VERSION 5.7 ;
  NOWIREEXTENSIONATPIN ON ;
  DIVIDERCHAR "/" ;
  BUSBITCHARS "[]" ;
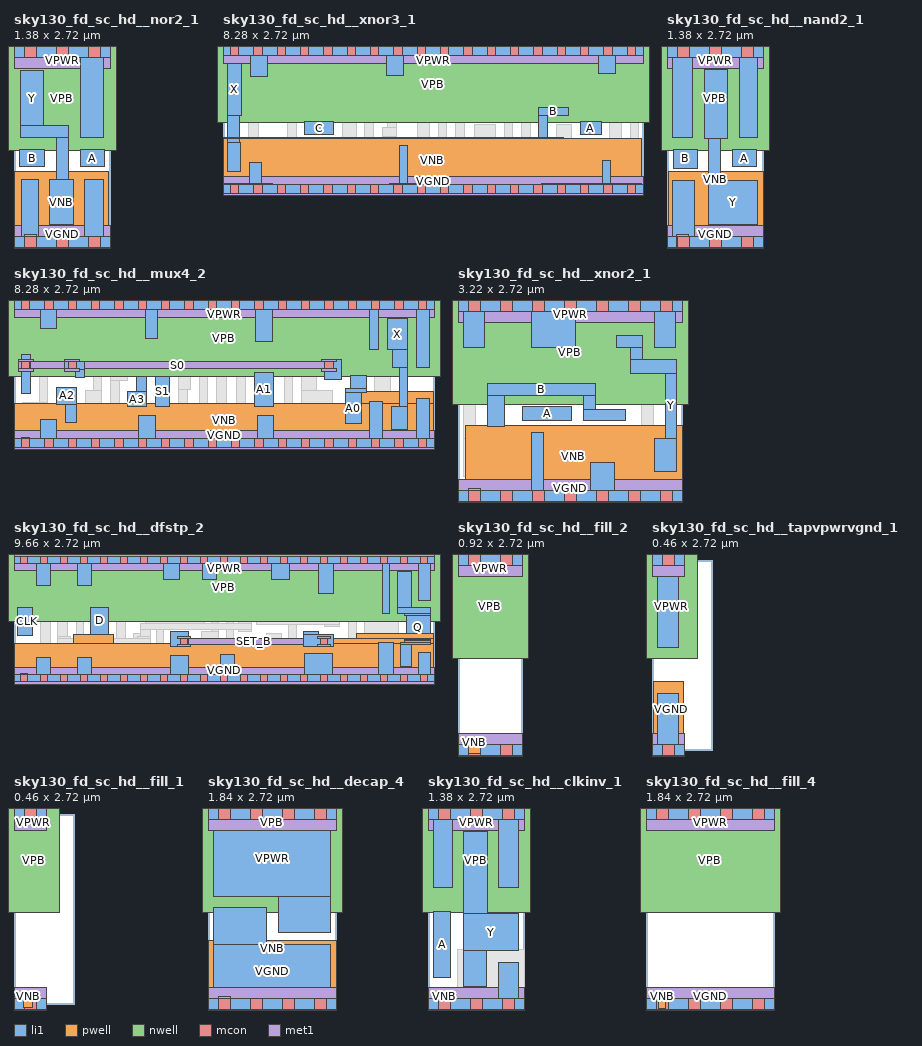
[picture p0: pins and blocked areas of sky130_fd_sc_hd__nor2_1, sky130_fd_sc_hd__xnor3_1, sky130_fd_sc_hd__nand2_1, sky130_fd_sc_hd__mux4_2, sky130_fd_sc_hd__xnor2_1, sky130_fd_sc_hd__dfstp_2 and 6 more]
MACRO sky130_fd_sc_hd__nor2_1
  CLASS BLOCK ;
  FOREIGN sky130_fd_sc_hd__nor2_1 ;
  ORIGIN 0.000 0.000 ;
  SIZE 1.380 BY 2.720 ;
  PIN B
    ANTENNAGATEAREA 0.247500 ;
    PORT
      LAYER li1 ;
        RECT 0.085 1.075 0.435 1.325 ;
    END
  END B
  PIN Y
    ANTENNADIFFAREA 0.435500 ;
    PORT
      LAYER li1 ;
        RECT 0.095 1.665 0.425 2.450 ;
        RECT 0.095 1.495 0.775 1.665 ;
        RECT 0.605 0.895 0.775 1.495 ;
        RECT 0.515 0.255 0.845 0.895 ;
    END
  END Y
  PIN A
    ANTENNAGATEAREA 0.247500 ;
    PORT
      LAYER li1 ;
        RECT 0.945 1.075 1.295 1.325 ;
    END
  END A
  PIN VNB
    PORT
      LAYER pwell ;
        RECT 0.005 0.105 1.355 1.015 ;
        RECT 0.150 -0.085 0.320 0.105 ;
    END
  END VNB
  PIN VPB
    PORT
      LAYER nwell ;
        RECT -0.190 1.305 1.570 2.910 ;
    END
  END VPB
  PIN VGND
    USE GROUND ;
    PORT
      LAYER li1 ;
        RECT 0.105 0.085 0.345 0.895 ;
        RECT 1.015 0.085 1.285 0.895 ;
        RECT 0.000 -0.085 1.380 0.085 ;
      LAYER mcon ;
        RECT 0.145 -0.085 0.315 0.085 ;
        RECT 0.605 -0.085 0.775 0.085 ;
        RECT 1.065 -0.085 1.235 0.085 ;
      LAYER met1 ;
        RECT 0.000 -0.240 1.380 0.240 ;
    END
  END VGND
  PIN VPWR
    USE POWER ;
    PORT
      LAYER li1 ;
        RECT 0.000 2.635 1.380 2.805 ;
        RECT 0.955 1.495 1.285 2.635 ;
      LAYER mcon ;
        RECT 0.145 2.635 0.315 2.805 ;
        RECT 0.605 2.635 0.775 2.805 ;
        RECT 1.065 2.635 1.235 2.805 ;
      LAYER met1 ;
        RECT 0.000 2.480 1.380 2.960 ;
    END
  END VPWR
END sky130_fd_sc_hd__nor2_1
MACRO VIA_M2M3_PR
  CLASS BLOCK ;
  FOREIGN VIA_M2M3_PR ;
  ORIGIN 0.165 0.185 ;
  SIZE 0.330 BY 0.370 ;
  OBS
      LAYER met2 ;
        RECT -0.140 -0.185 0.140 0.185 ;
      LAYER via2 ;
        RECT -0.140 -0.140 0.140 0.140 ;
      LAYER met3 ;
        RECT -0.165 -0.165 0.165 0.165 ;
  END
END VIA_M2M3_PR
MACRO sky130_fd_sc_hd__xnor3_1
  CLASS BLOCK ;
  FOREIGN sky130_fd_sc_hd__xnor3_1 ;
  ORIGIN 0.000 0.000 ;
  SIZE 8.280 BY 2.720 ;
  PIN X
    ANTENNADIFFAREA 0.449000 ;
    PORT
      LAYER li1 ;
        RECT 0.085 1.440 0.365 2.465 ;
        RECT 0.085 0.925 0.330 1.440 ;
        RECT 0.085 0.350 0.345 0.925 ;
    END
  END X
  PIN B
    ANTENNAGATEAREA 0.661500 ;
    PORT
      LAYER li1 ;
        RECT 6.225 1.445 6.805 1.615 ;
        RECT 6.225 0.995 6.395 1.445 ;
    END
  END B
  PIN C
    ANTENNAGATEAREA 0.381000 ;
    PORT
      LAYER li1 ;
        RECT 1.615 1.075 2.180 1.325 ;
    END
  END C
  PIN A
    ANTENNAGATEAREA 0.246000 ;
    PORT
      LAYER li1 ;
        RECT 7.045 1.075 7.455 1.325 ;
    END
  END A
  PIN VNB
    PORT
      LAYER pwell ;
        RECT 0.005 1.005 6.705 1.015 ;
        RECT 0.005 0.115 8.260 1.005 ;
        RECT 0.005 0.105 0.985 0.115 ;
        RECT 3.275 0.105 4.225 0.115 ;
        RECT 6.280 0.105 8.260 0.115 ;
        RECT 0.145 -0.085 0.315 0.105 ;
    END
  END VNB
  PIN VPB
    PORT
      LAYER nwell ;
        RECT -0.190 1.305 8.470 2.910 ;
    END
  END VPB
  PIN VGND
    USE GROUND ;
    PORT
      LAYER li1 ;
        RECT 0.515 0.085 0.765 0.525 ;
        RECT 3.475 0.085 3.645 0.865 ;
        RECT 7.475 0.085 7.645 0.565 ;
        RECT 0.000 -0.085 8.280 0.085 ;
      LAYER mcon ;
        RECT 0.145 -0.085 0.315 0.085 ;
        RECT 0.605 -0.085 0.775 0.085 ;
        RECT 1.065 -0.085 1.235 0.085 ;
        RECT 1.525 -0.085 1.695 0.085 ;
        RECT 1.985 -0.085 2.155 0.085 ;
        RECT 2.445 -0.085 2.615 0.085 ;
        RECT 2.905 -0.085 3.075 0.085 ;
        RECT 3.365 -0.085 3.535 0.085 ;
        RECT 3.825 -0.085 3.995 0.085 ;
        RECT 4.285 -0.085 4.455 0.085 ;
        RECT 4.745 -0.085 4.915 0.085 ;
        RECT 5.205 -0.085 5.375 0.085 ;
        RECT 5.665 -0.085 5.835 0.085 ;
        RECT 6.125 -0.085 6.295 0.085 ;
        RECT 6.585 -0.085 6.755 0.085 ;
        RECT 7.045 -0.085 7.215 0.085 ;
        RECT 7.505 -0.085 7.675 0.085 ;
        RECT 7.965 -0.085 8.135 0.085 ;
      LAYER met1 ;
        RECT 0.000 -0.240 8.280 0.240 ;
    END
  END VGND
  PIN VPWR
    USE POWER ;
    PORT
      LAYER li1 ;
        RECT 0.000 2.635 8.280 2.805 ;
        RECT 0.535 2.215 0.870 2.635 ;
        RECT 3.225 2.235 3.555 2.635 ;
        RECT 7.395 2.275 7.730 2.635 ;
      LAYER mcon ;
        RECT 0.145 2.635 0.315 2.805 ;
        RECT 0.605 2.635 0.775 2.805 ;
        RECT 1.065 2.635 1.235 2.805 ;
        RECT 1.525 2.635 1.695 2.805 ;
        RECT 1.985 2.635 2.155 2.805 ;
        RECT 2.445 2.635 2.615 2.805 ;
        RECT 2.905 2.635 3.075 2.805 ;
        RECT 3.365 2.635 3.535 2.805 ;
        RECT 3.825 2.635 3.995 2.805 ;
        RECT 4.285 2.635 4.455 2.805 ;
        RECT 4.745 2.635 4.915 2.805 ;
        RECT 5.205 2.635 5.375 2.805 ;
        RECT 5.665 2.635 5.835 2.805 ;
        RECT 6.125 2.635 6.295 2.805 ;
        RECT 6.585 2.635 6.755 2.805 ;
        RECT 7.045 2.635 7.215 2.805 ;
        RECT 7.505 2.635 7.675 2.805 ;
        RECT 7.965 2.635 8.135 2.805 ;
      LAYER met1 ;
        RECT 0.000 2.480 8.280 2.960 ;
    END
  END VPWR
  OBS
      LAYER li1 ;
        RECT 1.050 2.235 2.520 2.405 ;
        RECT 3.890 2.275 6.985 2.445 ;
        RECT 1.050 2.045 1.220 2.235 ;
        RECT 3.890 2.065 4.060 2.275 ;
        RECT 0.535 1.875 1.220 2.045 ;
        RECT 1.560 1.895 4.060 2.065 ;
        RECT 0.535 1.325 0.705 1.875 ;
        RECT 0.935 1.535 2.520 1.705 ;
        RECT 0.500 0.995 0.705 1.325 ;
        RECT 0.530 0.865 0.705 0.995 ;
        RECT 0.530 0.695 1.105 0.865 ;
        RECT 0.935 0.425 1.105 0.695 ;
        RECT 1.275 0.595 1.445 1.535 ;
        RECT 2.350 1.325 2.520 1.535 ;
        RECT 2.690 1.525 3.075 1.695 ;
        RECT 2.795 1.375 3.075 1.525 ;
        RECT 2.350 0.995 2.625 1.325 ;
        RECT 1.745 0.795 2.125 0.905 ;
        RECT 2.795 0.795 2.965 1.375 ;
        RECT 3.245 1.205 3.415 1.895 ;
        RECT 3.645 1.445 4.065 1.715 ;
        RECT 1.745 0.625 2.965 0.795 ;
        RECT 3.135 1.035 3.415 1.205 ;
        RECT 3.135 0.455 3.305 1.035 ;
        RECT 2.070 0.425 2.505 0.455 ;
        RECT 0.935 0.255 2.505 0.425 ;
        RECT 2.675 0.285 3.305 0.455 ;
        RECT 3.825 0.415 4.065 1.445 ;
        RECT 4.245 0.595 4.415 2.105 ;
        RECT 4.585 0.890 4.755 2.275 ;
        RECT 7.900 2.105 8.195 2.465 ;
        RECT 4.935 1.615 5.350 2.045 ;
        RECT 5.885 1.935 8.195 2.105 ;
        RECT 4.935 1.445 5.715 1.615 ;
        RECT 4.950 0.995 5.375 1.270 ;
        RECT 4.585 0.825 4.795 0.890 ;
        RECT 4.585 0.720 4.995 0.825 ;
        RECT 4.625 0.655 4.995 0.720 ;
        RECT 4.245 0.485 4.455 0.595 ;
        RECT 4.245 0.265 4.655 0.485 ;
        RECT 4.825 0.320 4.995 0.655 ;
        RECT 5.165 0.630 5.375 0.995 ;
        RECT 5.545 0.425 5.715 1.445 ;
        RECT 5.885 0.595 6.055 1.935 ;
        RECT 7.710 1.875 8.195 1.935 ;
        RECT 6.975 1.495 7.795 1.705 ;
        RECT 7.625 1.325 7.795 1.495 ;
        RECT 6.565 0.945 6.875 1.275 ;
        RECT 7.625 0.995 7.855 1.325 ;
        RECT 6.565 0.730 6.770 0.945 ;
        RECT 7.625 0.905 7.795 0.995 ;
        RECT 7.055 0.750 7.795 0.905 ;
        RECT 7.015 0.735 7.795 0.750 ;
        RECT 6.225 0.425 6.690 0.465 ;
        RECT 5.545 0.255 6.690 0.425 ;
        RECT 7.015 0.295 7.305 0.735 ;
        RECT 8.025 0.585 8.195 1.875 ;
        RECT 7.895 0.255 8.195 0.585 ;
      LAYER mcon ;
        RECT 2.905 1.445 3.075 1.615 ;
        RECT 3.825 0.765 3.995 0.935 ;
        RECT 5.205 1.445 5.375 1.615 ;
        RECT 4.285 0.425 4.455 0.595 ;
        RECT 5.205 0.765 5.375 0.935 ;
        RECT 6.585 0.765 6.755 0.935 ;
        RECT 7.045 0.425 7.215 0.595 ;
      LAYER met1 ;
        RECT 2.845 1.600 3.135 1.645 ;
        RECT 5.145 1.600 5.435 1.645 ;
        RECT 2.845 1.460 5.435 1.600 ;
        RECT 2.845 1.415 3.135 1.460 ;
        RECT 5.145 1.415 5.435 1.460 ;
        RECT 3.765 0.920 4.055 0.965 ;
        RECT 5.145 0.920 5.435 0.965 ;
        RECT 6.525 0.920 6.815 0.965 ;
        RECT 3.765 0.780 6.815 0.920 ;
        RECT 3.765 0.735 4.055 0.780 ;
        RECT 5.145 0.735 5.435 0.780 ;
        RECT 6.525 0.735 6.815 0.780 ;
        RECT 4.225 0.580 4.515 0.625 ;
        RECT 6.985 0.580 7.275 0.625 ;
        RECT 4.225 0.440 7.275 0.580 ;
        RECT 4.225 0.395 4.515 0.440 ;
        RECT 6.985 0.395 7.275 0.440 ;
  END
END sky130_fd_sc_hd__xnor3_1
MACRO sky130_fd_sc_hd__nand2_1
  CLASS BLOCK ;
  FOREIGN sky130_fd_sc_hd__nand2_1 ;
  ORIGIN 0.000 0.000 ;
  SIZE 1.380 BY 2.720 ;
  PIN Y
    ANTENNADIFFAREA 0.439000 ;
    PORT
      LAYER li1 ;
        RECT 0.535 1.485 0.865 2.465 ;
        RECT 0.600 0.885 0.770 1.485 ;
        RECT 0.600 0.255 1.295 0.885 ;
    END
  END Y
  PIN B
    ANTENNAGATEAREA 0.247500 ;
    PORT
      LAYER li1 ;
        RECT 0.095 1.055 0.430 1.325 ;
    END
  END B
  PIN A
    ANTENNAGATEAREA 0.247500 ;
    PORT
      LAYER li1 ;
        RECT 0.940 1.075 1.275 1.325 ;
    END
  END A
  PIN VNB
    PORT
      LAYER pwell ;
        RECT 0.025 0.105 1.375 1.015 ;
        RECT 0.140 -0.085 0.310 0.105 ;
    END
  END VNB
  PIN VPB
    PORT
      LAYER nwell ;
        RECT -0.190 1.305 1.570 2.910 ;
    END
  END VPB
  PIN VGND
    USE GROUND ;
    PORT
      LAYER li1 ;
        RECT 0.085 0.085 0.395 0.885 ;
        RECT 0.000 -0.085 1.380 0.085 ;
      LAYER mcon ;
        RECT 0.145 -0.085 0.315 0.085 ;
        RECT 0.605 -0.085 0.775 0.085 ;
        RECT 1.065 -0.085 1.235 0.085 ;
      LAYER met1 ;
        RECT 0.000 -0.240 1.380 0.240 ;
    END
  END VGND
  PIN VPWR
    USE POWER ;
    PORT
      LAYER li1 ;
        RECT 0.000 2.635 1.380 2.805 ;
        RECT 0.085 1.495 0.365 2.635 ;
        RECT 1.035 1.495 1.295 2.635 ;
      LAYER mcon ;
        RECT 0.145 2.635 0.315 2.805 ;
        RECT 0.605 2.635 0.775 2.805 ;
        RECT 1.065 2.635 1.235 2.805 ;
      LAYER met1 ;
        RECT 0.000 2.480 1.380 2.960 ;
    END
  END VPWR
END sky130_fd_sc_hd__nand2_1
MACRO sky130_fd_sc_hd__mux4_2
  CLASS BLOCK ;
  FOREIGN sky130_fd_sc_hd__mux4_2 ;
  ORIGIN 0.000 0.000 ;
  SIZE 8.280 BY 2.720 ;
  PIN X
    ANTENNADIFFAREA 0.445500 ;
    PORT
      LAYER li1 ;
        RECT 7.355 1.835 7.765 2.455 ;
        RECT 7.455 1.495 7.765 1.835 ;
        RECT 7.595 0.725 7.765 1.495 ;
        RECT 7.435 0.265 7.765 0.725 ;
    END
  END X
  PIN S0
    ANTENNAGATEAREA 0.393000 ;
    PORT
      LAYER li1 ;
        RECT 0.145 0.975 0.325 1.745 ;
        RECT 1.005 1.445 1.390 1.615 ;
        RECT 1.220 1.285 1.390 1.445 ;
        RECT 6.125 1.245 6.465 1.645 ;
      LAYER mcon ;
        RECT 0.145 1.445 0.315 1.615 ;
        RECT 1.065 1.445 1.235 1.615 ;
        RECT 6.125 1.445 6.295 1.615 ;
      LAYER met1 ;
        RECT 0.085 1.600 0.375 1.645 ;
        RECT 1.005 1.600 1.295 1.645 ;
        RECT 6.065 1.600 6.355 1.645 ;
        RECT 0.085 1.460 6.355 1.600 ;
        RECT 0.085 1.415 0.375 1.460 ;
        RECT 1.005 1.415 1.295 1.460 ;
        RECT 6.065 1.415 6.355 1.460 ;
    END
  END S0
  PIN A2
    ANTENNAGATEAREA 0.159000 ;
    PORT
      LAYER li1 ;
        RECT 0.835 0.765 1.235 1.095 ;
        RECT 1.020 0.395 1.235 0.765 ;
    END
  END A2
  PIN A3
    ANTENNAGATEAREA 0.159000 ;
    PORT
      LAYER li1 ;
        RECT 2.410 1.015 2.615 1.320 ;
        RECT 2.240 0.715 2.615 1.015 ;
    END
  END A3
  PIN S1
    ANTENNAGATEAREA 0.303000 ;
    PORT
      LAYER li1 ;
        RECT 2.785 0.715 3.075 1.320 ;
    END
  END S1
  PIN A1
    ANTENNAGATEAREA 0.159000 ;
    PORT
      LAYER li1 ;
        RECT 4.745 0.715 5.115 1.395 ;
    END
  END A1
  PIN A0
    ANTENNAGATEAREA 0.159000 ;
    PORT
      LAYER li1 ;
        RECT 6.635 1.075 6.945 1.325 ;
        RECT 6.535 0.995 6.945 1.075 ;
        RECT 6.535 0.375 6.845 0.995 ;
    END
  END A0
  PIN VNB
    PORT
      LAYER pwell ;
        RECT 6.825 0.785 8.275 1.015 ;
        RECT 0.005 0.105 8.275 0.785 ;
        RECT 0.145 -0.085 0.315 0.105 ;
    END
  END VNB
  PIN VPB
    PORT
      LAYER nwell ;
        RECT -0.190 1.305 8.470 2.910 ;
    END
  END VPB
  PIN VGND
    USE GROUND ;
    PORT
      LAYER li1 ;
        RECT 0.515 0.085 0.845 0.465 ;
        RECT 2.450 0.085 2.780 0.545 ;
        RECT 4.795 0.085 5.125 0.545 ;
        RECT 7.015 0.085 7.265 0.815 ;
        RECT 7.935 0.085 8.190 0.885 ;
        RECT 0.000 -0.085 8.280 0.085 ;
      LAYER mcon ;
        RECT 0.145 -0.085 0.315 0.085 ;
        RECT 0.605 -0.085 0.775 0.085 ;
        RECT 1.065 -0.085 1.235 0.085 ;
        RECT 1.525 -0.085 1.695 0.085 ;
        RECT 1.985 -0.085 2.155 0.085 ;
        RECT 2.445 -0.085 2.615 0.085 ;
        RECT 2.905 -0.085 3.075 0.085 ;
        RECT 3.365 -0.085 3.535 0.085 ;
        RECT 3.825 -0.085 3.995 0.085 ;
        RECT 4.285 -0.085 4.455 0.085 ;
        RECT 4.745 -0.085 4.915 0.085 ;
        RECT 5.205 -0.085 5.375 0.085 ;
        RECT 5.665 -0.085 5.835 0.085 ;
        RECT 6.125 -0.085 6.295 0.085 ;
        RECT 6.585 -0.085 6.755 0.085 ;
        RECT 7.045 -0.085 7.215 0.085 ;
        RECT 7.505 -0.085 7.675 0.085 ;
        RECT 7.965 -0.085 8.135 0.085 ;
      LAYER met1 ;
        RECT 0.000 -0.240 8.280 0.240 ;
    END
  END VGND
  PIN VPWR
    USE POWER ;
    PORT
      LAYER li1 ;
        RECT 0.000 2.635 8.280 2.805 ;
        RECT 0.515 2.255 0.845 2.635 ;
        RECT 2.595 2.055 2.825 2.635 ;
        RECT 4.755 2.005 5.100 2.635 ;
        RECT 7.015 1.835 7.185 2.635 ;
        RECT 7.935 1.495 8.185 2.635 ;
      LAYER mcon ;
        RECT 0.145 2.635 0.315 2.805 ;
        RECT 0.605 2.635 0.775 2.805 ;
        RECT 1.065 2.635 1.235 2.805 ;
        RECT 1.525 2.635 1.695 2.805 ;
        RECT 1.985 2.635 2.155 2.805 ;
        RECT 2.445 2.635 2.615 2.805 ;
        RECT 2.905 2.635 3.075 2.805 ;
        RECT 3.365 2.635 3.535 2.805 ;
        RECT 3.825 2.635 3.995 2.805 ;
        RECT 4.285 2.635 4.455 2.805 ;
        RECT 4.745 2.635 4.915 2.805 ;
        RECT 5.205 2.635 5.375 2.805 ;
        RECT 5.665 2.635 5.835 2.805 ;
        RECT 6.125 2.635 6.295 2.805 ;
        RECT 6.585 2.635 6.755 2.805 ;
        RECT 7.045 2.635 7.215 2.805 ;
        RECT 7.505 2.635 7.675 2.805 ;
        RECT 7.965 2.635 8.135 2.805 ;
      LAYER met1 ;
        RECT 0.000 2.480 8.280 2.960 ;
    END
  END VPWR
  OBS
      LAYER li1 ;
        RECT 0.175 2.085 0.345 2.375 ;
        RECT 1.410 2.125 2.240 2.295 ;
        RECT 3.305 2.125 3.820 2.295 ;
        RECT 0.175 1.955 0.665 2.085 ;
        RECT 0.175 1.915 1.900 1.955 ;
        RECT 0.495 1.785 1.900 1.915 ;
        RECT 0.495 0.805 0.665 1.785 ;
        RECT 1.560 1.575 1.900 1.785 ;
        RECT 1.560 1.035 1.730 1.575 ;
        RECT 2.070 1.405 2.240 2.125 ;
        RECT 2.970 1.785 3.315 1.955 ;
        RECT 3.565 1.810 3.820 2.125 ;
        RECT 3.145 1.660 3.315 1.785 ;
        RECT 3.145 1.490 3.415 1.660 ;
        RECT 0.170 0.635 0.665 0.805 ;
        RECT 1.405 0.705 1.730 1.035 ;
        RECT 1.900 1.235 2.240 1.405 ;
        RECT 3.245 1.390 3.415 1.490 ;
        RECT 0.170 0.345 0.345 0.635 ;
        RECT 1.900 0.535 2.070 1.235 ;
        RECT 1.470 0.365 2.070 0.535 ;
        RECT 3.245 1.060 3.480 1.390 ;
        RECT 3.245 0.465 3.415 1.060 ;
        RECT 3.650 0.675 3.820 1.810 ;
        RECT 2.985 0.295 3.415 0.465 ;
        RECT 3.585 0.345 3.820 0.675 ;
        RECT 3.990 2.125 4.515 2.295 ;
        RECT 5.325 2.155 6.275 2.325 ;
        RECT 3.990 0.345 4.180 2.125 ;
        RECT 4.395 1.735 4.585 1.895 ;
        RECT 5.325 1.735 5.495 2.155 ;
        RECT 6.525 2.125 6.845 2.295 ;
        RECT 4.395 1.565 5.495 1.735 ;
        RECT 4.395 0.585 4.565 1.565 ;
        RECT 4.395 0.255 4.600 0.585 ;
        RECT 5.325 0.465 5.495 1.565 ;
        RECT 5.665 1.035 5.955 1.985 ;
        RECT 6.675 1.665 6.845 2.125 ;
        RECT 6.675 1.495 7.285 1.665 ;
        RECT 7.115 1.325 7.285 1.495 ;
        RECT 5.665 0.705 6.285 1.035 ;
        RECT 7.115 0.995 7.425 1.325 ;
        RECT 5.325 0.295 6.220 0.465 ;
      LAYER mcon ;
        RECT 1.985 2.125 2.155 2.295 ;
        RECT 3.365 2.125 3.535 2.295 ;
        RECT 1.525 1.785 1.695 1.955 ;
        RECT 4.285 2.125 4.455 2.295 ;
        RECT 6.585 2.125 6.755 2.295 ;
        RECT 5.665 1.785 5.835 1.955 ;
      LAYER met1 ;
        RECT 1.925 2.280 2.215 2.325 ;
        RECT 3.305 2.280 3.595 2.325 ;
        RECT 1.925 2.140 3.595 2.280 ;
        RECT 1.925 2.095 2.215 2.140 ;
        RECT 3.305 2.095 3.595 2.140 ;
        RECT 4.225 2.280 4.515 2.325 ;
        RECT 6.525 2.280 6.815 2.325 ;
        RECT 4.225 2.140 6.815 2.280 ;
        RECT 4.225 2.095 4.515 2.140 ;
        RECT 6.525 2.095 6.815 2.140 ;
        RECT 1.465 1.940 1.755 1.985 ;
        RECT 5.605 1.940 5.895 1.985 ;
        RECT 1.465 1.800 5.895 1.940 ;
        RECT 1.465 1.755 1.755 1.800 ;
        RECT 5.605 1.755 5.895 1.800 ;
  END
END sky130_fd_sc_hd__mux4_2
MACRO sky130_fd_sc_hd__xnor2_1
  CLASS BLOCK ;
  FOREIGN sky130_fd_sc_hd__xnor2_1 ;
  ORIGIN 0.000 0.000 ;
  SIZE 3.220 BY 2.720 ;
  PIN B
    ANTENNAGATEAREA 0.495000 ;
    PORT
      LAYER li1 ;
        RECT 0.425 1.445 1.965 1.615 ;
        RECT 0.425 0.995 0.670 1.445 ;
        RECT 1.795 1.245 1.965 1.445 ;
        RECT 1.795 1.075 2.395 1.245 ;
    END
  END B
  PIN Y
    ANTENNADIFFAREA 0.525000 ;
    PORT
      LAYER li1 ;
        RECT 2.265 2.125 2.645 2.295 ;
        RECT 2.475 1.955 2.645 2.125 ;
        RECT 2.475 1.755 3.135 1.955 ;
        RECT 2.965 0.825 3.135 1.755 ;
        RECT 2.815 0.345 3.135 0.825 ;
    END
  END Y
  PIN A
    ANTENNAGATEAREA 0.495000 ;
    PORT
      LAYER li1 ;
        RECT 0.930 1.075 1.625 1.275 ;
    END
  END A
  PIN VNB
    PORT
      LAYER pwell ;
        RECT 0.105 0.105 3.215 1.015 ;
        RECT 0.145 -0.085 0.315 0.105 ;
    END
  END VNB
  PIN VPB
    PORT
      LAYER nwell ;
        RECT -0.190 1.305 3.410 2.910 ;
    END
  END VPB
  PIN VGND
    USE GROUND ;
    PORT
      LAYER li1 ;
        RECT 1.055 0.085 1.225 0.905 ;
        RECT 1.895 0.085 2.245 0.475 ;
        RECT 0.000 -0.085 3.220 0.085 ;
      LAYER mcon ;
        RECT 0.145 -0.085 0.315 0.085 ;
        RECT 0.605 -0.085 0.775 0.085 ;
        RECT 1.065 -0.085 1.235 0.085 ;
        RECT 1.525 -0.085 1.695 0.085 ;
        RECT 1.985 -0.085 2.155 0.085 ;
        RECT 2.445 -0.085 2.615 0.085 ;
        RECT 2.905 -0.085 3.075 0.085 ;
      LAYER met1 ;
        RECT 0.000 -0.240 3.220 0.240 ;
    END
  END VGND
  PIN VPWR
    USE POWER ;
    PORT
      LAYER li1 ;
        RECT 0.000 2.635 3.220 2.805 ;
        RECT 0.085 2.125 0.385 2.635 ;
        RECT 1.055 2.125 1.685 2.635 ;
        RECT 2.815 2.125 3.115 2.635 ;
      LAYER mcon ;
        RECT 0.145 2.635 0.315 2.805 ;
        RECT 0.605 2.635 0.775 2.805 ;
        RECT 1.065 2.635 1.235 2.805 ;
        RECT 1.525 2.635 1.695 2.805 ;
        RECT 1.985 2.635 2.155 2.805 ;
        RECT 2.445 2.635 2.615 2.805 ;
        RECT 2.905 2.635 3.075 2.805 ;
      LAYER met1 ;
        RECT 0.000 2.480 3.220 2.960 ;
    END
  END VPWR
  OBS
      LAYER li1 ;
        RECT 0.555 1.955 0.885 2.465 ;
        RECT 0.085 1.785 2.305 1.955 ;
        RECT 0.085 0.825 0.255 1.785 ;
        RECT 2.135 1.585 2.305 1.785 ;
        RECT 2.135 1.415 2.795 1.585 ;
        RECT 2.625 0.995 2.795 1.415 ;
        RECT 1.395 0.825 2.305 0.905 ;
        RECT 0.085 0.280 0.550 0.825 ;
        RECT 1.395 0.735 2.645 0.825 ;
        RECT 1.395 0.255 1.725 0.735 ;
        RECT 2.135 0.655 2.645 0.735 ;
        RECT 2.415 0.255 2.645 0.655 ;
  END
END sky130_fd_sc_hd__xnor2_1
MACRO sky130_fd_sc_hd__dfstp_2
  CLASS BLOCK ;
  FOREIGN sky130_fd_sc_hd__dfstp_2 ;
  ORIGIN 0.000 0.000 ;
  SIZE 9.660 BY 2.720 ;
  PIN Q
    ANTENNADIFFAREA 0.445500 ;
    PORT
      LAYER li1 ;
        RECT 8.810 1.615 9.140 2.460 ;
        RECT 8.810 1.495 9.575 1.615 ;
        RECT 8.975 1.445 9.575 1.495 ;
        RECT 9.020 0.895 9.575 1.445 ;
        RECT 8.990 0.855 9.575 0.895 ;
        RECT 8.975 0.825 9.575 0.855 ;
        RECT 8.890 0.765 9.575 0.825 ;
        RECT 8.890 0.265 9.135 0.765 ;
    END
  END Q
  PIN D
    ANTENNAGATEAREA 0.222000 ;
    PORT
      LAYER li1 ;
        RECT 1.770 1.005 2.180 1.625 ;
    END
  END D
  PIN VPWR
    USE POWER ;
    PORT
      LAYER li1 ;
        RECT 0.000 2.635 9.660 2.805 ;
        RECT 0.515 2.135 0.845 2.635 ;
        RECT 1.455 2.135 1.785 2.635 ;
        RECT 3.430 2.255 3.810 2.635 ;
        RECT 4.330 2.255 4.660 2.635 ;
        RECT 5.920 2.255 6.340 2.635 ;
        RECT 7.010 1.945 7.340 2.635 ;
        RECT 8.470 1.495 8.640 2.635 ;
        RECT 9.310 1.785 9.575 2.635 ;
      LAYER mcon ;
        RECT 0.145 2.635 0.315 2.805 ;
        RECT 0.605 2.635 0.775 2.805 ;
        RECT 1.065 2.635 1.235 2.805 ;
        RECT 1.525 2.635 1.695 2.805 ;
        RECT 1.985 2.635 2.155 2.805 ;
        RECT 2.445 2.635 2.615 2.805 ;
        RECT 2.905 2.635 3.075 2.805 ;
        RECT 3.365 2.635 3.535 2.805 ;
        RECT 3.825 2.635 3.995 2.805 ;
        RECT 4.285 2.635 4.455 2.805 ;
        RECT 4.745 2.635 4.915 2.805 ;
        RECT 5.205 2.635 5.375 2.805 ;
        RECT 5.665 2.635 5.835 2.805 ;
        RECT 6.125 2.635 6.295 2.805 ;
        RECT 6.585 2.635 6.755 2.805 ;
        RECT 7.045 2.635 7.215 2.805 ;
        RECT 7.505 2.635 7.675 2.805 ;
        RECT 7.965 2.635 8.135 2.805 ;
        RECT 8.425 2.635 8.595 2.805 ;
        RECT 8.885 2.635 9.055 2.805 ;
        RECT 9.345 2.635 9.515 2.805 ;
      LAYER met1 ;
        RECT 0.000 2.480 9.660 2.960 ;
    END
  END VPWR
  PIN SET_B
    ANTENNAGATEAREA 0.252000 ;
    PORT
      LAYER li1 ;
        RECT 3.610 0.735 4.020 1.065 ;
        RECT 6.660 1.005 7.010 1.065 ;
        RECT 6.660 0.735 7.340 1.005 ;
      LAYER mcon ;
        RECT 3.825 0.765 3.995 0.935 ;
        RECT 7.045 0.765 7.215 0.935 ;
      LAYER met1 ;
        RECT 3.765 0.920 4.055 0.965 ;
        RECT 6.985 0.920 7.275 0.965 ;
        RECT 3.765 0.780 7.275 0.920 ;
        RECT 3.765 0.735 4.055 0.780 ;
        RECT 6.985 0.735 7.275 0.780 ;
    END
  END SET_B
  PIN CLK
    ANTENNAGATEAREA 0.159000 ;
    PORT
      LAYER li1 ;
        RECT 0.085 0.975 0.435 1.625 ;
    END
  END CLK
  PIN VGND
    USE GROUND ;
    PORT
      LAYER li1 ;
        RECT 0.515 0.085 0.845 0.465 ;
        RECT 1.455 0.085 1.785 0.465 ;
        RECT 3.610 0.085 4.020 0.525 ;
        RECT 4.760 0.085 5.080 0.545 ;
        RECT 6.690 0.085 7.330 0.565 ;
        RECT 8.390 0.085 8.720 0.825 ;
        RECT 9.305 0.085 9.575 0.595 ;
        RECT 0.000 -0.085 9.660 0.085 ;
      LAYER mcon ;
        RECT 0.145 -0.085 0.315 0.085 ;
        RECT 0.605 -0.085 0.775 0.085 ;
        RECT 1.065 -0.085 1.235 0.085 ;
        RECT 1.525 -0.085 1.695 0.085 ;
        RECT 1.985 -0.085 2.155 0.085 ;
        RECT 2.445 -0.085 2.615 0.085 ;
        RECT 2.905 -0.085 3.075 0.085 ;
        RECT 3.365 -0.085 3.535 0.085 ;
        RECT 3.825 -0.085 3.995 0.085 ;
        RECT 4.285 -0.085 4.455 0.085 ;
        RECT 4.745 -0.085 4.915 0.085 ;
        RECT 5.205 -0.085 5.375 0.085 ;
        RECT 5.665 -0.085 5.835 0.085 ;
        RECT 6.125 -0.085 6.295 0.085 ;
        RECT 6.585 -0.085 6.755 0.085 ;
        RECT 7.045 -0.085 7.215 0.085 ;
        RECT 7.505 -0.085 7.675 0.085 ;
        RECT 7.965 -0.085 8.135 0.085 ;
        RECT 8.425 -0.085 8.595 0.085 ;
        RECT 8.885 -0.085 9.055 0.085 ;
        RECT 9.345 -0.085 9.515 0.085 ;
      LAYER met1 ;
        RECT 0.000 -0.240 9.660 0.240 ;
    END
  END VGND
  PIN VNB
    PORT
      LAYER pwell ;
        RECT 1.365 0.785 2.285 1.005 ;
        RECT 7.880 0.905 9.650 1.015 ;
        RECT 6.950 0.785 9.650 0.905 ;
        RECT 0.005 0.105 9.650 0.785 ;
        RECT 0.145 -0.085 0.315 0.105 ;
    END
  END VNB
  PIN VPB
    PORT
      LAYER nwell ;
        RECT -0.190 1.305 9.850 2.910 ;
    END
  END VPB
  OBS
      LAYER li1 ;
        RECT 0.085 1.965 0.345 2.465 ;
        RECT 1.015 2.045 1.235 2.465 ;
        RECT 0.085 1.795 0.835 1.965 ;
        RECT 0.605 0.805 0.835 1.795 ;
        RECT 0.085 0.635 0.835 0.805 ;
        RECT 0.085 0.345 0.345 0.635 ;
        RECT 1.005 0.565 1.235 2.045 ;
        RECT 1.955 1.965 2.125 2.465 ;
        RECT 2.360 2.250 3.190 2.420 ;
        RECT 1.430 1.795 2.125 1.965 ;
        RECT 1.430 0.825 1.600 1.795 ;
        RECT 2.350 1.575 2.850 1.955 ;
        RECT 1.430 0.635 2.125 0.825 ;
        RECT 2.350 0.705 2.570 1.575 ;
        RECT 3.020 1.405 3.190 2.250 ;
        RECT 3.990 2.085 4.160 2.375 ;
        RECT 5.110 2.165 5.740 2.415 ;
        RECT 5.570 2.085 5.740 2.165 ;
        RECT 6.540 2.085 6.780 2.375 ;
        RECT 3.360 1.835 4.710 2.085 ;
        RECT 3.360 1.575 3.610 1.835 ;
        RECT 4.120 1.405 4.370 1.565 ;
        RECT 3.020 1.235 4.370 1.405 ;
        RECT 3.020 1.195 3.440 1.235 ;
        RECT 2.750 0.645 3.100 1.015 ;
        RECT 1.015 0.345 1.235 0.565 ;
        RECT 1.955 0.305 2.125 0.635 ;
        RECT 3.270 0.465 3.440 1.195 ;
        RECT 4.540 1.065 4.710 1.835 ;
        RECT 2.425 0.265 3.440 0.465 ;
        RECT 4.310 0.725 4.710 1.065 ;
        RECT 4.880 1.655 5.400 1.965 ;
        RECT 5.570 1.915 6.780 2.085 ;
        RECT 4.880 0.895 5.050 1.655 ;
        RECT 5.220 1.065 5.400 1.475 ;
        RECT 5.570 1.405 5.740 1.915 ;
        RECT 7.510 1.765 7.680 2.375 ;
        RECT 7.970 1.915 8.300 2.425 ;
        RECT 7.510 1.745 7.880 1.765 ;
        RECT 5.910 1.575 7.880 1.745 ;
        RECT 5.570 1.235 7.490 1.405 ;
        RECT 5.800 0.895 6.150 1.015 ;
        RECT 4.880 0.725 6.150 0.895 ;
        RECT 4.310 0.295 4.560 0.725 ;
        RECT 6.320 0.475 6.490 1.235 ;
        RECT 7.140 1.175 7.490 1.235 ;
        RECT 7.690 0.680 7.880 1.575 ;
        RECT 5.640 0.305 6.490 0.475 ;
        RECT 7.530 0.350 7.880 0.680 ;
        RECT 8.050 1.325 8.300 1.915 ;
        RECT 8.050 0.995 8.850 1.325 ;
        RECT 8.050 0.345 8.220 0.995 ;
      LAYER mcon ;
        RECT 0.605 1.785 0.775 1.955 ;
        RECT 1.065 0.765 1.235 0.935 ;
        RECT 2.445 1.785 2.615 1.955 ;
        RECT 2.905 0.765 3.075 0.935 ;
        RECT 5.205 1.785 5.375 1.955 ;
        RECT 5.225 1.105 5.395 1.275 ;
      LAYER met1 ;
        RECT 0.545 1.940 0.835 1.985 ;
        RECT 2.385 1.940 2.675 1.985 ;
        RECT 5.145 1.940 5.435 1.985 ;
        RECT 0.545 1.800 5.435 1.940 ;
        RECT 0.545 1.755 0.835 1.800 ;
        RECT 2.385 1.755 2.675 1.800 ;
        RECT 5.145 1.755 5.435 1.800 ;
        RECT 5.165 1.260 5.455 1.305 ;
        RECT 2.920 1.120 5.455 1.260 ;
        RECT 2.920 0.965 3.135 1.120 ;
        RECT 5.165 1.075 5.455 1.120 ;
        RECT 1.005 0.920 1.295 0.965 ;
        RECT 2.845 0.920 3.135 0.965 ;
        RECT 1.005 0.780 3.135 0.920 ;
        RECT 1.005 0.735 1.295 0.780 ;
        RECT 2.845 0.735 3.135 0.780 ;
  END
END sky130_fd_sc_hd__dfstp_2
MACRO VIA_via4_1600x1600
  CLASS BLOCK ;
  FOREIGN VIA_via4_1600x1600 ;
  ORIGIN 0.800 0.800 ;
  SIZE 1.600 BY 1.600 ;
  OBS
      LAYER met4 ;
        RECT -0.800 -0.800 0.800 0.800 ;
      LAYER via4 ;
        RECT -0.590 -0.590 0.590 0.590 ;
      LAYER met5 ;
        RECT -0.800 -0.800 0.800 0.800 ;
  END
END VIA_via4_1600x1600
MACRO VIA_via4_4200x1600
  CLASS BLOCK ;
  FOREIGN VIA_via4_4200x1600 ;
  ORIGIN 2.100 0.800 ;
  SIZE 4.200 BY 1.600 ;
  OBS
      LAYER met4 ;
        RECT -2.100 -0.800 2.100 0.800 ;
      LAYER via4 ;
        RECT -1.390 -0.590 -0.210 0.590 ;
        RECT 0.210 -0.590 1.390 0.590 ;
      LAYER met5 ;
        RECT -2.100 -0.800 2.100 0.800 ;
  END
END VIA_via4_4200x1600
MACRO sky130_fd_sc_hd__fill_2
  CLASS BLOCK ;
  FOREIGN sky130_fd_sc_hd__fill_2 ;
  ORIGIN 0.000 0.000 ;
  SIZE 0.920 BY 2.720 ;
  PIN VNB
    PORT
      LAYER pwell ;
        RECT 0.155 -0.050 0.315 0.060 ;
    END
  END VNB
  PIN VPB
    PORT
      LAYER nwell ;
        RECT -0.190 1.305 1.110 2.910 ;
    END
  END VPB
  PIN VGND
    USE GROUND ;
    PORT
      LAYER li1 ;
        RECT 0.000 -0.085 0.920 0.085 ;
      LAYER mcon ;
        RECT 0.145 -0.085 0.315 0.085 ;
        RECT 0.605 -0.085 0.775 0.085 ;
      LAYER met1 ;
        RECT 0.000 -0.240 0.920 0.240 ;
    END
  END VGND
  PIN VPWR
    USE POWER ;
    PORT
      LAYER li1 ;
        RECT 0.000 2.635 0.920 2.805 ;
      LAYER mcon ;
        RECT 0.145 2.635 0.315 2.805 ;
        RECT 0.605 2.635 0.775 2.805 ;
      LAYER met1 ;
        RECT 0.000 2.480 0.920 2.960 ;
    END
  END VPWR
END sky130_fd_sc_hd__fill_2
MACRO VIA_via3_1600x480
  CLASS BLOCK ;
  FOREIGN VIA_via3_1600x480 ;
  ORIGIN 0.800 0.240 ;
  SIZE 1.600 BY 0.480 ;
  OBS
      LAYER met3 ;
        RECT -0.800 -0.160 0.800 0.160 ;
      LAYER via3 ;
        RECT -0.760 -0.160 -0.440 0.160 ;
        RECT -0.360 -0.160 -0.040 0.160 ;
        RECT 0.040 -0.160 0.360 0.160 ;
        RECT 0.440 -0.160 0.760 0.160 ;
      LAYER met4 ;
        RECT -0.800 -0.240 0.800 0.240 ;
  END
END VIA_via3_1600x480
MACRO VIA_via_1600x480
  CLASS BLOCK ;
  FOREIGN VIA_via_1600x480 ;
  ORIGIN 0.800 0.240 ;
  SIZE 1.600 BY 0.480 ;
  OBS
      LAYER met1 ;
        RECT -0.800 -0.240 0.800 0.240 ;
      LAYER via ;
        RECT -0.770 -0.130 -0.510 0.130 ;
        RECT -0.450 -0.130 -0.190 0.130 ;
        RECT -0.130 -0.130 0.130 0.130 ;
        RECT 0.190 -0.130 0.450 0.130 ;
        RECT 0.510 -0.130 0.770 0.130 ;
      LAYER met2 ;
        RECT -0.770 -0.240 0.770 0.240 ;
  END
END VIA_via_1600x480
MACRO VIA_via2_1600x480
  CLASS BLOCK ;
  FOREIGN VIA_via2_1600x480 ;
  ORIGIN 0.800 0.240 ;
  SIZE 1.600 BY 0.480 ;
  OBS
      LAYER met2 ;
        RECT -0.740 -0.240 0.740 0.240 ;
      LAYER via2 ;
        RECT -0.740 -0.140 -0.460 0.140 ;
        RECT -0.340 -0.140 -0.060 0.140 ;
        RECT 0.060 -0.140 0.340 0.140 ;
        RECT 0.460 -0.140 0.740 0.140 ;
      LAYER met3 ;
        RECT -0.800 -0.165 0.800 0.165 ;
  END
END VIA_via2_1600x480
MACRO sky130_fd_sc_hd__tapvpwrvgnd_1
  CLASS BLOCK ;
  FOREIGN sky130_fd_sc_hd__tapvpwrvgnd_1 ;
  ORIGIN 0.000 0.000 ;
  SIZE 0.460 BY 2.720 ;
  PIN VPWR
    USE POWER ;
    PORT
      LAYER nwell ;
        RECT -0.190 1.305 0.650 2.910 ;
      LAYER li1 ;
        RECT 0.000 2.635 0.460 2.805 ;
        RECT 0.085 1.470 0.375 2.635 ;
      LAYER mcon ;
        RECT 0.145 2.635 0.315 2.805 ;
      LAYER met1 ;
        RECT 0.000 2.480 0.460 2.960 ;
    END
  END VPWR
  PIN VGND
    USE GROUND ;
    PORT
      LAYER pwell ;
        RECT 0.015 0.190 0.445 0.975 ;
      LAYER li1 ;
        RECT 0.085 0.085 0.375 0.810 ;
        RECT 0.000 -0.085 0.460 0.085 ;
      LAYER mcon ;
        RECT 0.145 -0.085 0.315 0.085 ;
      LAYER met1 ;
        RECT 0.000 -0.240 0.460 0.240 ;
    END
  END VGND
END sky130_fd_sc_hd__tapvpwrvgnd_1
MACRO sky130_fd_sc_hd__fill_1
  CLASS BLOCK ;
  FOREIGN sky130_fd_sc_hd__fill_1 ;
  ORIGIN 0.000 0.000 ;
  SIZE 0.460 BY 2.720 ;
  PIN VNB
    PORT
      LAYER pwell ;
        RECT 0.140 -0.055 0.260 0.055 ;
    END
  END VNB
  PIN VPB
    PORT
      LAYER nwell ;
        RECT -0.190 1.305 0.650 2.910 ;
    END
  END VPB
  PIN VPWR
    USE POWER ;
    PORT
      LAYER li1 ;
        RECT 0.000 2.635 0.460 2.805 ;
      LAYER mcon ;
        RECT 0.145 2.635 0.315 2.805 ;
      LAYER met1 ;
        RECT 0.000 2.480 0.460 2.960 ;
    END
  END VPWR
  PIN VGND
    USE GROUND ;
    PORT
      LAYER li1 ;
        RECT 0.000 -0.085 0.460 0.085 ;
      LAYER mcon ;
        RECT 0.145 -0.085 0.315 0.085 ;
      LAYER met1 ;
        RECT 0.000 -0.240 0.460 0.240 ;
    END
  END VGND
END sky130_fd_sc_hd__fill_1
MACRO sky130_fd_sc_hd__decap_4
  CLASS BLOCK ;
  FOREIGN sky130_fd_sc_hd__decap_4 ;
  ORIGIN 0.000 0.000 ;
  SIZE 1.840 BY 2.720 ;
  PIN VNB
    PORT
      LAYER pwell ;
        RECT 0.005 0.105 1.835 0.915 ;
        RECT 0.145 -0.085 0.315 0.105 ;
    END
  END VNB
  PIN VPB
    PORT
      LAYER nwell ;
        RECT -0.190 1.305 2.030 2.910 ;
    END
  END VPB
  PIN VGND
    USE GROUND ;
    PORT
      LAYER li1 ;
        RECT 0.085 0.855 0.835 1.375 ;
        RECT 0.085 0.085 1.755 0.855 ;
        RECT 0.000 -0.085 1.840 0.085 ;
      LAYER mcon ;
        RECT 0.145 -0.085 0.315 0.085 ;
        RECT 0.605 -0.085 0.775 0.085 ;
        RECT 1.065 -0.085 1.235 0.085 ;
        RECT 1.525 -0.085 1.695 0.085 ;
      LAYER met1 ;
        RECT 0.000 -0.240 1.840 0.240 ;
    END
  END VGND
  PIN VPWR
    USE POWER ;
    PORT
      LAYER li1 ;
        RECT 0.000 2.635 1.840 2.805 ;
        RECT 0.085 1.545 1.755 2.635 ;
        RECT 1.005 1.025 1.755 1.545 ;
      LAYER mcon ;
        RECT 0.145 2.635 0.315 2.805 ;
        RECT 0.605 2.635 0.775 2.805 ;
        RECT 1.065 2.635 1.235 2.805 ;
        RECT 1.525 2.635 1.695 2.805 ;
      LAYER met1 ;
        RECT 0.000 2.480 1.840 2.960 ;
    END
  END VPWR
END sky130_fd_sc_hd__decap_4
MACRO sky130_fd_sc_hd__clkinv_1
  CLASS BLOCK ;
  FOREIGN sky130_fd_sc_hd__clkinv_1 ;
  ORIGIN 0.000 0.000 ;
  SIZE 1.380 BY 2.720 ;
  PIN Y
    ANTENNADIFFAREA 0.336000 ;
    PORT
      LAYER li1 ;
        RECT 0.515 1.290 0.845 2.465 ;
        RECT 0.515 0.760 1.295 1.290 ;
        RECT 0.515 0.255 0.840 0.760 ;
    END
  END Y
  PIN A
    ANTENNAGATEAREA 0.315000 ;
    PORT
      LAYER li1 ;
        RECT 0.085 0.375 0.325 1.325 ;
    END
  END A
  PIN VNB
    PORT
      LAYER pwell ;
        RECT 0.145 -0.085 0.315 0.085 ;
    END
  END VNB
  PIN VPB
    PORT
      LAYER nwell ;
        RECT -0.190 1.305 1.570 2.910 ;
    END
  END VPB
  PIN VGND
    USE GROUND ;
    PORT
      LAYER li1 ;
        RECT 1.010 0.085 1.295 0.590 ;
        RECT 0.000 -0.085 1.380 0.085 ;
      LAYER mcon ;
        RECT 0.145 -0.085 0.315 0.085 ;
        RECT 0.605 -0.085 0.775 0.085 ;
        RECT 1.065 -0.085 1.235 0.085 ;
      LAYER met1 ;
        RECT 0.000 -0.240 1.380 0.240 ;
    END
  END VGND
  PIN VPWR
    USE POWER ;
    PORT
      LAYER li1 ;
        RECT 0.000 2.635 1.380 2.805 ;
        RECT 0.085 1.665 0.345 2.635 ;
        RECT 1.015 1.665 1.295 2.635 ;
      LAYER mcon ;
        RECT 0.145 2.635 0.315 2.805 ;
        RECT 0.605 2.635 0.775 2.805 ;
        RECT 1.065 2.635 1.235 2.805 ;
      LAYER met1 ;
        RECT 0.000 2.480 1.380 2.960 ;
    END
  END VPWR
  OBS
      LAYER pwell ;
        RECT 0.420 0.105 1.375 0.785 ;
  END
END sky130_fd_sc_hd__clkinv_1
MACRO sky130_fd_sc_hd__fill_4
  CLASS BLOCK ;
  FOREIGN sky130_fd_sc_hd__fill_4 ;
  ORIGIN 0.000 0.000 ;
  SIZE 1.840 BY 2.720 ;
  PIN VNB
    PORT
      LAYER pwell ;
        RECT 0.175 -0.060 0.285 0.060 ;
    END
  END VNB
  PIN VPB
    PORT
      LAYER nwell ;
        RECT -0.190 1.305 2.030 2.910 ;
    END
  END VPB
  PIN VGND
    USE GROUND ;
    PORT
      LAYER li1 ;
        RECT 0.000 -0.085 1.840 0.085 ;
      LAYER mcon ;
        RECT 0.145 -0.085 0.315 0.085 ;
        RECT 0.605 -0.085 0.775 0.085 ;
        RECT 1.065 -0.085 1.235 0.085 ;
        RECT 1.525 -0.085 1.695 0.085 ;
      LAYER met1 ;
        RECT 0.000 -0.240 1.840 0.240 ;
    END
  END VGND
  PIN VPWR
    USE POWER ;
    PORT
      LAYER li1 ;
        RECT 0.000 2.635 1.840 2.805 ;
      LAYER mcon ;
        RECT 0.145 2.635 0.315 2.805 ;
        RECT 0.605 2.635 0.775 2.805 ;
        RECT 1.065 2.635 1.235 2.805 ;
        RECT 1.525 2.635 1.695 2.805 ;
      LAYER met1 ;
        RECT 0.000 2.480 1.840 2.960 ;
    END
  END VPWR
END sky130_fd_sc_hd__fill_4
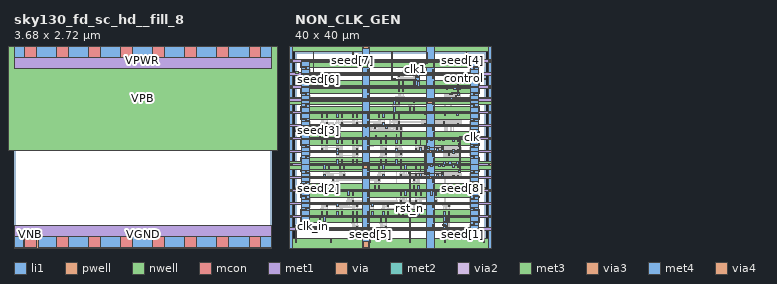
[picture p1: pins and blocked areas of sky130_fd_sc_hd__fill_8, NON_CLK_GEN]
MACRO sky130_fd_sc_hd__fill_8
  CLASS BLOCK ;
  FOREIGN sky130_fd_sc_hd__fill_8 ;
  ORIGIN 0.000 0.000 ;
  SIZE 3.680 BY 2.720 ;
  PIN VNB
    PORT
      LAYER pwell ;
        RECT 0.130 -0.120 0.350 0.050 ;
    END
  END VNB
  PIN VPB
    PORT
      LAYER nwell ;
        RECT -0.190 1.305 3.870 2.910 ;
    END
  END VPB
  PIN VGND
    USE GROUND ;
    PORT
      LAYER li1 ;
        RECT 0.000 -0.085 3.680 0.085 ;
      LAYER mcon ;
        RECT 0.145 -0.085 0.315 0.085 ;
        RECT 0.605 -0.085 0.775 0.085 ;
        RECT 1.065 -0.085 1.235 0.085 ;
        RECT 1.525 -0.085 1.695 0.085 ;
        RECT 1.985 -0.085 2.155 0.085 ;
        RECT 2.445 -0.085 2.615 0.085 ;
        RECT 2.905 -0.085 3.075 0.085 ;
        RECT 3.365 -0.085 3.535 0.085 ;
      LAYER met1 ;
        RECT 0.000 -0.240 3.680 0.240 ;
    END
  END VGND
  PIN VPWR
    USE POWER ;
    PORT
      LAYER li1 ;
        RECT 0.000 2.635 3.680 2.805 ;
      LAYER mcon ;
        RECT 0.145 2.635 0.315 2.805 ;
        RECT 0.605 2.635 0.775 2.805 ;
        RECT 1.065 2.635 1.235 2.805 ;
        RECT 1.525 2.635 1.695 2.805 ;
        RECT 1.985 2.635 2.155 2.805 ;
        RECT 2.445 2.635 2.615 2.805 ;
        RECT 2.905 2.635 3.075 2.805 ;
        RECT 3.365 2.635 3.535 2.805 ;
      LAYER met1 ;
        RECT 0.000 2.480 3.680 2.960 ;
    END
  END VPWR
END sky130_fd_sc_hd__fill_8
MACRO VIA_L1M1_PR
  CLASS BLOCK ;
  FOREIGN VIA_L1M1_PR ;
  ORIGIN 0.145 0.115 ;
  SIZE 0.290 BY 0.230 ;
  OBS
      LAYER li1 ;
        RECT -0.085 -0.085 0.085 0.085 ;
      LAYER met1 ;
        RECT -0.145 -0.115 0.145 0.115 ;
  END
END VIA_L1M1_PR
MACRO VIA_M1M2_PR
  CLASS BLOCK ;
  FOREIGN VIA_M1M2_PR ;
  ORIGIN 0.160 0.160 ;
  SIZE 0.320 BY 0.320 ;
  OBS
      LAYER met1 ;
        RECT -0.160 -0.130 0.160 0.130 ;
      LAYER via ;
        RECT -0.130 -0.130 0.130 0.130 ;
      LAYER met2 ;
        RECT -0.130 -0.160 0.130 0.160 ;
  END
END VIA_M1M2_PR
MACRO VIA_via3_4200x480
  CLASS BLOCK ;
  FOREIGN VIA_via3_4200x480 ;
  ORIGIN 2.100 0.240 ;
  SIZE 4.200 BY 0.480 ;
  OBS
      LAYER met3 ;
        RECT -2.100 -0.160 2.100 0.160 ;
      LAYER via3 ;
        RECT -1.960 -0.160 -1.640 0.160 ;
        RECT -1.560 -0.160 -1.240 0.160 ;
        RECT -1.160 -0.160 -0.840 0.160 ;
        RECT -0.760 -0.160 -0.440 0.160 ;
        RECT -0.360 -0.160 -0.040 0.160 ;
        RECT 0.040 -0.160 0.360 0.160 ;
        RECT 0.440 -0.160 0.760 0.160 ;
        RECT 0.840 -0.160 1.160 0.160 ;
        RECT 1.240 -0.160 1.560 0.160 ;
        RECT 1.640 -0.160 1.960 0.160 ;
      LAYER met4 ;
        RECT -2.100 -0.240 2.100 0.240 ;
  END
END VIA_via3_4200x480
MACRO VIA_via2_4200x480
  CLASS BLOCK ;
  FOREIGN VIA_via2_4200x480 ;
  ORIGIN 2.100 0.240 ;
  SIZE 4.200 BY 0.480 ;
  OBS
      LAYER met2 ;
        RECT -1.940 -0.240 1.940 0.240 ;
      LAYER via2 ;
        RECT -1.940 -0.140 -1.660 0.140 ;
        RECT -1.540 -0.140 -1.260 0.140 ;
        RECT -1.140 -0.140 -0.860 0.140 ;
        RECT -0.740 -0.140 -0.460 0.140 ;
        RECT -0.340 -0.140 -0.060 0.140 ;
        RECT 0.060 -0.140 0.340 0.140 ;
        RECT 0.460 -0.140 0.740 0.140 ;
        RECT 0.860 -0.140 1.140 0.140 ;
        RECT 1.260 -0.140 1.540 0.140 ;
        RECT 1.660 -0.140 1.940 0.140 ;
      LAYER met3 ;
        RECT -2.100 -0.165 2.100 0.165 ;
  END
END VIA_via2_4200x480
MACRO VIA_via_4200x480
  CLASS BLOCK ;
  FOREIGN VIA_via_4200x480 ;
  ORIGIN 2.100 0.240 ;
  SIZE 4.200 BY 0.480 ;
  OBS
      LAYER met1 ;
        RECT -2.100 -0.240 2.100 0.240 ;
      LAYER via ;
        RECT -2.050 -0.130 -1.790 0.130 ;
        RECT -1.730 -0.130 -1.470 0.130 ;
        RECT -1.410 -0.130 -1.150 0.130 ;
        RECT -1.090 -0.130 -0.830 0.130 ;
        RECT -0.770 -0.130 -0.510 0.130 ;
        RECT -0.450 -0.130 -0.190 0.130 ;
        RECT -0.130 -0.130 0.130 0.130 ;
        RECT 0.190 -0.130 0.450 0.130 ;
        RECT 0.510 -0.130 0.770 0.130 ;
        RECT 0.830 -0.130 1.090 0.130 ;
        RECT 1.150 -0.130 1.410 0.130 ;
        RECT 1.470 -0.130 1.730 0.130 ;
        RECT 1.790 -0.130 2.050 0.130 ;
      LAYER met2 ;
        RECT -2.050 -0.240 2.050 0.240 ;
  END
END VIA_via_4200x480
MACRO VIA_via4_1600x4200
  CLASS BLOCK ;
  FOREIGN VIA_via4_1600x4200 ;
  ORIGIN 0.800 2.100 ;
  SIZE 1.600 BY 4.200 ;
  OBS
      LAYER met4 ;
        RECT -0.800 -2.100 0.800 2.100 ;
      LAYER via4 ;
        RECT -0.590 0.210 0.590 1.390 ;
        RECT -0.590 -1.390 0.590 -0.210 ;
      LAYER met5 ;
        RECT -0.800 -2.100 0.800 2.100 ;
  END
END VIA_via4_1600x4200
MACRO VIA_via4_4200x4200
  CLASS BLOCK ;
  FOREIGN VIA_via4_4200x4200 ;
  ORIGIN 2.100 2.100 ;
  SIZE 4.200 BY 4.200 ;
  OBS
      LAYER met4 ;
        RECT -2.100 -2.100 2.100 2.100 ;
      LAYER via4 ;
        RECT -1.390 -1.390 1.390 1.390 ;
      LAYER met5 ;
        RECT -2.100 -2.100 2.100 2.100 ;
  END
END VIA_via4_4200x4200
MACRO NON_CLK_GEN
  CLASS BLOCK ;
  FOREIGN NON_CLK_GEN ;
  ORIGIN 0.000 0.000 ;
  SIZE 40.000 BY 40.000 ;
  PIN VPWR
    ANTENNAGATEAREA 15.014999 ;
    ANTENNADIFFAREA 42.626400 ;
    PORT
      LAYER nwell ;
        RECT 1.190 36.665 38.830 38.270 ;
        RECT 1.190 31.225 38.830 34.055 ;
        RECT 1.190 25.785 38.830 28.615 ;
        RECT 1.190 20.345 38.830 23.175 ;
        RECT 1.190 14.905 38.830 17.735 ;
        RECT 1.190 9.465 38.830 12.295 ;
        RECT 1.190 4.025 38.830 6.855 ;
      LAYER li1 ;
        RECT 1.380 37.995 38.640 38.165 ;
        RECT 1.465 36.905 3.135 37.995 ;
        RECT 2.385 36.385 3.135 36.905 ;
        RECT 15.265 36.830 15.555 37.995 ;
        RECT 24.465 37.025 24.725 37.995 ;
        RECT 25.395 37.025 25.675 37.995 ;
        RECT 29.065 36.830 29.355 37.995 ;
        RECT 36.885 36.905 38.555 37.995 ;
        RECT 36.885 36.385 37.635 36.905 ;
        RECT 2.385 33.815 3.135 34.335 ;
        RECT 1.465 32.725 3.135 33.815 ;
        RECT 5.605 32.725 5.885 33.695 ;
        RECT 6.555 32.725 6.815 33.695 ;
        RECT 21.705 32.725 21.985 33.695 ;
        RECT 22.655 32.725 22.915 33.695 ;
        RECT 24.925 32.725 25.185 33.695 ;
        RECT 25.855 32.725 26.135 33.695 ;
        RECT 29.065 32.725 29.355 33.890 ;
        RECT 36.885 33.815 37.635 34.335 ;
        RECT 36.885 32.725 38.555 33.815 ;
        RECT 1.380 32.555 38.640 32.725 ;
        RECT 1.465 31.465 3.135 32.555 ;
        RECT 2.385 30.945 3.135 31.465 ;
        RECT 15.265 31.390 15.555 32.555 ;
        RECT 21.705 31.585 21.965 32.555 ;
        RECT 22.635 31.585 22.915 32.555 ;
        RECT 31.845 32.045 32.145 32.555 ;
        RECT 33.275 32.045 33.905 32.555 ;
        RECT 34.575 32.045 34.875 32.555 ;
        RECT 36.885 31.465 38.555 32.555 ;
        RECT 36.885 30.945 37.635 31.465 ;
        RECT 2.385 28.375 3.135 28.895 ;
        RECT 1.465 27.285 3.135 28.375 ;
        RECT 20.795 27.285 21.125 28.425 ;
        RECT 24.005 27.285 24.265 28.255 ;
        RECT 24.935 27.285 25.215 28.255 ;
        RECT 29.065 27.285 29.355 28.450 ;
        RECT 36.885 28.375 37.635 28.895 ;
        RECT 36.885 27.285 38.555 28.375 ;
        RECT 1.380 27.115 38.640 27.285 ;
        RECT 1.465 26.025 3.135 27.115 ;
        RECT 5.605 26.145 5.865 27.115 ;
        RECT 6.535 26.145 6.815 27.115 ;
        RECT 8.825 26.145 9.085 27.115 ;
        RECT 9.755 26.145 10.035 27.115 ;
        RECT 12.045 26.145 12.305 27.115 ;
        RECT 12.975 26.145 13.255 27.115 ;
        RECT 2.385 25.505 3.135 26.025 ;
        RECT 15.265 25.950 15.555 27.115 ;
        RECT 17.565 26.145 17.825 27.115 ;
        RECT 18.495 26.145 18.775 27.115 ;
        RECT 20.785 25.975 21.045 27.115 ;
        RECT 21.715 25.975 21.995 27.115 ;
        RECT 27.230 26.755 27.565 27.115 ;
        RECT 31.405 26.715 31.735 27.115 ;
        RECT 34.090 26.695 34.425 27.115 ;
        RECT 36.885 26.025 38.555 27.115 ;
        RECT 36.885 25.505 37.635 26.025 ;
        RECT 2.385 22.935 3.135 23.455 ;
        RECT 1.465 21.845 3.135 22.935 ;
        RECT 5.145 21.845 5.425 22.815 ;
        RECT 6.095 21.845 6.355 22.815 ;
        RECT 8.365 21.845 8.625 22.815 ;
        RECT 9.295 21.845 9.575 22.815 ;
        RECT 14.775 21.845 15.105 22.225 ;
        RECT 16.855 21.845 17.085 22.425 ;
        RECT 19.015 21.845 19.360 22.475 ;
        RECT 21.275 21.845 21.445 22.645 ;
        RECT 22.195 21.845 22.445 22.985 ;
        RECT 29.065 21.845 29.355 23.010 ;
        RECT 36.885 22.935 37.635 23.455 ;
        RECT 36.885 21.845 38.555 22.935 ;
        RECT 1.380 21.675 38.640 21.845 ;
        RECT 1.465 20.585 3.135 21.675 ;
        RECT 5.605 20.705 5.885 21.675 ;
        RECT 6.555 20.705 6.815 21.675 ;
        RECT 8.825 20.705 9.105 21.675 ;
        RECT 9.775 20.705 10.035 21.675 ;
        RECT 12.045 20.705 12.305 21.675 ;
        RECT 12.975 20.705 13.255 21.675 ;
        RECT 2.385 20.065 3.135 20.585 ;
        RECT 15.265 20.510 15.555 21.675 ;
        RECT 18.025 20.705 18.285 21.675 ;
        RECT 18.955 20.705 19.235 21.675 ;
        RECT 21.245 20.705 21.525 21.675 ;
        RECT 22.195 20.705 22.455 21.675 ;
        RECT 25.385 20.825 25.650 21.675 ;
        RECT 26.320 20.535 26.490 21.675 ;
        RECT 27.620 20.985 27.950 21.675 ;
        RECT 28.620 21.295 29.040 21.675 ;
        RECT 30.300 21.295 30.630 21.675 ;
        RECT 31.150 21.295 31.530 21.675 ;
        RECT 33.175 21.175 33.505 21.675 ;
        RECT 34.115 21.175 34.445 21.675 ;
        RECT 36.885 20.585 38.555 21.675 ;
        RECT 36.885 20.065 37.635 20.585 ;
        RECT 2.385 17.495 3.135 18.015 ;
        RECT 1.465 16.405 3.135 17.495 ;
        RECT 8.825 16.405 9.105 17.375 ;
        RECT 9.775 16.405 10.035 17.375 ;
        RECT 12.045 16.405 12.305 17.375 ;
        RECT 12.975 16.405 13.255 17.375 ;
        RECT 18.025 16.405 18.285 17.375 ;
        RECT 18.955 16.405 19.235 17.375 ;
        RECT 21.245 16.405 21.505 17.375 ;
        RECT 22.175 16.405 22.455 17.375 ;
        RECT 29.065 16.405 29.355 17.570 ;
        RECT 36.885 17.495 37.635 18.015 ;
        RECT 31.365 16.405 31.665 16.915 ;
        RECT 32.335 16.405 32.965 16.915 ;
        RECT 34.095 16.405 34.395 16.915 ;
        RECT 36.885 16.405 38.555 17.495 ;
        RECT 1.380 16.235 38.640 16.405 ;
        RECT 1.465 15.145 3.135 16.235 ;
        RECT 6.065 15.265 6.345 16.235 ;
        RECT 7.015 15.265 7.275 16.235 ;
        RECT 9.285 15.265 9.545 16.235 ;
        RECT 10.215 15.265 10.495 16.235 ;
        RECT 2.385 14.625 3.135 15.145 ;
        RECT 15.265 15.070 15.555 16.235 ;
        RECT 17.565 15.265 17.825 16.235 ;
        RECT 18.495 15.265 18.775 16.235 ;
        RECT 22.165 15.265 22.445 16.235 ;
        RECT 23.115 15.265 23.375 16.235 ;
        RECT 25.385 15.385 25.650 16.235 ;
        RECT 26.320 15.095 26.490 16.235 ;
        RECT 27.620 15.545 27.950 16.235 ;
        RECT 28.620 15.855 29.040 16.235 ;
        RECT 30.300 15.855 30.630 16.235 ;
        RECT 31.150 15.855 31.530 16.235 ;
        RECT 33.175 15.735 33.505 16.235 ;
        RECT 34.115 15.735 34.445 16.235 ;
        RECT 36.885 15.145 38.555 16.235 ;
        RECT 36.885 14.625 37.635 15.145 ;
        RECT 2.385 12.055 3.135 12.575 ;
        RECT 1.465 10.965 3.135 12.055 ;
        RECT 7.905 10.965 8.185 11.935 ;
        RECT 8.855 10.965 9.115 11.935 ;
        RECT 16.645 10.965 16.905 11.935 ;
        RECT 17.575 10.965 17.855 11.935 ;
        RECT 24.925 10.965 25.205 11.935 ;
        RECT 25.875 10.965 26.135 11.935 ;
        RECT 29.065 10.965 29.355 12.130 ;
        RECT 36.885 12.055 37.635 12.575 ;
        RECT 36.885 10.965 38.555 12.055 ;
        RECT 1.380 10.795 38.640 10.965 ;
        RECT 1.465 9.705 3.135 10.795 ;
        RECT 11.125 9.825 11.385 10.795 ;
        RECT 12.055 9.825 12.335 10.795 ;
        RECT 2.385 9.185 3.135 9.705 ;
        RECT 15.265 9.630 15.555 10.795 ;
        RECT 22.165 9.825 22.445 10.795 ;
        RECT 23.115 9.825 23.375 10.795 ;
        RECT 25.385 9.825 25.665 10.795 ;
        RECT 26.335 9.825 26.595 10.795 ;
        RECT 28.605 9.825 28.865 10.795 ;
        RECT 29.535 9.825 29.815 10.795 ;
        RECT 36.885 9.705 38.555 10.795 ;
        RECT 36.885 9.185 37.635 9.705 ;
        RECT 2.385 6.615 3.135 7.135 ;
        RECT 1.465 5.525 3.135 6.615 ;
        RECT 5.605 5.525 5.865 6.495 ;
        RECT 6.535 5.525 6.815 6.495 ;
        RECT 8.825 5.525 9.105 6.495 ;
        RECT 9.775 5.525 10.035 6.495 ;
        RECT 12.045 5.525 12.305 6.495 ;
        RECT 12.975 5.525 13.255 6.495 ;
        RECT 15.265 5.525 15.525 6.495 ;
        RECT 16.195 5.525 16.475 6.495 ;
        RECT 18.485 5.525 18.745 6.495 ;
        RECT 19.415 5.525 19.695 6.495 ;
        RECT 21.705 5.525 21.965 6.495 ;
        RECT 22.635 5.525 22.915 6.495 ;
        RECT 24.925 5.525 25.185 6.495 ;
        RECT 25.855 5.525 26.135 6.495 ;
        RECT 29.065 5.525 29.355 6.690 ;
        RECT 36.885 6.615 37.635 7.135 ;
        RECT 31.365 5.525 31.625 6.495 ;
        RECT 32.295 5.525 32.575 6.495 ;
        RECT 36.885 5.525 38.555 6.615 ;
        RECT 1.380 5.355 38.640 5.525 ;
        RECT 1.465 4.265 3.135 5.355 ;
        RECT 5.145 4.385 5.405 5.355 ;
        RECT 6.075 4.385 6.355 5.355 ;
        RECT 12.045 4.385 12.305 5.355 ;
        RECT 12.975 4.385 13.255 5.355 ;
        RECT 2.385 3.745 3.135 4.265 ;
        RECT 15.265 4.190 15.555 5.355 ;
        RECT 18.025 4.385 18.285 5.355 ;
        RECT 18.955 4.385 19.235 5.355 ;
        RECT 29.065 4.190 29.355 5.355 ;
        RECT 31.365 4.385 31.645 5.355 ;
        RECT 32.315 4.385 32.575 5.355 ;
        RECT 36.885 4.265 38.555 5.355 ;
        RECT 36.885 3.745 37.635 4.265 ;
      LAYER mcon ;
        RECT 1.525 37.995 1.695 38.165 ;
        RECT 1.985 37.995 2.155 38.165 ;
        RECT 2.445 37.995 2.615 38.165 ;
        RECT 2.905 37.995 3.075 38.165 ;
        RECT 3.365 37.995 3.535 38.165 ;
        RECT 3.825 37.995 3.995 38.165 ;
        RECT 4.285 37.995 4.455 38.165 ;
        RECT 4.745 37.995 4.915 38.165 ;
        RECT 5.205 37.995 5.375 38.165 ;
        RECT 5.665 37.995 5.835 38.165 ;
        RECT 6.125 37.995 6.295 38.165 ;
        RECT 6.585 37.995 6.755 38.165 ;
        RECT 7.045 37.995 7.215 38.165 ;
        RECT 7.505 37.995 7.675 38.165 ;
        RECT 7.965 37.995 8.135 38.165 ;
        RECT 8.425 37.995 8.595 38.165 ;
        RECT 8.885 37.995 9.055 38.165 ;
        RECT 9.345 37.995 9.515 38.165 ;
        RECT 9.805 37.995 9.975 38.165 ;
        RECT 10.265 37.995 10.435 38.165 ;
        RECT 10.725 37.995 10.895 38.165 ;
        RECT 11.185 37.995 11.355 38.165 ;
        RECT 11.645 37.995 11.815 38.165 ;
        RECT 12.105 37.995 12.275 38.165 ;
        RECT 12.565 37.995 12.735 38.165 ;
        RECT 13.025 37.995 13.195 38.165 ;
        RECT 13.485 37.995 13.655 38.165 ;
        RECT 13.945 37.995 14.115 38.165 ;
        RECT 14.405 37.995 14.575 38.165 ;
        RECT 14.865 37.995 15.035 38.165 ;
        RECT 15.325 37.995 15.495 38.165 ;
        RECT 15.785 37.995 15.955 38.165 ;
        RECT 16.245 37.995 16.415 38.165 ;
        RECT 16.705 37.995 16.875 38.165 ;
        RECT 17.165 37.995 17.335 38.165 ;
        RECT 17.625 37.995 17.795 38.165 ;
        RECT 18.085 37.995 18.255 38.165 ;
        RECT 18.545 37.995 18.715 38.165 ;
        RECT 19.005 37.995 19.175 38.165 ;
        RECT 19.465 37.995 19.635 38.165 ;
        RECT 19.925 37.995 20.095 38.165 ;
        RECT 20.385 37.995 20.555 38.165 ;
        RECT 20.845 37.995 21.015 38.165 ;
        RECT 21.305 37.995 21.475 38.165 ;
        RECT 21.765 37.995 21.935 38.165 ;
        RECT 22.225 37.995 22.395 38.165 ;
        RECT 22.685 37.995 22.855 38.165 ;
        RECT 23.145 37.995 23.315 38.165 ;
        RECT 23.605 37.995 23.775 38.165 ;
        RECT 24.065 37.995 24.235 38.165 ;
        RECT 24.525 37.995 24.695 38.165 ;
        RECT 24.985 37.995 25.155 38.165 ;
        RECT 25.445 37.995 25.615 38.165 ;
        RECT 25.905 37.995 26.075 38.165 ;
        RECT 26.365 37.995 26.535 38.165 ;
        RECT 26.825 37.995 26.995 38.165 ;
        RECT 27.285 37.995 27.455 38.165 ;
        RECT 27.745 37.995 27.915 38.165 ;
        RECT 28.205 37.995 28.375 38.165 ;
        RECT 28.665 37.995 28.835 38.165 ;
        RECT 29.125 37.995 29.295 38.165 ;
        RECT 29.585 37.995 29.755 38.165 ;
        RECT 30.045 37.995 30.215 38.165 ;
        RECT 30.505 37.995 30.675 38.165 ;
        RECT 30.965 37.995 31.135 38.165 ;
        RECT 31.425 37.995 31.595 38.165 ;
        RECT 31.885 37.995 32.055 38.165 ;
        RECT 32.345 37.995 32.515 38.165 ;
        RECT 32.805 37.995 32.975 38.165 ;
        RECT 33.265 37.995 33.435 38.165 ;
        RECT 33.725 37.995 33.895 38.165 ;
        RECT 34.185 37.995 34.355 38.165 ;
        RECT 34.645 37.995 34.815 38.165 ;
        RECT 35.105 37.995 35.275 38.165 ;
        RECT 35.565 37.995 35.735 38.165 ;
        RECT 36.025 37.995 36.195 38.165 ;
        RECT 36.485 37.995 36.655 38.165 ;
        RECT 36.945 37.995 37.115 38.165 ;
        RECT 37.405 37.995 37.575 38.165 ;
        RECT 37.865 37.995 38.035 38.165 ;
        RECT 38.325 37.995 38.495 38.165 ;
        RECT 1.525 32.555 1.695 32.725 ;
        RECT 1.985 32.555 2.155 32.725 ;
        RECT 2.445 32.555 2.615 32.725 ;
        RECT 2.905 32.555 3.075 32.725 ;
        RECT 3.365 32.555 3.535 32.725 ;
        RECT 3.825 32.555 3.995 32.725 ;
        RECT 4.285 32.555 4.455 32.725 ;
        RECT 4.745 32.555 4.915 32.725 ;
        RECT 5.205 32.555 5.375 32.725 ;
        RECT 5.665 32.555 5.835 32.725 ;
        RECT 6.125 32.555 6.295 32.725 ;
        RECT 6.585 32.555 6.755 32.725 ;
        RECT 7.045 32.555 7.215 32.725 ;
        RECT 7.505 32.555 7.675 32.725 ;
        RECT 7.965 32.555 8.135 32.725 ;
        RECT 8.425 32.555 8.595 32.725 ;
        RECT 8.885 32.555 9.055 32.725 ;
        RECT 9.345 32.555 9.515 32.725 ;
        RECT 9.805 32.555 9.975 32.725 ;
        RECT 10.265 32.555 10.435 32.725 ;
        RECT 10.725 32.555 10.895 32.725 ;
        RECT 11.185 32.555 11.355 32.725 ;
        RECT 11.645 32.555 11.815 32.725 ;
        RECT 12.105 32.555 12.275 32.725 ;
        RECT 12.565 32.555 12.735 32.725 ;
        RECT 13.025 32.555 13.195 32.725 ;
        RECT 13.485 32.555 13.655 32.725 ;
        RECT 13.945 32.555 14.115 32.725 ;
        RECT 14.405 32.555 14.575 32.725 ;
        RECT 14.865 32.555 15.035 32.725 ;
        RECT 15.325 32.555 15.495 32.725 ;
        RECT 15.785 32.555 15.955 32.725 ;
        RECT 16.245 32.555 16.415 32.725 ;
        RECT 16.705 32.555 16.875 32.725 ;
        RECT 17.165 32.555 17.335 32.725 ;
        RECT 17.625 32.555 17.795 32.725 ;
        RECT 18.085 32.555 18.255 32.725 ;
        RECT 18.545 32.555 18.715 32.725 ;
        RECT 19.005 32.555 19.175 32.725 ;
        RECT 19.465 32.555 19.635 32.725 ;
        RECT 19.925 32.555 20.095 32.725 ;
        RECT 20.385 32.555 20.555 32.725 ;
        RECT 20.845 32.555 21.015 32.725 ;
        RECT 21.305 32.555 21.475 32.725 ;
        RECT 21.765 32.555 21.935 32.725 ;
        RECT 22.225 32.555 22.395 32.725 ;
        RECT 22.685 32.555 22.855 32.725 ;
        RECT 23.145 32.555 23.315 32.725 ;
        RECT 23.605 32.555 23.775 32.725 ;
        RECT 24.065 32.555 24.235 32.725 ;
        RECT 24.525 32.555 24.695 32.725 ;
        RECT 24.985 32.555 25.155 32.725 ;
        RECT 25.445 32.555 25.615 32.725 ;
        RECT 25.905 32.555 26.075 32.725 ;
        RECT 26.365 32.555 26.535 32.725 ;
        RECT 26.825 32.555 26.995 32.725 ;
        RECT 27.285 32.555 27.455 32.725 ;
        RECT 27.745 32.555 27.915 32.725 ;
        RECT 28.205 32.555 28.375 32.725 ;
        RECT 28.665 32.555 28.835 32.725 ;
        RECT 29.125 32.555 29.295 32.725 ;
        RECT 29.585 32.555 29.755 32.725 ;
        RECT 30.045 32.555 30.215 32.725 ;
        RECT 30.505 32.555 30.675 32.725 ;
        RECT 30.965 32.555 31.135 32.725 ;
        RECT 31.425 32.555 31.595 32.725 ;
        RECT 31.885 32.555 32.055 32.725 ;
        RECT 32.345 32.555 32.515 32.725 ;
        RECT 32.805 32.555 32.975 32.725 ;
        RECT 33.265 32.555 33.435 32.725 ;
        RECT 33.725 32.555 33.895 32.725 ;
        RECT 34.185 32.555 34.355 32.725 ;
        RECT 34.645 32.555 34.815 32.725 ;
        RECT 35.105 32.555 35.275 32.725 ;
        RECT 35.565 32.555 35.735 32.725 ;
        RECT 36.025 32.555 36.195 32.725 ;
        RECT 36.485 32.555 36.655 32.725 ;
        RECT 36.945 32.555 37.115 32.725 ;
        RECT 37.405 32.555 37.575 32.725 ;
        RECT 37.865 32.555 38.035 32.725 ;
        RECT 38.325 32.555 38.495 32.725 ;
        RECT 1.525 27.115 1.695 27.285 ;
        RECT 1.985 27.115 2.155 27.285 ;
        RECT 2.445 27.115 2.615 27.285 ;
        RECT 2.905 27.115 3.075 27.285 ;
        RECT 3.365 27.115 3.535 27.285 ;
        RECT 3.825 27.115 3.995 27.285 ;
        RECT 4.285 27.115 4.455 27.285 ;
        RECT 4.745 27.115 4.915 27.285 ;
        RECT 5.205 27.115 5.375 27.285 ;
        RECT 5.665 27.115 5.835 27.285 ;
        RECT 6.125 27.115 6.295 27.285 ;
        RECT 6.585 27.115 6.755 27.285 ;
        RECT 7.045 27.115 7.215 27.285 ;
        RECT 7.505 27.115 7.675 27.285 ;
        RECT 7.965 27.115 8.135 27.285 ;
        RECT 8.425 27.115 8.595 27.285 ;
        RECT 8.885 27.115 9.055 27.285 ;
        RECT 9.345 27.115 9.515 27.285 ;
        RECT 9.805 27.115 9.975 27.285 ;
        RECT 10.265 27.115 10.435 27.285 ;
        RECT 10.725 27.115 10.895 27.285 ;
        RECT 11.185 27.115 11.355 27.285 ;
        RECT 11.645 27.115 11.815 27.285 ;
        RECT 12.105 27.115 12.275 27.285 ;
        RECT 12.565 27.115 12.735 27.285 ;
        RECT 13.025 27.115 13.195 27.285 ;
        RECT 13.485 27.115 13.655 27.285 ;
        RECT 13.945 27.115 14.115 27.285 ;
        RECT 14.405 27.115 14.575 27.285 ;
        RECT 14.865 27.115 15.035 27.285 ;
        RECT 15.325 27.115 15.495 27.285 ;
        RECT 15.785 27.115 15.955 27.285 ;
        RECT 16.245 27.115 16.415 27.285 ;
        RECT 16.705 27.115 16.875 27.285 ;
        RECT 17.165 27.115 17.335 27.285 ;
        RECT 17.625 27.115 17.795 27.285 ;
        RECT 18.085 27.115 18.255 27.285 ;
        RECT 18.545 27.115 18.715 27.285 ;
        RECT 19.005 27.115 19.175 27.285 ;
        RECT 19.465 27.115 19.635 27.285 ;
        RECT 19.925 27.115 20.095 27.285 ;
        RECT 20.385 27.115 20.555 27.285 ;
        RECT 20.845 27.115 21.015 27.285 ;
        RECT 21.305 27.115 21.475 27.285 ;
        RECT 21.765 27.115 21.935 27.285 ;
        RECT 22.225 27.115 22.395 27.285 ;
        RECT 22.685 27.115 22.855 27.285 ;
        RECT 23.145 27.115 23.315 27.285 ;
        RECT 23.605 27.115 23.775 27.285 ;
        RECT 24.065 27.115 24.235 27.285 ;
        RECT 24.525 27.115 24.695 27.285 ;
        RECT 24.985 27.115 25.155 27.285 ;
        RECT 25.445 27.115 25.615 27.285 ;
        RECT 25.905 27.115 26.075 27.285 ;
        RECT 26.365 27.115 26.535 27.285 ;
        RECT 26.825 27.115 26.995 27.285 ;
        RECT 27.285 27.115 27.455 27.285 ;
        RECT 27.745 27.115 27.915 27.285 ;
        RECT 28.205 27.115 28.375 27.285 ;
        RECT 28.665 27.115 28.835 27.285 ;
        RECT 29.125 27.115 29.295 27.285 ;
        RECT 29.585 27.115 29.755 27.285 ;
        RECT 30.045 27.115 30.215 27.285 ;
        RECT 30.505 27.115 30.675 27.285 ;
        RECT 30.965 27.115 31.135 27.285 ;
        RECT 31.425 27.115 31.595 27.285 ;
        RECT 31.885 27.115 32.055 27.285 ;
        RECT 32.345 27.115 32.515 27.285 ;
        RECT 32.805 27.115 32.975 27.285 ;
        RECT 33.265 27.115 33.435 27.285 ;
        RECT 33.725 27.115 33.895 27.285 ;
        RECT 34.185 27.115 34.355 27.285 ;
        RECT 34.645 27.115 34.815 27.285 ;
        RECT 35.105 27.115 35.275 27.285 ;
        RECT 35.565 27.115 35.735 27.285 ;
        RECT 36.025 27.115 36.195 27.285 ;
        RECT 36.485 27.115 36.655 27.285 ;
        RECT 36.945 27.115 37.115 27.285 ;
        RECT 37.405 27.115 37.575 27.285 ;
        RECT 37.865 27.115 38.035 27.285 ;
        RECT 38.325 27.115 38.495 27.285 ;
        RECT 1.525 21.675 1.695 21.845 ;
        RECT 1.985 21.675 2.155 21.845 ;
        RECT 2.445 21.675 2.615 21.845 ;
        RECT 2.905 21.675 3.075 21.845 ;
        RECT 3.365 21.675 3.535 21.845 ;
        RECT 3.825 21.675 3.995 21.845 ;
        RECT 4.285 21.675 4.455 21.845 ;
        RECT 4.745 21.675 4.915 21.845 ;
        RECT 5.205 21.675 5.375 21.845 ;
        RECT 5.665 21.675 5.835 21.845 ;
        RECT 6.125 21.675 6.295 21.845 ;
        RECT 6.585 21.675 6.755 21.845 ;
        RECT 7.045 21.675 7.215 21.845 ;
        RECT 7.505 21.675 7.675 21.845 ;
        RECT 7.965 21.675 8.135 21.845 ;
        RECT 8.425 21.675 8.595 21.845 ;
        RECT 8.885 21.675 9.055 21.845 ;
        RECT 9.345 21.675 9.515 21.845 ;
        RECT 9.805 21.675 9.975 21.845 ;
        RECT 10.265 21.675 10.435 21.845 ;
        RECT 10.725 21.675 10.895 21.845 ;
        RECT 11.185 21.675 11.355 21.845 ;
        RECT 11.645 21.675 11.815 21.845 ;
        RECT 12.105 21.675 12.275 21.845 ;
        RECT 12.565 21.675 12.735 21.845 ;
        RECT 13.025 21.675 13.195 21.845 ;
        RECT 13.485 21.675 13.655 21.845 ;
        RECT 13.945 21.675 14.115 21.845 ;
        RECT 14.405 21.675 14.575 21.845 ;
        RECT 14.865 21.675 15.035 21.845 ;
        RECT 15.325 21.675 15.495 21.845 ;
        RECT 15.785 21.675 15.955 21.845 ;
        RECT 16.245 21.675 16.415 21.845 ;
        RECT 16.705 21.675 16.875 21.845 ;
        RECT 17.165 21.675 17.335 21.845 ;
        RECT 17.625 21.675 17.795 21.845 ;
        RECT 18.085 21.675 18.255 21.845 ;
        RECT 18.545 21.675 18.715 21.845 ;
        RECT 19.005 21.675 19.175 21.845 ;
        RECT 19.465 21.675 19.635 21.845 ;
        RECT 19.925 21.675 20.095 21.845 ;
        RECT 20.385 21.675 20.555 21.845 ;
        RECT 20.845 21.675 21.015 21.845 ;
        RECT 21.305 21.675 21.475 21.845 ;
        RECT 21.765 21.675 21.935 21.845 ;
        RECT 22.225 21.675 22.395 21.845 ;
        RECT 22.685 21.675 22.855 21.845 ;
        RECT 23.145 21.675 23.315 21.845 ;
        RECT 23.605 21.675 23.775 21.845 ;
        RECT 24.065 21.675 24.235 21.845 ;
        RECT 24.525 21.675 24.695 21.845 ;
        RECT 24.985 21.675 25.155 21.845 ;
        RECT 25.445 21.675 25.615 21.845 ;
        RECT 25.905 21.675 26.075 21.845 ;
        RECT 26.365 21.675 26.535 21.845 ;
        RECT 26.825 21.675 26.995 21.845 ;
        RECT 27.285 21.675 27.455 21.845 ;
        RECT 27.745 21.675 27.915 21.845 ;
        RECT 28.205 21.675 28.375 21.845 ;
        RECT 28.665 21.675 28.835 21.845 ;
        RECT 29.125 21.675 29.295 21.845 ;
        RECT 29.585 21.675 29.755 21.845 ;
        RECT 30.045 21.675 30.215 21.845 ;
        RECT 30.505 21.675 30.675 21.845 ;
        RECT 30.965 21.675 31.135 21.845 ;
        RECT 31.425 21.675 31.595 21.845 ;
        RECT 31.885 21.675 32.055 21.845 ;
        RECT 32.345 21.675 32.515 21.845 ;
        RECT 32.805 21.675 32.975 21.845 ;
        RECT 33.265 21.675 33.435 21.845 ;
        RECT 33.725 21.675 33.895 21.845 ;
        RECT 34.185 21.675 34.355 21.845 ;
        RECT 34.645 21.675 34.815 21.845 ;
        RECT 35.105 21.675 35.275 21.845 ;
        RECT 35.565 21.675 35.735 21.845 ;
        RECT 36.025 21.675 36.195 21.845 ;
        RECT 36.485 21.675 36.655 21.845 ;
        RECT 36.945 21.675 37.115 21.845 ;
        RECT 37.405 21.675 37.575 21.845 ;
        RECT 37.865 21.675 38.035 21.845 ;
        RECT 38.325 21.675 38.495 21.845 ;
        RECT 1.525 16.235 1.695 16.405 ;
        RECT 1.985 16.235 2.155 16.405 ;
        RECT 2.445 16.235 2.615 16.405 ;
        RECT 2.905 16.235 3.075 16.405 ;
        RECT 3.365 16.235 3.535 16.405 ;
        RECT 3.825 16.235 3.995 16.405 ;
        RECT 4.285 16.235 4.455 16.405 ;
        RECT 4.745 16.235 4.915 16.405 ;
        RECT 5.205 16.235 5.375 16.405 ;
        RECT 5.665 16.235 5.835 16.405 ;
        RECT 6.125 16.235 6.295 16.405 ;
        RECT 6.585 16.235 6.755 16.405 ;
        RECT 7.045 16.235 7.215 16.405 ;
        RECT 7.505 16.235 7.675 16.405 ;
        RECT 7.965 16.235 8.135 16.405 ;
        RECT 8.425 16.235 8.595 16.405 ;
        RECT 8.885 16.235 9.055 16.405 ;
        RECT 9.345 16.235 9.515 16.405 ;
        RECT 9.805 16.235 9.975 16.405 ;
        RECT 10.265 16.235 10.435 16.405 ;
        RECT 10.725 16.235 10.895 16.405 ;
        RECT 11.185 16.235 11.355 16.405 ;
        RECT 11.645 16.235 11.815 16.405 ;
        RECT 12.105 16.235 12.275 16.405 ;
        RECT 12.565 16.235 12.735 16.405 ;
        RECT 13.025 16.235 13.195 16.405 ;
        RECT 13.485 16.235 13.655 16.405 ;
        RECT 13.945 16.235 14.115 16.405 ;
        RECT 14.405 16.235 14.575 16.405 ;
        RECT 14.865 16.235 15.035 16.405 ;
        RECT 15.325 16.235 15.495 16.405 ;
        RECT 15.785 16.235 15.955 16.405 ;
        RECT 16.245 16.235 16.415 16.405 ;
        RECT 16.705 16.235 16.875 16.405 ;
        RECT 17.165 16.235 17.335 16.405 ;
        RECT 17.625 16.235 17.795 16.405 ;
        RECT 18.085 16.235 18.255 16.405 ;
        RECT 18.545 16.235 18.715 16.405 ;
        RECT 19.005 16.235 19.175 16.405 ;
        RECT 19.465 16.235 19.635 16.405 ;
        RECT 19.925 16.235 20.095 16.405 ;
        RECT 20.385 16.235 20.555 16.405 ;
        RECT 20.845 16.235 21.015 16.405 ;
        RECT 21.305 16.235 21.475 16.405 ;
        RECT 21.765 16.235 21.935 16.405 ;
        RECT 22.225 16.235 22.395 16.405 ;
        RECT 22.685 16.235 22.855 16.405 ;
        RECT 23.145 16.235 23.315 16.405 ;
        RECT 23.605 16.235 23.775 16.405 ;
        RECT 24.065 16.235 24.235 16.405 ;
        RECT 24.525 16.235 24.695 16.405 ;
        RECT 24.985 16.235 25.155 16.405 ;
        RECT 25.445 16.235 25.615 16.405 ;
        RECT 25.905 16.235 26.075 16.405 ;
        RECT 26.365 16.235 26.535 16.405 ;
        RECT 26.825 16.235 26.995 16.405 ;
        RECT 27.285 16.235 27.455 16.405 ;
        RECT 27.745 16.235 27.915 16.405 ;
        RECT 28.205 16.235 28.375 16.405 ;
        RECT 28.665 16.235 28.835 16.405 ;
        RECT 29.125 16.235 29.295 16.405 ;
        RECT 29.585 16.235 29.755 16.405 ;
        RECT 30.045 16.235 30.215 16.405 ;
        RECT 30.505 16.235 30.675 16.405 ;
        RECT 30.965 16.235 31.135 16.405 ;
        RECT 31.425 16.235 31.595 16.405 ;
        RECT 31.885 16.235 32.055 16.405 ;
        RECT 32.345 16.235 32.515 16.405 ;
        RECT 32.805 16.235 32.975 16.405 ;
        RECT 33.265 16.235 33.435 16.405 ;
        RECT 33.725 16.235 33.895 16.405 ;
        RECT 34.185 16.235 34.355 16.405 ;
        RECT 34.645 16.235 34.815 16.405 ;
        RECT 35.105 16.235 35.275 16.405 ;
        RECT 35.565 16.235 35.735 16.405 ;
        RECT 36.025 16.235 36.195 16.405 ;
        RECT 36.485 16.235 36.655 16.405 ;
        RECT 36.945 16.235 37.115 16.405 ;
        RECT 37.405 16.235 37.575 16.405 ;
        RECT 37.865 16.235 38.035 16.405 ;
        RECT 38.325 16.235 38.495 16.405 ;
        RECT 1.525 10.795 1.695 10.965 ;
        RECT 1.985 10.795 2.155 10.965 ;
        RECT 2.445 10.795 2.615 10.965 ;
        RECT 2.905 10.795 3.075 10.965 ;
        RECT 3.365 10.795 3.535 10.965 ;
        RECT 3.825 10.795 3.995 10.965 ;
        RECT 4.285 10.795 4.455 10.965 ;
        RECT 4.745 10.795 4.915 10.965 ;
        RECT 5.205 10.795 5.375 10.965 ;
        RECT 5.665 10.795 5.835 10.965 ;
        RECT 6.125 10.795 6.295 10.965 ;
        RECT 6.585 10.795 6.755 10.965 ;
        RECT 7.045 10.795 7.215 10.965 ;
        RECT 7.505 10.795 7.675 10.965 ;
        RECT 7.965 10.795 8.135 10.965 ;
        RECT 8.425 10.795 8.595 10.965 ;
        RECT 8.885 10.795 9.055 10.965 ;
        RECT 9.345 10.795 9.515 10.965 ;
        RECT 9.805 10.795 9.975 10.965 ;
        RECT 10.265 10.795 10.435 10.965 ;
        RECT 10.725 10.795 10.895 10.965 ;
        RECT 11.185 10.795 11.355 10.965 ;
        RECT 11.645 10.795 11.815 10.965 ;
        RECT 12.105 10.795 12.275 10.965 ;
        RECT 12.565 10.795 12.735 10.965 ;
        RECT 13.025 10.795 13.195 10.965 ;
        RECT 13.485 10.795 13.655 10.965 ;
        RECT 13.945 10.795 14.115 10.965 ;
        RECT 14.405 10.795 14.575 10.965 ;
        RECT 14.865 10.795 15.035 10.965 ;
        RECT 15.325 10.795 15.495 10.965 ;
        RECT 15.785 10.795 15.955 10.965 ;
        RECT 16.245 10.795 16.415 10.965 ;
        RECT 16.705 10.795 16.875 10.965 ;
        RECT 17.165 10.795 17.335 10.965 ;
        RECT 17.625 10.795 17.795 10.965 ;
        RECT 18.085 10.795 18.255 10.965 ;
        RECT 18.545 10.795 18.715 10.965 ;
        RECT 19.005 10.795 19.175 10.965 ;
        RECT 19.465 10.795 19.635 10.965 ;
        RECT 19.925 10.795 20.095 10.965 ;
        RECT 20.385 10.795 20.555 10.965 ;
        RECT 20.845 10.795 21.015 10.965 ;
        RECT 21.305 10.795 21.475 10.965 ;
        RECT 21.765 10.795 21.935 10.965 ;
        RECT 22.225 10.795 22.395 10.965 ;
        RECT 22.685 10.795 22.855 10.965 ;
        RECT 23.145 10.795 23.315 10.965 ;
        RECT 23.605 10.795 23.775 10.965 ;
        RECT 24.065 10.795 24.235 10.965 ;
        RECT 24.525 10.795 24.695 10.965 ;
        RECT 24.985 10.795 25.155 10.965 ;
        RECT 25.445 10.795 25.615 10.965 ;
        RECT 25.905 10.795 26.075 10.965 ;
        RECT 26.365 10.795 26.535 10.965 ;
        RECT 26.825 10.795 26.995 10.965 ;
        RECT 27.285 10.795 27.455 10.965 ;
        RECT 27.745 10.795 27.915 10.965 ;
        RECT 28.205 10.795 28.375 10.965 ;
        RECT 28.665 10.795 28.835 10.965 ;
        RECT 29.125 10.795 29.295 10.965 ;
        RECT 29.585 10.795 29.755 10.965 ;
        RECT 30.045 10.795 30.215 10.965 ;
        RECT 30.505 10.795 30.675 10.965 ;
        RECT 30.965 10.795 31.135 10.965 ;
        RECT 31.425 10.795 31.595 10.965 ;
        RECT 31.885 10.795 32.055 10.965 ;
        RECT 32.345 10.795 32.515 10.965 ;
        RECT 32.805 10.795 32.975 10.965 ;
        RECT 33.265 10.795 33.435 10.965 ;
        RECT 33.725 10.795 33.895 10.965 ;
        RECT 34.185 10.795 34.355 10.965 ;
        RECT 34.645 10.795 34.815 10.965 ;
        RECT 35.105 10.795 35.275 10.965 ;
        RECT 35.565 10.795 35.735 10.965 ;
        RECT 36.025 10.795 36.195 10.965 ;
        RECT 36.485 10.795 36.655 10.965 ;
        RECT 36.945 10.795 37.115 10.965 ;
        RECT 37.405 10.795 37.575 10.965 ;
        RECT 37.865 10.795 38.035 10.965 ;
        RECT 38.325 10.795 38.495 10.965 ;
        RECT 1.525 5.355 1.695 5.525 ;
        RECT 1.985 5.355 2.155 5.525 ;
        RECT 2.445 5.355 2.615 5.525 ;
        RECT 2.905 5.355 3.075 5.525 ;
        RECT 3.365 5.355 3.535 5.525 ;
        RECT 3.825 5.355 3.995 5.525 ;
        RECT 4.285 5.355 4.455 5.525 ;
        RECT 4.745 5.355 4.915 5.525 ;
        RECT 5.205 5.355 5.375 5.525 ;
        RECT 5.665 5.355 5.835 5.525 ;
        RECT 6.125 5.355 6.295 5.525 ;
        RECT 6.585 5.355 6.755 5.525 ;
        RECT 7.045 5.355 7.215 5.525 ;
        RECT 7.505 5.355 7.675 5.525 ;
        RECT 7.965 5.355 8.135 5.525 ;
        RECT 8.425 5.355 8.595 5.525 ;
        RECT 8.885 5.355 9.055 5.525 ;
        RECT 9.345 5.355 9.515 5.525 ;
        RECT 9.805 5.355 9.975 5.525 ;
        RECT 10.265 5.355 10.435 5.525 ;
        RECT 10.725 5.355 10.895 5.525 ;
        RECT 11.185 5.355 11.355 5.525 ;
        RECT 11.645 5.355 11.815 5.525 ;
        RECT 12.105 5.355 12.275 5.525 ;
        RECT 12.565 5.355 12.735 5.525 ;
        RECT 13.025 5.355 13.195 5.525 ;
        RECT 13.485 5.355 13.655 5.525 ;
        RECT 13.945 5.355 14.115 5.525 ;
        RECT 14.405 5.355 14.575 5.525 ;
        RECT 14.865 5.355 15.035 5.525 ;
        RECT 15.325 5.355 15.495 5.525 ;
        RECT 15.785 5.355 15.955 5.525 ;
        RECT 16.245 5.355 16.415 5.525 ;
        RECT 16.705 5.355 16.875 5.525 ;
        RECT 17.165 5.355 17.335 5.525 ;
        RECT 17.625 5.355 17.795 5.525 ;
        RECT 18.085 5.355 18.255 5.525 ;
        RECT 18.545 5.355 18.715 5.525 ;
        RECT 19.005 5.355 19.175 5.525 ;
        RECT 19.465 5.355 19.635 5.525 ;
        RECT 19.925 5.355 20.095 5.525 ;
        RECT 20.385 5.355 20.555 5.525 ;
        RECT 20.845 5.355 21.015 5.525 ;
        RECT 21.305 5.355 21.475 5.525 ;
        RECT 21.765 5.355 21.935 5.525 ;
        RECT 22.225 5.355 22.395 5.525 ;
        RECT 22.685 5.355 22.855 5.525 ;
        RECT 23.145 5.355 23.315 5.525 ;
        RECT 23.605 5.355 23.775 5.525 ;
        RECT 24.065 5.355 24.235 5.525 ;
        RECT 24.525 5.355 24.695 5.525 ;
        RECT 24.985 5.355 25.155 5.525 ;
        RECT 25.445 5.355 25.615 5.525 ;
        RECT 25.905 5.355 26.075 5.525 ;
        RECT 26.365 5.355 26.535 5.525 ;
        RECT 26.825 5.355 26.995 5.525 ;
        RECT 27.285 5.355 27.455 5.525 ;
        RECT 27.745 5.355 27.915 5.525 ;
        RECT 28.205 5.355 28.375 5.525 ;
        RECT 28.665 5.355 28.835 5.525 ;
        RECT 29.125 5.355 29.295 5.525 ;
        RECT 29.585 5.355 29.755 5.525 ;
        RECT 30.045 5.355 30.215 5.525 ;
        RECT 30.505 5.355 30.675 5.525 ;
        RECT 30.965 5.355 31.135 5.525 ;
        RECT 31.425 5.355 31.595 5.525 ;
        RECT 31.885 5.355 32.055 5.525 ;
        RECT 32.345 5.355 32.515 5.525 ;
        RECT 32.805 5.355 32.975 5.525 ;
        RECT 33.265 5.355 33.435 5.525 ;
        RECT 33.725 5.355 33.895 5.525 ;
        RECT 34.185 5.355 34.355 5.525 ;
        RECT 34.645 5.355 34.815 5.525 ;
        RECT 35.105 5.355 35.275 5.525 ;
        RECT 35.565 5.355 35.735 5.525 ;
        RECT 36.025 5.355 36.195 5.525 ;
        RECT 36.485 5.355 36.655 5.525 ;
        RECT 36.945 5.355 37.115 5.525 ;
        RECT 37.405 5.355 37.575 5.525 ;
        RECT 37.865 5.355 38.035 5.525 ;
        RECT 38.325 5.355 38.495 5.525 ;
      LAYER met1 ;
        RECT -10.620 37.840 50.640 38.320 ;
        RECT -10.620 32.400 50.640 32.880 ;
        RECT -10.620 26.960 50.640 27.440 ;
        RECT -10.620 21.520 50.640 22.000 ;
        RECT -10.620 16.080 50.640 16.560 ;
        RECT -10.620 10.640 50.640 11.120 ;
        RECT -10.620 5.200 50.640 5.680 ;
      LAYER via ;
        RECT -4.770 37.950 -4.510 38.210 ;
        RECT -4.450 37.950 -4.190 38.210 ;
        RECT -4.130 37.950 -3.870 38.210 ;
        RECT -3.810 37.950 -3.550 38.210 ;
        RECT -3.490 37.950 -3.230 38.210 ;
        RECT -3.170 37.950 -2.910 38.210 ;
        RECT -2.850 37.950 -2.590 38.210 ;
        RECT -2.530 37.950 -2.270 38.210 ;
        RECT -2.210 37.950 -1.950 38.210 ;
        RECT -1.890 37.950 -1.630 38.210 ;
        RECT -1.570 37.950 -1.310 38.210 ;
        RECT -1.250 37.950 -0.990 38.210 ;
        RECT -0.930 37.950 -0.670 38.210 ;
        RECT 14.180 37.950 14.440 38.210 ;
        RECT 14.500 37.950 14.760 38.210 ;
        RECT 14.820 37.950 15.080 38.210 ;
        RECT 15.140 37.950 15.400 38.210 ;
        RECT 15.460 37.950 15.720 38.210 ;
        RECT 40.690 37.950 40.950 38.210 ;
        RECT 41.010 37.950 41.270 38.210 ;
        RECT 41.330 37.950 41.590 38.210 ;
        RECT 41.650 37.950 41.910 38.210 ;
        RECT 41.970 37.950 42.230 38.210 ;
        RECT 42.290 37.950 42.550 38.210 ;
        RECT 42.610 37.950 42.870 38.210 ;
        RECT 42.930 37.950 43.190 38.210 ;
        RECT 43.250 37.950 43.510 38.210 ;
        RECT 43.570 37.950 43.830 38.210 ;
        RECT 43.890 37.950 44.150 38.210 ;
        RECT 44.210 37.950 44.470 38.210 ;
        RECT 44.530 37.950 44.790 38.210 ;
        RECT -4.770 32.510 -4.510 32.770 ;
        RECT -4.450 32.510 -4.190 32.770 ;
        RECT -4.130 32.510 -3.870 32.770 ;
        RECT -3.810 32.510 -3.550 32.770 ;
        RECT -3.490 32.510 -3.230 32.770 ;
        RECT -3.170 32.510 -2.910 32.770 ;
        RECT -2.850 32.510 -2.590 32.770 ;
        RECT -2.530 32.510 -2.270 32.770 ;
        RECT -2.210 32.510 -1.950 32.770 ;
        RECT -1.890 32.510 -1.630 32.770 ;
        RECT -1.570 32.510 -1.310 32.770 ;
        RECT -1.250 32.510 -0.990 32.770 ;
        RECT -0.930 32.510 -0.670 32.770 ;
        RECT 14.180 32.510 14.440 32.770 ;
        RECT 14.500 32.510 14.760 32.770 ;
        RECT 14.820 32.510 15.080 32.770 ;
        RECT 15.140 32.510 15.400 32.770 ;
        RECT 15.460 32.510 15.720 32.770 ;
        RECT 40.690 32.510 40.950 32.770 ;
        RECT 41.010 32.510 41.270 32.770 ;
        RECT 41.330 32.510 41.590 32.770 ;
        RECT 41.650 32.510 41.910 32.770 ;
        RECT 41.970 32.510 42.230 32.770 ;
        RECT 42.290 32.510 42.550 32.770 ;
        RECT 42.610 32.510 42.870 32.770 ;
        RECT 42.930 32.510 43.190 32.770 ;
        RECT 43.250 32.510 43.510 32.770 ;
        RECT 43.570 32.510 43.830 32.770 ;
        RECT 43.890 32.510 44.150 32.770 ;
        RECT 44.210 32.510 44.470 32.770 ;
        RECT 44.530 32.510 44.790 32.770 ;
        RECT -4.770 27.070 -4.510 27.330 ;
        RECT -4.450 27.070 -4.190 27.330 ;
        RECT -4.130 27.070 -3.870 27.330 ;
        RECT -3.810 27.070 -3.550 27.330 ;
        RECT -3.490 27.070 -3.230 27.330 ;
        RECT -3.170 27.070 -2.910 27.330 ;
        RECT -2.850 27.070 -2.590 27.330 ;
        RECT -2.530 27.070 -2.270 27.330 ;
        RECT -2.210 27.070 -1.950 27.330 ;
        RECT -1.890 27.070 -1.630 27.330 ;
        RECT -1.570 27.070 -1.310 27.330 ;
        RECT -1.250 27.070 -0.990 27.330 ;
        RECT -0.930 27.070 -0.670 27.330 ;
        RECT 14.180 27.070 14.440 27.330 ;
        RECT 14.500 27.070 14.760 27.330 ;
        RECT 14.820 27.070 15.080 27.330 ;
        RECT 15.140 27.070 15.400 27.330 ;
        RECT 15.460 27.070 15.720 27.330 ;
        RECT 40.690 27.070 40.950 27.330 ;
        RECT 41.010 27.070 41.270 27.330 ;
        RECT 41.330 27.070 41.590 27.330 ;
        RECT 41.650 27.070 41.910 27.330 ;
        RECT 41.970 27.070 42.230 27.330 ;
        RECT 42.290 27.070 42.550 27.330 ;
        RECT 42.610 27.070 42.870 27.330 ;
        RECT 42.930 27.070 43.190 27.330 ;
        RECT 43.250 27.070 43.510 27.330 ;
        RECT 43.570 27.070 43.830 27.330 ;
        RECT 43.890 27.070 44.150 27.330 ;
        RECT 44.210 27.070 44.470 27.330 ;
        RECT 44.530 27.070 44.790 27.330 ;
        RECT -4.770 21.630 -4.510 21.890 ;
        RECT -4.450 21.630 -4.190 21.890 ;
        RECT -4.130 21.630 -3.870 21.890 ;
        RECT -3.810 21.630 -3.550 21.890 ;
        RECT -3.490 21.630 -3.230 21.890 ;
        RECT -3.170 21.630 -2.910 21.890 ;
        RECT -2.850 21.630 -2.590 21.890 ;
        RECT -2.530 21.630 -2.270 21.890 ;
        RECT -2.210 21.630 -1.950 21.890 ;
        RECT -1.890 21.630 -1.630 21.890 ;
        RECT -1.570 21.630 -1.310 21.890 ;
        RECT -1.250 21.630 -0.990 21.890 ;
        RECT -0.930 21.630 -0.670 21.890 ;
        RECT 14.180 21.630 14.440 21.890 ;
        RECT 14.500 21.630 14.760 21.890 ;
        RECT 14.820 21.630 15.080 21.890 ;
        RECT 15.140 21.630 15.400 21.890 ;
        RECT 15.460 21.630 15.720 21.890 ;
        RECT 40.690 21.630 40.950 21.890 ;
        RECT 41.010 21.630 41.270 21.890 ;
        RECT 41.330 21.630 41.590 21.890 ;
        RECT 41.650 21.630 41.910 21.890 ;
        RECT 41.970 21.630 42.230 21.890 ;
        RECT 42.290 21.630 42.550 21.890 ;
        RECT 42.610 21.630 42.870 21.890 ;
        RECT 42.930 21.630 43.190 21.890 ;
        RECT 43.250 21.630 43.510 21.890 ;
        RECT 43.570 21.630 43.830 21.890 ;
        RECT 43.890 21.630 44.150 21.890 ;
        RECT 44.210 21.630 44.470 21.890 ;
        RECT 44.530 21.630 44.790 21.890 ;
        RECT -4.770 16.190 -4.510 16.450 ;
        RECT -4.450 16.190 -4.190 16.450 ;
        RECT -4.130 16.190 -3.870 16.450 ;
        RECT -3.810 16.190 -3.550 16.450 ;
        RECT -3.490 16.190 -3.230 16.450 ;
        RECT -3.170 16.190 -2.910 16.450 ;
        RECT -2.850 16.190 -2.590 16.450 ;
        RECT -2.530 16.190 -2.270 16.450 ;
        RECT -2.210 16.190 -1.950 16.450 ;
        RECT -1.890 16.190 -1.630 16.450 ;
        RECT -1.570 16.190 -1.310 16.450 ;
        RECT -1.250 16.190 -0.990 16.450 ;
        RECT -0.930 16.190 -0.670 16.450 ;
        RECT 14.180 16.190 14.440 16.450 ;
        RECT 14.500 16.190 14.760 16.450 ;
        RECT 14.820 16.190 15.080 16.450 ;
        RECT 15.140 16.190 15.400 16.450 ;
        RECT 15.460 16.190 15.720 16.450 ;
        RECT 40.690 16.190 40.950 16.450 ;
        RECT 41.010 16.190 41.270 16.450 ;
        RECT 41.330 16.190 41.590 16.450 ;
        RECT 41.650 16.190 41.910 16.450 ;
        RECT 41.970 16.190 42.230 16.450 ;
        RECT 42.290 16.190 42.550 16.450 ;
        RECT 42.610 16.190 42.870 16.450 ;
        RECT 42.930 16.190 43.190 16.450 ;
        RECT 43.250 16.190 43.510 16.450 ;
        RECT 43.570 16.190 43.830 16.450 ;
        RECT 43.890 16.190 44.150 16.450 ;
        RECT 44.210 16.190 44.470 16.450 ;
        RECT 44.530 16.190 44.790 16.450 ;
        RECT -4.770 10.750 -4.510 11.010 ;
        RECT -4.450 10.750 -4.190 11.010 ;
        RECT -4.130 10.750 -3.870 11.010 ;
        RECT -3.810 10.750 -3.550 11.010 ;
        RECT -3.490 10.750 -3.230 11.010 ;
        RECT -3.170 10.750 -2.910 11.010 ;
        RECT -2.850 10.750 -2.590 11.010 ;
        RECT -2.530 10.750 -2.270 11.010 ;
        RECT -2.210 10.750 -1.950 11.010 ;
        RECT -1.890 10.750 -1.630 11.010 ;
        RECT -1.570 10.750 -1.310 11.010 ;
        RECT -1.250 10.750 -0.990 11.010 ;
        RECT -0.930 10.750 -0.670 11.010 ;
        RECT 14.180 10.750 14.440 11.010 ;
        RECT 14.500 10.750 14.760 11.010 ;
        RECT 14.820 10.750 15.080 11.010 ;
        RECT 15.140 10.750 15.400 11.010 ;
        RECT 15.460 10.750 15.720 11.010 ;
        RECT 40.690 10.750 40.950 11.010 ;
        RECT 41.010 10.750 41.270 11.010 ;
        RECT 41.330 10.750 41.590 11.010 ;
        RECT 41.650 10.750 41.910 11.010 ;
        RECT 41.970 10.750 42.230 11.010 ;
        RECT 42.290 10.750 42.550 11.010 ;
        RECT 42.610 10.750 42.870 11.010 ;
        RECT 42.930 10.750 43.190 11.010 ;
        RECT 43.250 10.750 43.510 11.010 ;
        RECT 43.570 10.750 43.830 11.010 ;
        RECT 43.890 10.750 44.150 11.010 ;
        RECT 44.210 10.750 44.470 11.010 ;
        RECT 44.530 10.750 44.790 11.010 ;
        RECT -4.770 5.310 -4.510 5.570 ;
        RECT -4.450 5.310 -4.190 5.570 ;
        RECT -4.130 5.310 -3.870 5.570 ;
        RECT -3.810 5.310 -3.550 5.570 ;
        RECT -3.490 5.310 -3.230 5.570 ;
        RECT -3.170 5.310 -2.910 5.570 ;
        RECT -2.850 5.310 -2.590 5.570 ;
        RECT -2.530 5.310 -2.270 5.570 ;
        RECT -2.210 5.310 -1.950 5.570 ;
        RECT -1.890 5.310 -1.630 5.570 ;
        RECT -1.570 5.310 -1.310 5.570 ;
        RECT -1.250 5.310 -0.990 5.570 ;
        RECT -0.930 5.310 -0.670 5.570 ;
        RECT 14.180 5.310 14.440 5.570 ;
        RECT 14.500 5.310 14.760 5.570 ;
        RECT 14.820 5.310 15.080 5.570 ;
        RECT 15.140 5.310 15.400 5.570 ;
        RECT 15.460 5.310 15.720 5.570 ;
        RECT 40.690 5.310 40.950 5.570 ;
        RECT 41.010 5.310 41.270 5.570 ;
        RECT 41.330 5.310 41.590 5.570 ;
        RECT 41.650 5.310 41.910 5.570 ;
        RECT 41.970 5.310 42.230 5.570 ;
        RECT 42.290 5.310 42.550 5.570 ;
        RECT 42.610 5.310 42.870 5.570 ;
        RECT 42.930 5.310 43.190 5.570 ;
        RECT 43.250 5.310 43.510 5.570 ;
        RECT 43.570 5.310 43.830 5.570 ;
        RECT 43.890 5.310 44.150 5.570 ;
        RECT 44.210 5.310 44.470 5.570 ;
        RECT 44.530 5.310 44.790 5.570 ;
      LAYER met2 ;
        RECT -4.770 37.840 -0.670 38.320 ;
        RECT 14.180 37.840 15.720 38.320 ;
        RECT 40.690 37.840 44.790 38.320 ;
        RECT -4.770 32.400 -0.670 32.880 ;
        RECT 14.180 32.400 15.720 32.880 ;
        RECT 40.690 32.400 44.790 32.880 ;
        RECT -4.770 26.960 -0.670 27.440 ;
        RECT 14.180 26.960 15.720 27.440 ;
        RECT 40.690 26.960 44.790 27.440 ;
        RECT -4.770 21.520 -0.670 22.000 ;
        RECT 14.180 21.520 15.720 22.000 ;
        RECT 40.690 21.520 44.790 22.000 ;
        RECT -4.770 16.080 -0.670 16.560 ;
        RECT 14.180 16.080 15.720 16.560 ;
        RECT 40.690 16.080 44.790 16.560 ;
        RECT -4.770 10.640 -0.670 11.120 ;
        RECT 14.180 10.640 15.720 11.120 ;
        RECT 40.690 10.640 44.790 11.120 ;
        RECT -4.770 5.200 -0.670 5.680 ;
        RECT 14.180 5.200 15.720 5.680 ;
        RECT 40.690 5.200 44.790 5.680 ;
      LAYER via2 ;
        RECT -4.660 37.940 -4.380 38.220 ;
        RECT -4.260 37.940 -3.980 38.220 ;
        RECT -3.860 37.940 -3.580 38.220 ;
        RECT -3.460 37.940 -3.180 38.220 ;
        RECT -3.060 37.940 -2.780 38.220 ;
        RECT -2.660 37.940 -2.380 38.220 ;
        RECT -2.260 37.940 -1.980 38.220 ;
        RECT -1.860 37.940 -1.580 38.220 ;
        RECT -1.460 37.940 -1.180 38.220 ;
        RECT -1.060 37.940 -0.780 38.220 ;
        RECT 14.210 37.940 14.490 38.220 ;
        RECT 14.610 37.940 14.890 38.220 ;
        RECT 15.010 37.940 15.290 38.220 ;
        RECT 15.410 37.940 15.690 38.220 ;
        RECT 40.800 37.940 41.080 38.220 ;
        RECT 41.200 37.940 41.480 38.220 ;
        RECT 41.600 37.940 41.880 38.220 ;
        RECT 42.000 37.940 42.280 38.220 ;
        RECT 42.400 37.940 42.680 38.220 ;
        RECT 42.800 37.940 43.080 38.220 ;
        RECT 43.200 37.940 43.480 38.220 ;
        RECT 43.600 37.940 43.880 38.220 ;
        RECT 44.000 37.940 44.280 38.220 ;
        RECT 44.400 37.940 44.680 38.220 ;
        RECT -4.660 32.500 -4.380 32.780 ;
        RECT -4.260 32.500 -3.980 32.780 ;
        RECT -3.860 32.500 -3.580 32.780 ;
        RECT -3.460 32.500 -3.180 32.780 ;
        RECT -3.060 32.500 -2.780 32.780 ;
        RECT -2.660 32.500 -2.380 32.780 ;
        RECT -2.260 32.500 -1.980 32.780 ;
        RECT -1.860 32.500 -1.580 32.780 ;
        RECT -1.460 32.500 -1.180 32.780 ;
        RECT -1.060 32.500 -0.780 32.780 ;
        RECT 14.210 32.500 14.490 32.780 ;
        RECT 14.610 32.500 14.890 32.780 ;
        RECT 15.010 32.500 15.290 32.780 ;
        RECT 15.410 32.500 15.690 32.780 ;
        RECT 40.800 32.500 41.080 32.780 ;
        RECT 41.200 32.500 41.480 32.780 ;
        RECT 41.600 32.500 41.880 32.780 ;
        RECT 42.000 32.500 42.280 32.780 ;
        RECT 42.400 32.500 42.680 32.780 ;
        RECT 42.800 32.500 43.080 32.780 ;
        RECT 43.200 32.500 43.480 32.780 ;
        RECT 43.600 32.500 43.880 32.780 ;
        RECT 44.000 32.500 44.280 32.780 ;
        RECT 44.400 32.500 44.680 32.780 ;
        RECT -4.660 27.060 -4.380 27.340 ;
        RECT -4.260 27.060 -3.980 27.340 ;
        RECT -3.860 27.060 -3.580 27.340 ;
        RECT -3.460 27.060 -3.180 27.340 ;
        RECT -3.060 27.060 -2.780 27.340 ;
        RECT -2.660 27.060 -2.380 27.340 ;
        RECT -2.260 27.060 -1.980 27.340 ;
        RECT -1.860 27.060 -1.580 27.340 ;
        RECT -1.460 27.060 -1.180 27.340 ;
        RECT -1.060 27.060 -0.780 27.340 ;
        RECT 14.210 27.060 14.490 27.340 ;
        RECT 14.610 27.060 14.890 27.340 ;
        RECT 15.010 27.060 15.290 27.340 ;
        RECT 15.410 27.060 15.690 27.340 ;
        RECT 40.800 27.060 41.080 27.340 ;
        RECT 41.200 27.060 41.480 27.340 ;
        RECT 41.600 27.060 41.880 27.340 ;
        RECT 42.000 27.060 42.280 27.340 ;
        RECT 42.400 27.060 42.680 27.340 ;
        RECT 42.800 27.060 43.080 27.340 ;
        RECT 43.200 27.060 43.480 27.340 ;
        RECT 43.600 27.060 43.880 27.340 ;
        RECT 44.000 27.060 44.280 27.340 ;
        RECT 44.400 27.060 44.680 27.340 ;
        RECT -4.660 21.620 -4.380 21.900 ;
        RECT -4.260 21.620 -3.980 21.900 ;
        RECT -3.860 21.620 -3.580 21.900 ;
        RECT -3.460 21.620 -3.180 21.900 ;
        RECT -3.060 21.620 -2.780 21.900 ;
        RECT -2.660 21.620 -2.380 21.900 ;
        RECT -2.260 21.620 -1.980 21.900 ;
        RECT -1.860 21.620 -1.580 21.900 ;
        RECT -1.460 21.620 -1.180 21.900 ;
        RECT -1.060 21.620 -0.780 21.900 ;
        RECT 14.210 21.620 14.490 21.900 ;
        RECT 14.610 21.620 14.890 21.900 ;
        RECT 15.010 21.620 15.290 21.900 ;
        RECT 15.410 21.620 15.690 21.900 ;
        RECT 40.800 21.620 41.080 21.900 ;
        RECT 41.200 21.620 41.480 21.900 ;
        RECT 41.600 21.620 41.880 21.900 ;
        RECT 42.000 21.620 42.280 21.900 ;
        RECT 42.400 21.620 42.680 21.900 ;
        RECT 42.800 21.620 43.080 21.900 ;
        RECT 43.200 21.620 43.480 21.900 ;
        RECT 43.600 21.620 43.880 21.900 ;
        RECT 44.000 21.620 44.280 21.900 ;
        RECT 44.400 21.620 44.680 21.900 ;
        RECT -4.660 16.180 -4.380 16.460 ;
        RECT -4.260 16.180 -3.980 16.460 ;
        RECT -3.860 16.180 -3.580 16.460 ;
        RECT -3.460 16.180 -3.180 16.460 ;
        RECT -3.060 16.180 -2.780 16.460 ;
        RECT -2.660 16.180 -2.380 16.460 ;
        RECT -2.260 16.180 -1.980 16.460 ;
        RECT -1.860 16.180 -1.580 16.460 ;
        RECT -1.460 16.180 -1.180 16.460 ;
        RECT -1.060 16.180 -0.780 16.460 ;
        RECT 14.210 16.180 14.490 16.460 ;
        RECT 14.610 16.180 14.890 16.460 ;
        RECT 15.010 16.180 15.290 16.460 ;
        RECT 15.410 16.180 15.690 16.460 ;
        RECT 40.800 16.180 41.080 16.460 ;
        RECT 41.200 16.180 41.480 16.460 ;
        RECT 41.600 16.180 41.880 16.460 ;
        RECT 42.000 16.180 42.280 16.460 ;
        RECT 42.400 16.180 42.680 16.460 ;
        RECT 42.800 16.180 43.080 16.460 ;
        RECT 43.200 16.180 43.480 16.460 ;
        RECT 43.600 16.180 43.880 16.460 ;
        RECT 44.000 16.180 44.280 16.460 ;
        RECT 44.400 16.180 44.680 16.460 ;
        RECT -4.660 10.740 -4.380 11.020 ;
        RECT -4.260 10.740 -3.980 11.020 ;
        RECT -3.860 10.740 -3.580 11.020 ;
        RECT -3.460 10.740 -3.180 11.020 ;
        RECT -3.060 10.740 -2.780 11.020 ;
        RECT -2.660 10.740 -2.380 11.020 ;
        RECT -2.260 10.740 -1.980 11.020 ;
        RECT -1.860 10.740 -1.580 11.020 ;
        RECT -1.460 10.740 -1.180 11.020 ;
        RECT -1.060 10.740 -0.780 11.020 ;
        RECT 14.210 10.740 14.490 11.020 ;
        RECT 14.610 10.740 14.890 11.020 ;
        RECT 15.010 10.740 15.290 11.020 ;
        RECT 15.410 10.740 15.690 11.020 ;
        RECT 40.800 10.740 41.080 11.020 ;
        RECT 41.200 10.740 41.480 11.020 ;
        RECT 41.600 10.740 41.880 11.020 ;
        RECT 42.000 10.740 42.280 11.020 ;
        RECT 42.400 10.740 42.680 11.020 ;
        RECT 42.800 10.740 43.080 11.020 ;
        RECT 43.200 10.740 43.480 11.020 ;
        RECT 43.600 10.740 43.880 11.020 ;
        RECT 44.000 10.740 44.280 11.020 ;
        RECT 44.400 10.740 44.680 11.020 ;
        RECT -4.660 5.300 -4.380 5.580 ;
        RECT -4.260 5.300 -3.980 5.580 ;
        RECT -3.860 5.300 -3.580 5.580 ;
        RECT -3.460 5.300 -3.180 5.580 ;
        RECT -3.060 5.300 -2.780 5.580 ;
        RECT -2.660 5.300 -2.380 5.580 ;
        RECT -2.260 5.300 -1.980 5.580 ;
        RECT -1.860 5.300 -1.580 5.580 ;
        RECT -1.460 5.300 -1.180 5.580 ;
        RECT -1.060 5.300 -0.780 5.580 ;
        RECT 14.210 5.300 14.490 5.580 ;
        RECT 14.610 5.300 14.890 5.580 ;
        RECT 15.010 5.300 15.290 5.580 ;
        RECT 15.410 5.300 15.690 5.580 ;
        RECT 40.800 5.300 41.080 5.580 ;
        RECT 41.200 5.300 41.480 5.580 ;
        RECT 41.600 5.300 41.880 5.580 ;
        RECT 42.000 5.300 42.280 5.580 ;
        RECT 42.400 5.300 42.680 5.580 ;
        RECT 42.800 5.300 43.080 5.580 ;
        RECT 43.200 5.300 43.480 5.580 ;
        RECT 43.600 5.300 43.880 5.580 ;
        RECT 44.000 5.300 44.280 5.580 ;
        RECT 44.400 5.300 44.680 5.580 ;
      LAYER met3 ;
        RECT -4.820 37.915 -0.620 38.245 ;
        RECT 14.150 37.915 15.750 38.245 ;
        RECT 40.640 37.915 44.840 38.245 ;
        RECT -4.820 32.475 -0.620 32.805 ;
        RECT 14.150 32.475 15.750 32.805 ;
        RECT 40.640 32.475 44.840 32.805 ;
        RECT -4.820 27.035 -0.620 27.365 ;
        RECT 14.150 27.035 15.750 27.365 ;
        RECT 40.640 27.035 44.840 27.365 ;
        RECT -4.820 21.595 -0.620 21.925 ;
        RECT 14.150 21.595 15.750 21.925 ;
        RECT 40.640 21.595 44.840 21.925 ;
        RECT -4.820 16.155 -0.620 16.485 ;
        RECT 14.150 16.155 15.750 16.485 ;
        RECT 40.640 16.155 44.840 16.485 ;
        RECT -4.820 10.715 -0.620 11.045 ;
        RECT 14.150 10.715 15.750 11.045 ;
        RECT 40.640 10.715 44.840 11.045 ;
        RECT -4.820 5.275 -0.620 5.605 ;
        RECT 14.150 5.275 15.750 5.605 ;
        RECT 40.640 5.275 44.840 5.605 ;
      LAYER via3 ;
        RECT -4.680 37.920 -4.360 38.240 ;
        RECT -4.280 37.920 -3.960 38.240 ;
        RECT -3.880 37.920 -3.560 38.240 ;
        RECT -3.480 37.920 -3.160 38.240 ;
        RECT -3.080 37.920 -2.760 38.240 ;
        RECT -2.680 37.920 -2.360 38.240 ;
        RECT -2.280 37.920 -1.960 38.240 ;
        RECT -1.880 37.920 -1.560 38.240 ;
        RECT -1.480 37.920 -1.160 38.240 ;
        RECT -1.080 37.920 -0.760 38.240 ;
        RECT 14.190 37.920 14.510 38.240 ;
        RECT 14.590 37.920 14.910 38.240 ;
        RECT 14.990 37.920 15.310 38.240 ;
        RECT 15.390 37.920 15.710 38.240 ;
        RECT 40.780 37.920 41.100 38.240 ;
        RECT 41.180 37.920 41.500 38.240 ;
        RECT 41.580 37.920 41.900 38.240 ;
        RECT 41.980 37.920 42.300 38.240 ;
        RECT 42.380 37.920 42.700 38.240 ;
        RECT 42.780 37.920 43.100 38.240 ;
        RECT 43.180 37.920 43.500 38.240 ;
        RECT 43.580 37.920 43.900 38.240 ;
        RECT 43.980 37.920 44.300 38.240 ;
        RECT 44.380 37.920 44.700 38.240 ;
        RECT -4.680 32.480 -4.360 32.800 ;
        RECT -4.280 32.480 -3.960 32.800 ;
        RECT -3.880 32.480 -3.560 32.800 ;
        RECT -3.480 32.480 -3.160 32.800 ;
        RECT -3.080 32.480 -2.760 32.800 ;
        RECT -2.680 32.480 -2.360 32.800 ;
        RECT -2.280 32.480 -1.960 32.800 ;
        RECT -1.880 32.480 -1.560 32.800 ;
        RECT -1.480 32.480 -1.160 32.800 ;
        RECT -1.080 32.480 -0.760 32.800 ;
        RECT 14.190 32.480 14.510 32.800 ;
        RECT 14.590 32.480 14.910 32.800 ;
        RECT 14.990 32.480 15.310 32.800 ;
        RECT 15.390 32.480 15.710 32.800 ;
        RECT 40.780 32.480 41.100 32.800 ;
        RECT 41.180 32.480 41.500 32.800 ;
        RECT 41.580 32.480 41.900 32.800 ;
        RECT 41.980 32.480 42.300 32.800 ;
        RECT 42.380 32.480 42.700 32.800 ;
        RECT 42.780 32.480 43.100 32.800 ;
        RECT 43.180 32.480 43.500 32.800 ;
        RECT 43.580 32.480 43.900 32.800 ;
        RECT 43.980 32.480 44.300 32.800 ;
        RECT 44.380 32.480 44.700 32.800 ;
        RECT -4.680 27.040 -4.360 27.360 ;
        RECT -4.280 27.040 -3.960 27.360 ;
        RECT -3.880 27.040 -3.560 27.360 ;
        RECT -3.480 27.040 -3.160 27.360 ;
        RECT -3.080 27.040 -2.760 27.360 ;
        RECT -2.680 27.040 -2.360 27.360 ;
        RECT -2.280 27.040 -1.960 27.360 ;
        RECT -1.880 27.040 -1.560 27.360 ;
        RECT -1.480 27.040 -1.160 27.360 ;
        RECT -1.080 27.040 -0.760 27.360 ;
        RECT 14.190 27.040 14.510 27.360 ;
        RECT 14.590 27.040 14.910 27.360 ;
        RECT 14.990 27.040 15.310 27.360 ;
        RECT 15.390 27.040 15.710 27.360 ;
        RECT 40.780 27.040 41.100 27.360 ;
        RECT 41.180 27.040 41.500 27.360 ;
        RECT 41.580 27.040 41.900 27.360 ;
        RECT 41.980 27.040 42.300 27.360 ;
        RECT 42.380 27.040 42.700 27.360 ;
        RECT 42.780 27.040 43.100 27.360 ;
        RECT 43.180 27.040 43.500 27.360 ;
        RECT 43.580 27.040 43.900 27.360 ;
        RECT 43.980 27.040 44.300 27.360 ;
        RECT 44.380 27.040 44.700 27.360 ;
        RECT -4.680 21.600 -4.360 21.920 ;
        RECT -4.280 21.600 -3.960 21.920 ;
        RECT -3.880 21.600 -3.560 21.920 ;
        RECT -3.480 21.600 -3.160 21.920 ;
        RECT -3.080 21.600 -2.760 21.920 ;
        RECT -2.680 21.600 -2.360 21.920 ;
        RECT -2.280 21.600 -1.960 21.920 ;
        RECT -1.880 21.600 -1.560 21.920 ;
        RECT -1.480 21.600 -1.160 21.920 ;
        RECT -1.080 21.600 -0.760 21.920 ;
        RECT 14.190 21.600 14.510 21.920 ;
        RECT 14.590 21.600 14.910 21.920 ;
        RECT 14.990 21.600 15.310 21.920 ;
        RECT 15.390 21.600 15.710 21.920 ;
        RECT 40.780 21.600 41.100 21.920 ;
        RECT 41.180 21.600 41.500 21.920 ;
        RECT 41.580 21.600 41.900 21.920 ;
        RECT 41.980 21.600 42.300 21.920 ;
        RECT 42.380 21.600 42.700 21.920 ;
        RECT 42.780 21.600 43.100 21.920 ;
        RECT 43.180 21.600 43.500 21.920 ;
        RECT 43.580 21.600 43.900 21.920 ;
        RECT 43.980 21.600 44.300 21.920 ;
        RECT 44.380 21.600 44.700 21.920 ;
        RECT -4.680 16.160 -4.360 16.480 ;
        RECT -4.280 16.160 -3.960 16.480 ;
        RECT -3.880 16.160 -3.560 16.480 ;
        RECT -3.480 16.160 -3.160 16.480 ;
        RECT -3.080 16.160 -2.760 16.480 ;
        RECT -2.680 16.160 -2.360 16.480 ;
        RECT -2.280 16.160 -1.960 16.480 ;
        RECT -1.880 16.160 -1.560 16.480 ;
        RECT -1.480 16.160 -1.160 16.480 ;
        RECT -1.080 16.160 -0.760 16.480 ;
        RECT 14.190 16.160 14.510 16.480 ;
        RECT 14.590 16.160 14.910 16.480 ;
        RECT 14.990 16.160 15.310 16.480 ;
        RECT 15.390 16.160 15.710 16.480 ;
        RECT 40.780 16.160 41.100 16.480 ;
        RECT 41.180 16.160 41.500 16.480 ;
        RECT 41.580 16.160 41.900 16.480 ;
        RECT 41.980 16.160 42.300 16.480 ;
        RECT 42.380 16.160 42.700 16.480 ;
        RECT 42.780 16.160 43.100 16.480 ;
        RECT 43.180 16.160 43.500 16.480 ;
        RECT 43.580 16.160 43.900 16.480 ;
        RECT 43.980 16.160 44.300 16.480 ;
        RECT 44.380 16.160 44.700 16.480 ;
        RECT -4.680 10.720 -4.360 11.040 ;
        RECT -4.280 10.720 -3.960 11.040 ;
        RECT -3.880 10.720 -3.560 11.040 ;
        RECT -3.480 10.720 -3.160 11.040 ;
        RECT -3.080 10.720 -2.760 11.040 ;
        RECT -2.680 10.720 -2.360 11.040 ;
        RECT -2.280 10.720 -1.960 11.040 ;
        RECT -1.880 10.720 -1.560 11.040 ;
        RECT -1.480 10.720 -1.160 11.040 ;
        RECT -1.080 10.720 -0.760 11.040 ;
        RECT 14.190 10.720 14.510 11.040 ;
        RECT 14.590 10.720 14.910 11.040 ;
        RECT 14.990 10.720 15.310 11.040 ;
        RECT 15.390 10.720 15.710 11.040 ;
        RECT 40.780 10.720 41.100 11.040 ;
        RECT 41.180 10.720 41.500 11.040 ;
        RECT 41.580 10.720 41.900 11.040 ;
        RECT 41.980 10.720 42.300 11.040 ;
        RECT 42.380 10.720 42.700 11.040 ;
        RECT 42.780 10.720 43.100 11.040 ;
        RECT 43.180 10.720 43.500 11.040 ;
        RECT 43.580 10.720 43.900 11.040 ;
        RECT 43.980 10.720 44.300 11.040 ;
        RECT 44.380 10.720 44.700 11.040 ;
        RECT -4.680 5.280 -4.360 5.600 ;
        RECT -4.280 5.280 -3.960 5.600 ;
        RECT -3.880 5.280 -3.560 5.600 ;
        RECT -3.480 5.280 -3.160 5.600 ;
        RECT -3.080 5.280 -2.760 5.600 ;
        RECT -2.680 5.280 -2.360 5.600 ;
        RECT -2.280 5.280 -1.960 5.600 ;
        RECT -1.880 5.280 -1.560 5.600 ;
        RECT -1.480 5.280 -1.160 5.600 ;
        RECT -1.080 5.280 -0.760 5.600 ;
        RECT 14.190 5.280 14.510 5.600 ;
        RECT 14.590 5.280 14.910 5.600 ;
        RECT 14.990 5.280 15.310 5.600 ;
        RECT 15.390 5.280 15.710 5.600 ;
        RECT 40.780 5.280 41.100 5.600 ;
        RECT 41.180 5.280 41.500 5.600 ;
        RECT 41.580 5.280 41.900 5.600 ;
        RECT 41.980 5.280 42.300 5.600 ;
        RECT 42.380 5.280 42.700 5.600 ;
        RECT 42.780 5.280 43.100 5.600 ;
        RECT 43.180 5.280 43.500 5.600 ;
        RECT 43.580 5.280 43.900 5.600 ;
        RECT 43.980 5.280 44.300 5.600 ;
        RECT 44.380 5.280 44.700 5.600 ;
      LAYER met4 ;
        RECT -4.820 -3.480 -0.620 44.280 ;
        RECT 14.150 -9.280 15.750 50.080 ;
        RECT 40.640 -3.480 44.840 44.280 ;
      LAYER via4 ;
        RECT -4.110 40.790 -1.330 43.570 ;
        RECT -4.110 15.490 -2.930 16.670 ;
        RECT -2.510 15.490 -1.330 16.670 ;
        RECT -4.110 -2.770 -1.330 0.010 ;
        RECT 14.360 42.390 15.540 43.570 ;
        RECT 14.360 40.790 15.540 41.970 ;
        RECT 14.360 15.490 15.540 16.670 ;
        RECT 14.360 -1.170 15.540 0.010 ;
        RECT 14.360 -2.770 15.540 -1.590 ;
        RECT 41.350 40.790 44.130 43.570 ;
        RECT 41.350 15.490 42.530 16.670 ;
        RECT 42.950 15.490 44.130 16.670 ;
        RECT 41.350 -2.770 44.130 0.010 ;
      LAYER met5 ;
        RECT -4.820 40.080 44.840 44.280 ;
        RECT -10.620 15.280 50.640 16.880 ;
        RECT -4.820 -3.480 44.840 0.720 ;
    END
  END VPWR
  PIN VGND
    ANTENNAGATEAREA 23.750999 ;
    ANTENNADIFFAREA 18.927349 ;
    PORT
      LAYER pwell ;
        RECT 15.195 35.550 15.625 36.335 ;
        RECT 28.995 35.550 29.425 36.335 ;
        RECT 28.995 34.385 29.425 35.170 ;
        RECT 15.195 30.110 15.625 30.895 ;
        RECT 28.995 28.945 29.425 29.730 ;
        RECT 15.195 24.670 15.625 25.455 ;
        RECT 28.995 23.505 29.425 24.290 ;
        RECT 15.195 19.230 15.625 20.015 ;
        RECT 28.995 18.065 29.425 18.850 ;
        RECT 15.195 13.790 15.625 14.575 ;
        RECT 28.995 12.625 29.425 13.410 ;
        RECT 15.195 8.350 15.625 9.135 ;
        RECT 28.995 7.185 29.425 7.970 ;
        RECT 15.195 2.910 15.625 3.695 ;
        RECT 28.995 2.910 29.425 3.695 ;
      LAYER li1 ;
        RECT 1.465 36.215 2.215 36.735 ;
        RECT 37.805 36.215 38.555 36.735 ;
        RECT 1.465 35.445 3.135 36.215 ;
        RECT 15.265 35.445 15.555 36.170 ;
        RECT 25.390 35.445 25.675 35.950 ;
        RECT 29.065 35.445 29.355 36.170 ;
        RECT 36.885 35.445 38.555 36.215 ;
        RECT 1.380 35.275 38.640 35.445 ;
        RECT 1.465 34.505 3.135 35.275 ;
        RECT 5.605 34.770 5.890 35.275 ;
        RECT 21.705 34.770 21.990 35.275 ;
        RECT 25.850 34.770 26.135 35.275 ;
        RECT 29.065 34.550 29.355 35.275 ;
        RECT 36.885 34.505 38.555 35.275 ;
        RECT 1.465 33.985 2.215 34.505 ;
        RECT 37.805 33.985 38.555 34.505 ;
        RECT 1.465 30.775 2.215 31.295 ;
        RECT 1.465 30.005 3.135 30.775 ;
        RECT 15.265 30.005 15.555 30.730 ;
        RECT 22.630 30.005 22.915 30.510 ;
        RECT 32.715 30.005 33.065 30.395 ;
        RECT 33.735 30.005 33.905 30.825 ;
        RECT 37.805 30.775 38.555 31.295 ;
        RECT 36.885 30.005 38.555 30.775 ;
        RECT 1.380 29.835 38.640 30.005 ;
        RECT 1.465 29.065 3.135 29.835 ;
        RECT 1.465 28.545 2.215 29.065 ;
        RECT 20.795 29.025 21.065 29.835 ;
        RECT 21.735 29.025 21.975 29.835 ;
        RECT 24.930 29.330 25.215 29.835 ;
        RECT 29.065 29.110 29.355 29.835 ;
        RECT 36.885 29.065 38.555 29.835 ;
        RECT 37.805 28.545 38.555 29.065 ;
        RECT 1.465 25.335 2.215 25.855 ;
        RECT 1.465 24.565 3.135 25.335 ;
        RECT 6.530 24.565 6.815 25.070 ;
        RECT 9.750 24.565 10.035 25.070 ;
        RECT 12.970 24.565 13.255 25.070 ;
        RECT 15.265 24.565 15.555 25.290 ;
        RECT 18.490 24.565 18.775 25.070 ;
        RECT 21.685 24.565 21.995 25.365 ;
        RECT 27.315 24.565 27.485 25.045 ;
        RECT 31.315 24.565 31.485 25.345 ;
        RECT 37.805 25.335 38.555 25.855 ;
        RECT 34.195 24.565 34.445 25.005 ;
        RECT 36.885 24.565 38.555 25.335 ;
        RECT 1.380 24.395 38.640 24.565 ;
        RECT 1.465 23.625 3.135 24.395 ;
        RECT 5.145 23.890 5.430 24.395 ;
        RECT 9.290 23.890 9.575 24.395 ;
        RECT 14.775 24.015 15.105 24.395 ;
        RECT 16.710 23.935 17.040 24.395 ;
        RECT 19.055 23.935 19.385 24.395 ;
        RECT 21.275 23.665 21.525 24.395 ;
        RECT 1.465 23.105 2.215 23.625 ;
        RECT 22.195 23.595 22.450 24.395 ;
        RECT 29.065 23.670 29.355 24.395 ;
        RECT 36.885 23.625 38.555 24.395 ;
        RECT 37.805 23.105 38.555 23.625 ;
        RECT 1.465 19.895 2.215 20.415 ;
        RECT 37.805 19.895 38.555 20.415 ;
        RECT 1.465 19.125 3.135 19.895 ;
        RECT 5.605 19.125 5.890 19.630 ;
        RECT 8.825 19.125 9.110 19.630 ;
        RECT 12.970 19.125 13.255 19.630 ;
        RECT 15.265 19.125 15.555 19.850 ;
        RECT 18.950 19.125 19.235 19.630 ;
        RECT 21.245 19.125 21.530 19.630 ;
        RECT 25.385 19.125 25.655 19.635 ;
        RECT 26.240 19.125 26.570 19.865 ;
        RECT 27.630 19.125 28.270 19.605 ;
        RECT 29.880 19.125 30.200 19.585 ;
        RECT 30.940 19.125 31.350 19.565 ;
        RECT 33.175 19.125 33.505 19.505 ;
        RECT 34.115 19.125 34.445 19.505 ;
        RECT 36.885 19.125 38.555 19.895 ;
        RECT 1.380 18.955 38.640 19.125 ;
        RECT 1.465 18.185 3.135 18.955 ;
        RECT 8.825 18.450 9.110 18.955 ;
        RECT 12.970 18.450 13.255 18.955 ;
        RECT 18.950 18.450 19.235 18.955 ;
        RECT 22.170 18.450 22.455 18.955 ;
        RECT 29.065 18.230 29.355 18.955 ;
        RECT 1.465 17.665 2.215 18.185 ;
        RECT 32.335 18.135 32.505 18.955 ;
        RECT 33.175 18.565 33.525 18.955 ;
        RECT 36.885 18.185 38.555 18.955 ;
        RECT 37.805 17.665 38.555 18.185 ;
        RECT 1.465 14.455 2.215 14.975 ;
        RECT 37.805 14.455 38.555 14.975 ;
        RECT 1.465 13.685 3.135 14.455 ;
        RECT 6.065 13.685 6.350 14.190 ;
        RECT 10.210 13.685 10.495 14.190 ;
        RECT 15.265 13.685 15.555 14.410 ;
        RECT 18.490 13.685 18.775 14.190 ;
        RECT 22.165 13.685 22.450 14.190 ;
        RECT 25.385 13.685 25.655 14.195 ;
        RECT 26.240 13.685 26.570 14.425 ;
        RECT 27.630 13.685 28.270 14.165 ;
        RECT 29.880 13.685 30.200 14.145 ;
        RECT 30.940 13.685 31.350 14.125 ;
        RECT 33.175 13.685 33.505 14.065 ;
        RECT 34.115 13.685 34.445 14.065 ;
        RECT 36.885 13.685 38.555 14.455 ;
        RECT 1.380 13.515 38.640 13.685 ;
        RECT 1.465 12.745 3.135 13.515 ;
        RECT 7.905 13.010 8.190 13.515 ;
        RECT 17.570 13.010 17.855 13.515 ;
        RECT 24.925 13.010 25.210 13.515 ;
        RECT 29.065 12.790 29.355 13.515 ;
        RECT 36.885 12.745 38.555 13.515 ;
        RECT 1.465 12.225 2.215 12.745 ;
        RECT 37.805 12.225 38.555 12.745 ;
        RECT 1.465 9.015 2.215 9.535 ;
        RECT 37.805 9.015 38.555 9.535 ;
        RECT 1.465 8.245 3.135 9.015 ;
        RECT 12.050 8.245 12.335 8.750 ;
        RECT 15.265 8.245 15.555 8.970 ;
        RECT 22.165 8.245 22.450 8.750 ;
        RECT 25.385 8.245 25.670 8.750 ;
        RECT 29.530 8.245 29.815 8.750 ;
        RECT 36.885 8.245 38.555 9.015 ;
        RECT 1.380 8.075 38.640 8.245 ;
        RECT 1.465 7.305 3.135 8.075 ;
        RECT 6.530 7.570 6.815 8.075 ;
        RECT 8.825 7.570 9.110 8.075 ;
        RECT 12.970 7.570 13.255 8.075 ;
        RECT 16.190 7.570 16.475 8.075 ;
        RECT 19.410 7.570 19.695 8.075 ;
        RECT 22.630 7.570 22.915 8.075 ;
        RECT 25.850 7.570 26.135 8.075 ;
        RECT 29.065 7.350 29.355 8.075 ;
        RECT 32.290 7.570 32.575 8.075 ;
        RECT 36.885 7.305 38.555 8.075 ;
        RECT 1.465 6.785 2.215 7.305 ;
        RECT 37.805 6.785 38.555 7.305 ;
        RECT 1.465 3.575 2.215 4.095 ;
        RECT 37.805 3.575 38.555 4.095 ;
        RECT 1.465 2.805 3.135 3.575 ;
        RECT 6.070 2.805 6.355 3.310 ;
        RECT 12.970 2.805 13.255 3.310 ;
        RECT 15.265 2.805 15.555 3.530 ;
        RECT 18.950 2.805 19.235 3.310 ;
        RECT 29.065 2.805 29.355 3.530 ;
        RECT 31.365 2.805 31.650 3.310 ;
        RECT 36.885 2.805 38.555 3.575 ;
        RECT 1.380 2.635 38.640 2.805 ;
      LAYER mcon ;
        RECT 1.525 35.275 1.695 35.445 ;
        RECT 1.985 35.275 2.155 35.445 ;
        RECT 2.445 35.275 2.615 35.445 ;
        RECT 2.905 35.275 3.075 35.445 ;
        RECT 3.365 35.275 3.535 35.445 ;
        RECT 3.825 35.275 3.995 35.445 ;
        RECT 4.285 35.275 4.455 35.445 ;
        RECT 4.745 35.275 4.915 35.445 ;
        RECT 5.205 35.275 5.375 35.445 ;
        RECT 5.665 35.275 5.835 35.445 ;
        RECT 6.125 35.275 6.295 35.445 ;
        RECT 6.585 35.275 6.755 35.445 ;
        RECT 7.045 35.275 7.215 35.445 ;
        RECT 7.505 35.275 7.675 35.445 ;
        RECT 7.965 35.275 8.135 35.445 ;
        RECT 8.425 35.275 8.595 35.445 ;
        RECT 8.885 35.275 9.055 35.445 ;
        RECT 9.345 35.275 9.515 35.445 ;
        RECT 9.805 35.275 9.975 35.445 ;
        RECT 10.265 35.275 10.435 35.445 ;
        RECT 10.725 35.275 10.895 35.445 ;
        RECT 11.185 35.275 11.355 35.445 ;
        RECT 11.645 35.275 11.815 35.445 ;
        RECT 12.105 35.275 12.275 35.445 ;
        RECT 12.565 35.275 12.735 35.445 ;
        RECT 13.025 35.275 13.195 35.445 ;
        RECT 13.485 35.275 13.655 35.445 ;
        RECT 13.945 35.275 14.115 35.445 ;
        RECT 14.405 35.275 14.575 35.445 ;
        RECT 14.865 35.275 15.035 35.445 ;
        RECT 15.325 35.275 15.495 35.445 ;
        RECT 15.785 35.275 15.955 35.445 ;
        RECT 16.245 35.275 16.415 35.445 ;
        RECT 16.705 35.275 16.875 35.445 ;
        RECT 17.165 35.275 17.335 35.445 ;
        RECT 17.625 35.275 17.795 35.445 ;
        RECT 18.085 35.275 18.255 35.445 ;
        RECT 18.545 35.275 18.715 35.445 ;
        RECT 19.005 35.275 19.175 35.445 ;
        RECT 19.465 35.275 19.635 35.445 ;
        RECT 19.925 35.275 20.095 35.445 ;
        RECT 20.385 35.275 20.555 35.445 ;
        RECT 20.845 35.275 21.015 35.445 ;
        RECT 21.305 35.275 21.475 35.445 ;
        RECT 21.765 35.275 21.935 35.445 ;
        RECT 22.225 35.275 22.395 35.445 ;
        RECT 22.685 35.275 22.855 35.445 ;
        RECT 23.145 35.275 23.315 35.445 ;
        RECT 23.605 35.275 23.775 35.445 ;
        RECT 24.065 35.275 24.235 35.445 ;
        RECT 24.525 35.275 24.695 35.445 ;
        RECT 24.985 35.275 25.155 35.445 ;
        RECT 25.445 35.275 25.615 35.445 ;
        RECT 25.905 35.275 26.075 35.445 ;
        RECT 26.365 35.275 26.535 35.445 ;
        RECT 26.825 35.275 26.995 35.445 ;
        RECT 27.285 35.275 27.455 35.445 ;
        RECT 27.745 35.275 27.915 35.445 ;
        RECT 28.205 35.275 28.375 35.445 ;
        RECT 28.665 35.275 28.835 35.445 ;
        RECT 29.125 35.275 29.295 35.445 ;
        RECT 29.585 35.275 29.755 35.445 ;
        RECT 30.045 35.275 30.215 35.445 ;
        RECT 30.505 35.275 30.675 35.445 ;
        RECT 30.965 35.275 31.135 35.445 ;
        RECT 31.425 35.275 31.595 35.445 ;
        RECT 31.885 35.275 32.055 35.445 ;
        RECT 32.345 35.275 32.515 35.445 ;
        RECT 32.805 35.275 32.975 35.445 ;
        RECT 33.265 35.275 33.435 35.445 ;
        RECT 33.725 35.275 33.895 35.445 ;
        RECT 34.185 35.275 34.355 35.445 ;
        RECT 34.645 35.275 34.815 35.445 ;
        RECT 35.105 35.275 35.275 35.445 ;
        RECT 35.565 35.275 35.735 35.445 ;
        RECT 36.025 35.275 36.195 35.445 ;
        RECT 36.485 35.275 36.655 35.445 ;
        RECT 36.945 35.275 37.115 35.445 ;
        RECT 37.405 35.275 37.575 35.445 ;
        RECT 37.865 35.275 38.035 35.445 ;
        RECT 38.325 35.275 38.495 35.445 ;
        RECT 1.525 29.835 1.695 30.005 ;
        RECT 1.985 29.835 2.155 30.005 ;
        RECT 2.445 29.835 2.615 30.005 ;
        RECT 2.905 29.835 3.075 30.005 ;
        RECT 3.365 29.835 3.535 30.005 ;
        RECT 3.825 29.835 3.995 30.005 ;
        RECT 4.285 29.835 4.455 30.005 ;
        RECT 4.745 29.835 4.915 30.005 ;
        RECT 5.205 29.835 5.375 30.005 ;
        RECT 5.665 29.835 5.835 30.005 ;
        RECT 6.125 29.835 6.295 30.005 ;
        RECT 6.585 29.835 6.755 30.005 ;
        RECT 7.045 29.835 7.215 30.005 ;
        RECT 7.505 29.835 7.675 30.005 ;
        RECT 7.965 29.835 8.135 30.005 ;
        RECT 8.425 29.835 8.595 30.005 ;
        RECT 8.885 29.835 9.055 30.005 ;
        RECT 9.345 29.835 9.515 30.005 ;
        RECT 9.805 29.835 9.975 30.005 ;
        RECT 10.265 29.835 10.435 30.005 ;
        RECT 10.725 29.835 10.895 30.005 ;
        RECT 11.185 29.835 11.355 30.005 ;
        RECT 11.645 29.835 11.815 30.005 ;
        RECT 12.105 29.835 12.275 30.005 ;
        RECT 12.565 29.835 12.735 30.005 ;
        RECT 13.025 29.835 13.195 30.005 ;
        RECT 13.485 29.835 13.655 30.005 ;
        RECT 13.945 29.835 14.115 30.005 ;
        RECT 14.405 29.835 14.575 30.005 ;
        RECT 14.865 29.835 15.035 30.005 ;
        RECT 15.325 29.835 15.495 30.005 ;
        RECT 15.785 29.835 15.955 30.005 ;
        RECT 16.245 29.835 16.415 30.005 ;
        RECT 16.705 29.835 16.875 30.005 ;
        RECT 17.165 29.835 17.335 30.005 ;
        RECT 17.625 29.835 17.795 30.005 ;
        RECT 18.085 29.835 18.255 30.005 ;
        RECT 18.545 29.835 18.715 30.005 ;
        RECT 19.005 29.835 19.175 30.005 ;
        RECT 19.465 29.835 19.635 30.005 ;
        RECT 19.925 29.835 20.095 30.005 ;
        RECT 20.385 29.835 20.555 30.005 ;
        RECT 20.845 29.835 21.015 30.005 ;
        RECT 21.305 29.835 21.475 30.005 ;
        RECT 21.765 29.835 21.935 30.005 ;
        RECT 22.225 29.835 22.395 30.005 ;
        RECT 22.685 29.835 22.855 30.005 ;
        RECT 23.145 29.835 23.315 30.005 ;
        RECT 23.605 29.835 23.775 30.005 ;
        RECT 24.065 29.835 24.235 30.005 ;
        RECT 24.525 29.835 24.695 30.005 ;
        RECT 24.985 29.835 25.155 30.005 ;
        RECT 25.445 29.835 25.615 30.005 ;
        RECT 25.905 29.835 26.075 30.005 ;
        RECT 26.365 29.835 26.535 30.005 ;
        RECT 26.825 29.835 26.995 30.005 ;
        RECT 27.285 29.835 27.455 30.005 ;
        RECT 27.745 29.835 27.915 30.005 ;
        RECT 28.205 29.835 28.375 30.005 ;
        RECT 28.665 29.835 28.835 30.005 ;
        RECT 29.125 29.835 29.295 30.005 ;
        RECT 29.585 29.835 29.755 30.005 ;
        RECT 30.045 29.835 30.215 30.005 ;
        RECT 30.505 29.835 30.675 30.005 ;
        RECT 30.965 29.835 31.135 30.005 ;
        RECT 31.425 29.835 31.595 30.005 ;
        RECT 31.885 29.835 32.055 30.005 ;
        RECT 32.345 29.835 32.515 30.005 ;
        RECT 32.805 29.835 32.975 30.005 ;
        RECT 33.265 29.835 33.435 30.005 ;
        RECT 33.725 29.835 33.895 30.005 ;
        RECT 34.185 29.835 34.355 30.005 ;
        RECT 34.645 29.835 34.815 30.005 ;
        RECT 35.105 29.835 35.275 30.005 ;
        RECT 35.565 29.835 35.735 30.005 ;
        RECT 36.025 29.835 36.195 30.005 ;
        RECT 36.485 29.835 36.655 30.005 ;
        RECT 36.945 29.835 37.115 30.005 ;
        RECT 37.405 29.835 37.575 30.005 ;
        RECT 37.865 29.835 38.035 30.005 ;
        RECT 38.325 29.835 38.495 30.005 ;
        RECT 1.525 24.395 1.695 24.565 ;
        RECT 1.985 24.395 2.155 24.565 ;
        RECT 2.445 24.395 2.615 24.565 ;
        RECT 2.905 24.395 3.075 24.565 ;
        RECT 3.365 24.395 3.535 24.565 ;
        RECT 3.825 24.395 3.995 24.565 ;
        RECT 4.285 24.395 4.455 24.565 ;
        RECT 4.745 24.395 4.915 24.565 ;
        RECT 5.205 24.395 5.375 24.565 ;
        RECT 5.665 24.395 5.835 24.565 ;
        RECT 6.125 24.395 6.295 24.565 ;
        RECT 6.585 24.395 6.755 24.565 ;
        RECT 7.045 24.395 7.215 24.565 ;
        RECT 7.505 24.395 7.675 24.565 ;
        RECT 7.965 24.395 8.135 24.565 ;
        RECT 8.425 24.395 8.595 24.565 ;
        RECT 8.885 24.395 9.055 24.565 ;
        RECT 9.345 24.395 9.515 24.565 ;
        RECT 9.805 24.395 9.975 24.565 ;
        RECT 10.265 24.395 10.435 24.565 ;
        RECT 10.725 24.395 10.895 24.565 ;
        RECT 11.185 24.395 11.355 24.565 ;
        RECT 11.645 24.395 11.815 24.565 ;
        RECT 12.105 24.395 12.275 24.565 ;
        RECT 12.565 24.395 12.735 24.565 ;
        RECT 13.025 24.395 13.195 24.565 ;
        RECT 13.485 24.395 13.655 24.565 ;
        RECT 13.945 24.395 14.115 24.565 ;
        RECT 14.405 24.395 14.575 24.565 ;
        RECT 14.865 24.395 15.035 24.565 ;
        RECT 15.325 24.395 15.495 24.565 ;
        RECT 15.785 24.395 15.955 24.565 ;
        RECT 16.245 24.395 16.415 24.565 ;
        RECT 16.705 24.395 16.875 24.565 ;
        RECT 17.165 24.395 17.335 24.565 ;
        RECT 17.625 24.395 17.795 24.565 ;
        RECT 18.085 24.395 18.255 24.565 ;
        RECT 18.545 24.395 18.715 24.565 ;
        RECT 19.005 24.395 19.175 24.565 ;
        RECT 19.465 24.395 19.635 24.565 ;
        RECT 19.925 24.395 20.095 24.565 ;
        RECT 20.385 24.395 20.555 24.565 ;
        RECT 20.845 24.395 21.015 24.565 ;
        RECT 21.305 24.395 21.475 24.565 ;
        RECT 21.765 24.395 21.935 24.565 ;
        RECT 22.225 24.395 22.395 24.565 ;
        RECT 22.685 24.395 22.855 24.565 ;
        RECT 23.145 24.395 23.315 24.565 ;
        RECT 23.605 24.395 23.775 24.565 ;
        RECT 24.065 24.395 24.235 24.565 ;
        RECT 24.525 24.395 24.695 24.565 ;
        RECT 24.985 24.395 25.155 24.565 ;
        RECT 25.445 24.395 25.615 24.565 ;
        RECT 25.905 24.395 26.075 24.565 ;
        RECT 26.365 24.395 26.535 24.565 ;
        RECT 26.825 24.395 26.995 24.565 ;
        RECT 27.285 24.395 27.455 24.565 ;
        RECT 27.745 24.395 27.915 24.565 ;
        RECT 28.205 24.395 28.375 24.565 ;
        RECT 28.665 24.395 28.835 24.565 ;
        RECT 29.125 24.395 29.295 24.565 ;
        RECT 29.585 24.395 29.755 24.565 ;
        RECT 30.045 24.395 30.215 24.565 ;
        RECT 30.505 24.395 30.675 24.565 ;
        RECT 30.965 24.395 31.135 24.565 ;
        RECT 31.425 24.395 31.595 24.565 ;
        RECT 31.885 24.395 32.055 24.565 ;
        RECT 32.345 24.395 32.515 24.565 ;
        RECT 32.805 24.395 32.975 24.565 ;
        RECT 33.265 24.395 33.435 24.565 ;
        RECT 33.725 24.395 33.895 24.565 ;
        RECT 34.185 24.395 34.355 24.565 ;
        RECT 34.645 24.395 34.815 24.565 ;
        RECT 35.105 24.395 35.275 24.565 ;
        RECT 35.565 24.395 35.735 24.565 ;
        RECT 36.025 24.395 36.195 24.565 ;
        RECT 36.485 24.395 36.655 24.565 ;
        RECT 36.945 24.395 37.115 24.565 ;
        RECT 37.405 24.395 37.575 24.565 ;
        RECT 37.865 24.395 38.035 24.565 ;
        RECT 38.325 24.395 38.495 24.565 ;
        RECT 1.525 18.955 1.695 19.125 ;
        RECT 1.985 18.955 2.155 19.125 ;
        RECT 2.445 18.955 2.615 19.125 ;
        RECT 2.905 18.955 3.075 19.125 ;
        RECT 3.365 18.955 3.535 19.125 ;
        RECT 3.825 18.955 3.995 19.125 ;
        RECT 4.285 18.955 4.455 19.125 ;
        RECT 4.745 18.955 4.915 19.125 ;
        RECT 5.205 18.955 5.375 19.125 ;
        RECT 5.665 18.955 5.835 19.125 ;
        RECT 6.125 18.955 6.295 19.125 ;
        RECT 6.585 18.955 6.755 19.125 ;
        RECT 7.045 18.955 7.215 19.125 ;
        RECT 7.505 18.955 7.675 19.125 ;
        RECT 7.965 18.955 8.135 19.125 ;
        RECT 8.425 18.955 8.595 19.125 ;
        RECT 8.885 18.955 9.055 19.125 ;
        RECT 9.345 18.955 9.515 19.125 ;
        RECT 9.805 18.955 9.975 19.125 ;
        RECT 10.265 18.955 10.435 19.125 ;
        RECT 10.725 18.955 10.895 19.125 ;
        RECT 11.185 18.955 11.355 19.125 ;
        RECT 11.645 18.955 11.815 19.125 ;
        RECT 12.105 18.955 12.275 19.125 ;
        RECT 12.565 18.955 12.735 19.125 ;
        RECT 13.025 18.955 13.195 19.125 ;
        RECT 13.485 18.955 13.655 19.125 ;
        RECT 13.945 18.955 14.115 19.125 ;
        RECT 14.405 18.955 14.575 19.125 ;
        RECT 14.865 18.955 15.035 19.125 ;
        RECT 15.325 18.955 15.495 19.125 ;
        RECT 15.785 18.955 15.955 19.125 ;
        RECT 16.245 18.955 16.415 19.125 ;
        RECT 16.705 18.955 16.875 19.125 ;
        RECT 17.165 18.955 17.335 19.125 ;
        RECT 17.625 18.955 17.795 19.125 ;
        RECT 18.085 18.955 18.255 19.125 ;
        RECT 18.545 18.955 18.715 19.125 ;
        RECT 19.005 18.955 19.175 19.125 ;
        RECT 19.465 18.955 19.635 19.125 ;
        RECT 19.925 18.955 20.095 19.125 ;
        RECT 20.385 18.955 20.555 19.125 ;
        RECT 20.845 18.955 21.015 19.125 ;
        RECT 21.305 18.955 21.475 19.125 ;
        RECT 21.765 18.955 21.935 19.125 ;
        RECT 22.225 18.955 22.395 19.125 ;
        RECT 22.685 18.955 22.855 19.125 ;
        RECT 23.145 18.955 23.315 19.125 ;
        RECT 23.605 18.955 23.775 19.125 ;
        RECT 24.065 18.955 24.235 19.125 ;
        RECT 24.525 18.955 24.695 19.125 ;
        RECT 24.985 18.955 25.155 19.125 ;
        RECT 25.445 18.955 25.615 19.125 ;
        RECT 25.905 18.955 26.075 19.125 ;
        RECT 26.365 18.955 26.535 19.125 ;
        RECT 26.825 18.955 26.995 19.125 ;
        RECT 27.285 18.955 27.455 19.125 ;
        RECT 27.745 18.955 27.915 19.125 ;
        RECT 28.205 18.955 28.375 19.125 ;
        RECT 28.665 18.955 28.835 19.125 ;
        RECT 29.125 18.955 29.295 19.125 ;
        RECT 29.585 18.955 29.755 19.125 ;
        RECT 30.045 18.955 30.215 19.125 ;
        RECT 30.505 18.955 30.675 19.125 ;
        RECT 30.965 18.955 31.135 19.125 ;
        RECT 31.425 18.955 31.595 19.125 ;
        RECT 31.885 18.955 32.055 19.125 ;
        RECT 32.345 18.955 32.515 19.125 ;
        RECT 32.805 18.955 32.975 19.125 ;
        RECT 33.265 18.955 33.435 19.125 ;
        RECT 33.725 18.955 33.895 19.125 ;
        RECT 34.185 18.955 34.355 19.125 ;
        RECT 34.645 18.955 34.815 19.125 ;
        RECT 35.105 18.955 35.275 19.125 ;
        RECT 35.565 18.955 35.735 19.125 ;
        RECT 36.025 18.955 36.195 19.125 ;
        RECT 36.485 18.955 36.655 19.125 ;
        RECT 36.945 18.955 37.115 19.125 ;
        RECT 37.405 18.955 37.575 19.125 ;
        RECT 37.865 18.955 38.035 19.125 ;
        RECT 38.325 18.955 38.495 19.125 ;
        RECT 1.525 13.515 1.695 13.685 ;
        RECT 1.985 13.515 2.155 13.685 ;
        RECT 2.445 13.515 2.615 13.685 ;
        RECT 2.905 13.515 3.075 13.685 ;
        RECT 3.365 13.515 3.535 13.685 ;
        RECT 3.825 13.515 3.995 13.685 ;
        RECT 4.285 13.515 4.455 13.685 ;
        RECT 4.745 13.515 4.915 13.685 ;
        RECT 5.205 13.515 5.375 13.685 ;
        RECT 5.665 13.515 5.835 13.685 ;
        RECT 6.125 13.515 6.295 13.685 ;
        RECT 6.585 13.515 6.755 13.685 ;
        RECT 7.045 13.515 7.215 13.685 ;
        RECT 7.505 13.515 7.675 13.685 ;
        RECT 7.965 13.515 8.135 13.685 ;
        RECT 8.425 13.515 8.595 13.685 ;
        RECT 8.885 13.515 9.055 13.685 ;
        RECT 9.345 13.515 9.515 13.685 ;
        RECT 9.805 13.515 9.975 13.685 ;
        RECT 10.265 13.515 10.435 13.685 ;
        RECT 10.725 13.515 10.895 13.685 ;
        RECT 11.185 13.515 11.355 13.685 ;
        RECT 11.645 13.515 11.815 13.685 ;
        RECT 12.105 13.515 12.275 13.685 ;
        RECT 12.565 13.515 12.735 13.685 ;
        RECT 13.025 13.515 13.195 13.685 ;
        RECT 13.485 13.515 13.655 13.685 ;
        RECT 13.945 13.515 14.115 13.685 ;
        RECT 14.405 13.515 14.575 13.685 ;
        RECT 14.865 13.515 15.035 13.685 ;
        RECT 15.325 13.515 15.495 13.685 ;
        RECT 15.785 13.515 15.955 13.685 ;
        RECT 16.245 13.515 16.415 13.685 ;
        RECT 16.705 13.515 16.875 13.685 ;
        RECT 17.165 13.515 17.335 13.685 ;
        RECT 17.625 13.515 17.795 13.685 ;
        RECT 18.085 13.515 18.255 13.685 ;
        RECT 18.545 13.515 18.715 13.685 ;
        RECT 19.005 13.515 19.175 13.685 ;
        RECT 19.465 13.515 19.635 13.685 ;
        RECT 19.925 13.515 20.095 13.685 ;
        RECT 20.385 13.515 20.555 13.685 ;
        RECT 20.845 13.515 21.015 13.685 ;
        RECT 21.305 13.515 21.475 13.685 ;
        RECT 21.765 13.515 21.935 13.685 ;
        RECT 22.225 13.515 22.395 13.685 ;
        RECT 22.685 13.515 22.855 13.685 ;
        RECT 23.145 13.515 23.315 13.685 ;
        RECT 23.605 13.515 23.775 13.685 ;
        RECT 24.065 13.515 24.235 13.685 ;
        RECT 24.525 13.515 24.695 13.685 ;
        RECT 24.985 13.515 25.155 13.685 ;
        RECT 25.445 13.515 25.615 13.685 ;
        RECT 25.905 13.515 26.075 13.685 ;
        RECT 26.365 13.515 26.535 13.685 ;
        RECT 26.825 13.515 26.995 13.685 ;
        RECT 27.285 13.515 27.455 13.685 ;
        RECT 27.745 13.515 27.915 13.685 ;
        RECT 28.205 13.515 28.375 13.685 ;
        RECT 28.665 13.515 28.835 13.685 ;
        RECT 29.125 13.515 29.295 13.685 ;
        RECT 29.585 13.515 29.755 13.685 ;
        RECT 30.045 13.515 30.215 13.685 ;
        RECT 30.505 13.515 30.675 13.685 ;
        RECT 30.965 13.515 31.135 13.685 ;
        RECT 31.425 13.515 31.595 13.685 ;
        RECT 31.885 13.515 32.055 13.685 ;
        RECT 32.345 13.515 32.515 13.685 ;
        RECT 32.805 13.515 32.975 13.685 ;
        RECT 33.265 13.515 33.435 13.685 ;
        RECT 33.725 13.515 33.895 13.685 ;
        RECT 34.185 13.515 34.355 13.685 ;
        RECT 34.645 13.515 34.815 13.685 ;
        RECT 35.105 13.515 35.275 13.685 ;
        RECT 35.565 13.515 35.735 13.685 ;
        RECT 36.025 13.515 36.195 13.685 ;
        RECT 36.485 13.515 36.655 13.685 ;
        RECT 36.945 13.515 37.115 13.685 ;
        RECT 37.405 13.515 37.575 13.685 ;
        RECT 37.865 13.515 38.035 13.685 ;
        RECT 38.325 13.515 38.495 13.685 ;
        RECT 1.525 8.075 1.695 8.245 ;
        RECT 1.985 8.075 2.155 8.245 ;
        RECT 2.445 8.075 2.615 8.245 ;
        RECT 2.905 8.075 3.075 8.245 ;
        RECT 3.365 8.075 3.535 8.245 ;
        RECT 3.825 8.075 3.995 8.245 ;
        RECT 4.285 8.075 4.455 8.245 ;
        RECT 4.745 8.075 4.915 8.245 ;
        RECT 5.205 8.075 5.375 8.245 ;
        RECT 5.665 8.075 5.835 8.245 ;
        RECT 6.125 8.075 6.295 8.245 ;
        RECT 6.585 8.075 6.755 8.245 ;
        RECT 7.045 8.075 7.215 8.245 ;
        RECT 7.505 8.075 7.675 8.245 ;
        RECT 7.965 8.075 8.135 8.245 ;
        RECT 8.425 8.075 8.595 8.245 ;
        RECT 8.885 8.075 9.055 8.245 ;
        RECT 9.345 8.075 9.515 8.245 ;
        RECT 9.805 8.075 9.975 8.245 ;
        RECT 10.265 8.075 10.435 8.245 ;
        RECT 10.725 8.075 10.895 8.245 ;
        RECT 11.185 8.075 11.355 8.245 ;
        RECT 11.645 8.075 11.815 8.245 ;
        RECT 12.105 8.075 12.275 8.245 ;
        RECT 12.565 8.075 12.735 8.245 ;
        RECT 13.025 8.075 13.195 8.245 ;
        RECT 13.485 8.075 13.655 8.245 ;
        RECT 13.945 8.075 14.115 8.245 ;
        RECT 14.405 8.075 14.575 8.245 ;
        RECT 14.865 8.075 15.035 8.245 ;
        RECT 15.325 8.075 15.495 8.245 ;
        RECT 15.785 8.075 15.955 8.245 ;
        RECT 16.245 8.075 16.415 8.245 ;
        RECT 16.705 8.075 16.875 8.245 ;
        RECT 17.165 8.075 17.335 8.245 ;
        RECT 17.625 8.075 17.795 8.245 ;
        RECT 18.085 8.075 18.255 8.245 ;
        RECT 18.545 8.075 18.715 8.245 ;
        RECT 19.005 8.075 19.175 8.245 ;
        RECT 19.465 8.075 19.635 8.245 ;
        RECT 19.925 8.075 20.095 8.245 ;
        RECT 20.385 8.075 20.555 8.245 ;
        RECT 20.845 8.075 21.015 8.245 ;
        RECT 21.305 8.075 21.475 8.245 ;
        RECT 21.765 8.075 21.935 8.245 ;
        RECT 22.225 8.075 22.395 8.245 ;
        RECT 22.685 8.075 22.855 8.245 ;
        RECT 23.145 8.075 23.315 8.245 ;
        RECT 23.605 8.075 23.775 8.245 ;
        RECT 24.065 8.075 24.235 8.245 ;
        RECT 24.525 8.075 24.695 8.245 ;
        RECT 24.985 8.075 25.155 8.245 ;
        RECT 25.445 8.075 25.615 8.245 ;
        RECT 25.905 8.075 26.075 8.245 ;
        RECT 26.365 8.075 26.535 8.245 ;
        RECT 26.825 8.075 26.995 8.245 ;
        RECT 27.285 8.075 27.455 8.245 ;
        RECT 27.745 8.075 27.915 8.245 ;
        RECT 28.205 8.075 28.375 8.245 ;
        RECT 28.665 8.075 28.835 8.245 ;
        RECT 29.125 8.075 29.295 8.245 ;
        RECT 29.585 8.075 29.755 8.245 ;
        RECT 30.045 8.075 30.215 8.245 ;
        RECT 30.505 8.075 30.675 8.245 ;
        RECT 30.965 8.075 31.135 8.245 ;
        RECT 31.425 8.075 31.595 8.245 ;
        RECT 31.885 8.075 32.055 8.245 ;
        RECT 32.345 8.075 32.515 8.245 ;
        RECT 32.805 8.075 32.975 8.245 ;
        RECT 33.265 8.075 33.435 8.245 ;
        RECT 33.725 8.075 33.895 8.245 ;
        RECT 34.185 8.075 34.355 8.245 ;
        RECT 34.645 8.075 34.815 8.245 ;
        RECT 35.105 8.075 35.275 8.245 ;
        RECT 35.565 8.075 35.735 8.245 ;
        RECT 36.025 8.075 36.195 8.245 ;
        RECT 36.485 8.075 36.655 8.245 ;
        RECT 36.945 8.075 37.115 8.245 ;
        RECT 37.405 8.075 37.575 8.245 ;
        RECT 37.865 8.075 38.035 8.245 ;
        RECT 38.325 8.075 38.495 8.245 ;
        RECT 1.525 2.635 1.695 2.805 ;
        RECT 1.985 2.635 2.155 2.805 ;
        RECT 2.445 2.635 2.615 2.805 ;
        RECT 2.905 2.635 3.075 2.805 ;
        RECT 3.365 2.635 3.535 2.805 ;
        RECT 3.825 2.635 3.995 2.805 ;
        RECT 4.285 2.635 4.455 2.805 ;
        RECT 4.745 2.635 4.915 2.805 ;
        RECT 5.205 2.635 5.375 2.805 ;
        RECT 5.665 2.635 5.835 2.805 ;
        RECT 6.125 2.635 6.295 2.805 ;
        RECT 6.585 2.635 6.755 2.805 ;
        RECT 7.045 2.635 7.215 2.805 ;
        RECT 7.505 2.635 7.675 2.805 ;
        RECT 7.965 2.635 8.135 2.805 ;
        RECT 8.425 2.635 8.595 2.805 ;
        RECT 8.885 2.635 9.055 2.805 ;
        RECT 9.345 2.635 9.515 2.805 ;
        RECT 9.805 2.635 9.975 2.805 ;
        RECT 10.265 2.635 10.435 2.805 ;
        RECT 10.725 2.635 10.895 2.805 ;
        RECT 11.185 2.635 11.355 2.805 ;
        RECT 11.645 2.635 11.815 2.805 ;
        RECT 12.105 2.635 12.275 2.805 ;
        RECT 12.565 2.635 12.735 2.805 ;
        RECT 13.025 2.635 13.195 2.805 ;
        RECT 13.485 2.635 13.655 2.805 ;
        RECT 13.945 2.635 14.115 2.805 ;
        RECT 14.405 2.635 14.575 2.805 ;
        RECT 14.865 2.635 15.035 2.805 ;
        RECT 15.325 2.635 15.495 2.805 ;
        RECT 15.785 2.635 15.955 2.805 ;
        RECT 16.245 2.635 16.415 2.805 ;
        RECT 16.705 2.635 16.875 2.805 ;
        RECT 17.165 2.635 17.335 2.805 ;
        RECT 17.625 2.635 17.795 2.805 ;
        RECT 18.085 2.635 18.255 2.805 ;
        RECT 18.545 2.635 18.715 2.805 ;
        RECT 19.005 2.635 19.175 2.805 ;
        RECT 19.465 2.635 19.635 2.805 ;
        RECT 19.925 2.635 20.095 2.805 ;
        RECT 20.385 2.635 20.555 2.805 ;
        RECT 20.845 2.635 21.015 2.805 ;
        RECT 21.305 2.635 21.475 2.805 ;
        RECT 21.765 2.635 21.935 2.805 ;
        RECT 22.225 2.635 22.395 2.805 ;
        RECT 22.685 2.635 22.855 2.805 ;
        RECT 23.145 2.635 23.315 2.805 ;
        RECT 23.605 2.635 23.775 2.805 ;
        RECT 24.065 2.635 24.235 2.805 ;
        RECT 24.525 2.635 24.695 2.805 ;
        RECT 24.985 2.635 25.155 2.805 ;
        RECT 25.445 2.635 25.615 2.805 ;
        RECT 25.905 2.635 26.075 2.805 ;
        RECT 26.365 2.635 26.535 2.805 ;
        RECT 26.825 2.635 26.995 2.805 ;
        RECT 27.285 2.635 27.455 2.805 ;
        RECT 27.745 2.635 27.915 2.805 ;
        RECT 28.205 2.635 28.375 2.805 ;
        RECT 28.665 2.635 28.835 2.805 ;
        RECT 29.125 2.635 29.295 2.805 ;
        RECT 29.585 2.635 29.755 2.805 ;
        RECT 30.045 2.635 30.215 2.805 ;
        RECT 30.505 2.635 30.675 2.805 ;
        RECT 30.965 2.635 31.135 2.805 ;
        RECT 31.425 2.635 31.595 2.805 ;
        RECT 31.885 2.635 32.055 2.805 ;
        RECT 32.345 2.635 32.515 2.805 ;
        RECT 32.805 2.635 32.975 2.805 ;
        RECT 33.265 2.635 33.435 2.805 ;
        RECT 33.725 2.635 33.895 2.805 ;
        RECT 34.185 2.635 34.355 2.805 ;
        RECT 34.645 2.635 34.815 2.805 ;
        RECT 35.105 2.635 35.275 2.805 ;
        RECT 35.565 2.635 35.735 2.805 ;
        RECT 36.025 2.635 36.195 2.805 ;
        RECT 36.485 2.635 36.655 2.805 ;
        RECT 36.945 2.635 37.115 2.805 ;
        RECT 37.405 2.635 37.575 2.805 ;
        RECT 37.865 2.635 38.035 2.805 ;
        RECT 38.325 2.635 38.495 2.805 ;
      LAYER met1 ;
        RECT -10.620 35.120 50.640 35.600 ;
        RECT -10.620 29.680 50.640 30.160 ;
        RECT -10.620 24.240 50.640 24.720 ;
        RECT -10.620 18.800 50.640 19.280 ;
        RECT -10.620 13.360 50.640 13.840 ;
        RECT -10.620 7.920 50.640 8.400 ;
        RECT -10.620 2.480 50.640 2.960 ;
      LAYER via ;
        RECT -10.570 35.230 -10.310 35.490 ;
        RECT -10.250 35.230 -9.990 35.490 ;
        RECT -9.930 35.230 -9.670 35.490 ;
        RECT -9.610 35.230 -9.350 35.490 ;
        RECT -9.290 35.230 -9.030 35.490 ;
        RECT -8.970 35.230 -8.710 35.490 ;
        RECT -8.650 35.230 -8.390 35.490 ;
        RECT -8.330 35.230 -8.070 35.490 ;
        RECT -8.010 35.230 -7.750 35.490 ;
        RECT -7.690 35.230 -7.430 35.490 ;
        RECT -7.370 35.230 -7.110 35.490 ;
        RECT -7.050 35.230 -6.790 35.490 ;
        RECT -6.730 35.230 -6.470 35.490 ;
        RECT 27.750 35.230 28.010 35.490 ;
        RECT 28.070 35.230 28.330 35.490 ;
        RECT 28.390 35.230 28.650 35.490 ;
        RECT 28.710 35.230 28.970 35.490 ;
        RECT 29.030 35.230 29.290 35.490 ;
        RECT 46.490 35.230 46.750 35.490 ;
        RECT 46.810 35.230 47.070 35.490 ;
        RECT 47.130 35.230 47.390 35.490 ;
        RECT 47.450 35.230 47.710 35.490 ;
        RECT 47.770 35.230 48.030 35.490 ;
        RECT 48.090 35.230 48.350 35.490 ;
        RECT 48.410 35.230 48.670 35.490 ;
        RECT 48.730 35.230 48.990 35.490 ;
        RECT 49.050 35.230 49.310 35.490 ;
        RECT 49.370 35.230 49.630 35.490 ;
        RECT 49.690 35.230 49.950 35.490 ;
        RECT 50.010 35.230 50.270 35.490 ;
        RECT 50.330 35.230 50.590 35.490 ;
        RECT -10.570 29.790 -10.310 30.050 ;
        RECT -10.250 29.790 -9.990 30.050 ;
        RECT -9.930 29.790 -9.670 30.050 ;
        RECT -9.610 29.790 -9.350 30.050 ;
        RECT -9.290 29.790 -9.030 30.050 ;
        RECT -8.970 29.790 -8.710 30.050 ;
        RECT -8.650 29.790 -8.390 30.050 ;
        RECT -8.330 29.790 -8.070 30.050 ;
        RECT -8.010 29.790 -7.750 30.050 ;
        RECT -7.690 29.790 -7.430 30.050 ;
        RECT -7.370 29.790 -7.110 30.050 ;
        RECT -7.050 29.790 -6.790 30.050 ;
        RECT -6.730 29.790 -6.470 30.050 ;
        RECT 27.750 29.790 28.010 30.050 ;
        RECT 28.070 29.790 28.330 30.050 ;
        RECT 28.390 29.790 28.650 30.050 ;
        RECT 28.710 29.790 28.970 30.050 ;
        RECT 29.030 29.790 29.290 30.050 ;
        RECT 46.490 29.790 46.750 30.050 ;
        RECT 46.810 29.790 47.070 30.050 ;
        RECT 47.130 29.790 47.390 30.050 ;
        RECT 47.450 29.790 47.710 30.050 ;
        RECT 47.770 29.790 48.030 30.050 ;
        RECT 48.090 29.790 48.350 30.050 ;
        RECT 48.410 29.790 48.670 30.050 ;
        RECT 48.730 29.790 48.990 30.050 ;
        RECT 49.050 29.790 49.310 30.050 ;
        RECT 49.370 29.790 49.630 30.050 ;
        RECT 49.690 29.790 49.950 30.050 ;
        RECT 50.010 29.790 50.270 30.050 ;
        RECT 50.330 29.790 50.590 30.050 ;
        RECT -10.570 24.350 -10.310 24.610 ;
        RECT -10.250 24.350 -9.990 24.610 ;
        RECT -9.930 24.350 -9.670 24.610 ;
        RECT -9.610 24.350 -9.350 24.610 ;
        RECT -9.290 24.350 -9.030 24.610 ;
        RECT -8.970 24.350 -8.710 24.610 ;
        RECT -8.650 24.350 -8.390 24.610 ;
        RECT -8.330 24.350 -8.070 24.610 ;
        RECT -8.010 24.350 -7.750 24.610 ;
        RECT -7.690 24.350 -7.430 24.610 ;
        RECT -7.370 24.350 -7.110 24.610 ;
        RECT -7.050 24.350 -6.790 24.610 ;
        RECT -6.730 24.350 -6.470 24.610 ;
        RECT 27.750 24.350 28.010 24.610 ;
        RECT 28.070 24.350 28.330 24.610 ;
        RECT 28.390 24.350 28.650 24.610 ;
        RECT 28.710 24.350 28.970 24.610 ;
        RECT 29.030 24.350 29.290 24.610 ;
        RECT 46.490 24.350 46.750 24.610 ;
        RECT 46.810 24.350 47.070 24.610 ;
        RECT 47.130 24.350 47.390 24.610 ;
        RECT 47.450 24.350 47.710 24.610 ;
        RECT 47.770 24.350 48.030 24.610 ;
        RECT 48.090 24.350 48.350 24.610 ;
        RECT 48.410 24.350 48.670 24.610 ;
        RECT 48.730 24.350 48.990 24.610 ;
        RECT 49.050 24.350 49.310 24.610 ;
        RECT 49.370 24.350 49.630 24.610 ;
        RECT 49.690 24.350 49.950 24.610 ;
        RECT 50.010 24.350 50.270 24.610 ;
        RECT 50.330 24.350 50.590 24.610 ;
        RECT -10.570 18.910 -10.310 19.170 ;
        RECT -10.250 18.910 -9.990 19.170 ;
        RECT -9.930 18.910 -9.670 19.170 ;
        RECT -9.610 18.910 -9.350 19.170 ;
        RECT -9.290 18.910 -9.030 19.170 ;
        RECT -8.970 18.910 -8.710 19.170 ;
        RECT -8.650 18.910 -8.390 19.170 ;
        RECT -8.330 18.910 -8.070 19.170 ;
        RECT -8.010 18.910 -7.750 19.170 ;
        RECT -7.690 18.910 -7.430 19.170 ;
        RECT -7.370 18.910 -7.110 19.170 ;
        RECT -7.050 18.910 -6.790 19.170 ;
        RECT -6.730 18.910 -6.470 19.170 ;
        RECT 27.750 18.910 28.010 19.170 ;
        RECT 28.070 18.910 28.330 19.170 ;
        RECT 28.390 18.910 28.650 19.170 ;
        RECT 28.710 18.910 28.970 19.170 ;
        RECT 29.030 18.910 29.290 19.170 ;
        RECT 46.490 18.910 46.750 19.170 ;
        RECT 46.810 18.910 47.070 19.170 ;
        RECT 47.130 18.910 47.390 19.170 ;
        RECT 47.450 18.910 47.710 19.170 ;
        RECT 47.770 18.910 48.030 19.170 ;
        RECT 48.090 18.910 48.350 19.170 ;
        RECT 48.410 18.910 48.670 19.170 ;
        RECT 48.730 18.910 48.990 19.170 ;
        RECT 49.050 18.910 49.310 19.170 ;
        RECT 49.370 18.910 49.630 19.170 ;
        RECT 49.690 18.910 49.950 19.170 ;
        RECT 50.010 18.910 50.270 19.170 ;
        RECT 50.330 18.910 50.590 19.170 ;
        RECT -10.570 13.470 -10.310 13.730 ;
        RECT -10.250 13.470 -9.990 13.730 ;
        RECT -9.930 13.470 -9.670 13.730 ;
        RECT -9.610 13.470 -9.350 13.730 ;
        RECT -9.290 13.470 -9.030 13.730 ;
        RECT -8.970 13.470 -8.710 13.730 ;
        RECT -8.650 13.470 -8.390 13.730 ;
        RECT -8.330 13.470 -8.070 13.730 ;
        RECT -8.010 13.470 -7.750 13.730 ;
        RECT -7.690 13.470 -7.430 13.730 ;
        RECT -7.370 13.470 -7.110 13.730 ;
        RECT -7.050 13.470 -6.790 13.730 ;
        RECT -6.730 13.470 -6.470 13.730 ;
        RECT 27.750 13.470 28.010 13.730 ;
        RECT 28.070 13.470 28.330 13.730 ;
        RECT 28.390 13.470 28.650 13.730 ;
        RECT 28.710 13.470 28.970 13.730 ;
        RECT 29.030 13.470 29.290 13.730 ;
        RECT 46.490 13.470 46.750 13.730 ;
        RECT 46.810 13.470 47.070 13.730 ;
        RECT 47.130 13.470 47.390 13.730 ;
        RECT 47.450 13.470 47.710 13.730 ;
        RECT 47.770 13.470 48.030 13.730 ;
        RECT 48.090 13.470 48.350 13.730 ;
        RECT 48.410 13.470 48.670 13.730 ;
        RECT 48.730 13.470 48.990 13.730 ;
        RECT 49.050 13.470 49.310 13.730 ;
        RECT 49.370 13.470 49.630 13.730 ;
        RECT 49.690 13.470 49.950 13.730 ;
        RECT 50.010 13.470 50.270 13.730 ;
        RECT 50.330 13.470 50.590 13.730 ;
        RECT -10.570 8.030 -10.310 8.290 ;
        RECT -10.250 8.030 -9.990 8.290 ;
        RECT -9.930 8.030 -9.670 8.290 ;
        RECT -9.610 8.030 -9.350 8.290 ;
        RECT -9.290 8.030 -9.030 8.290 ;
        RECT -8.970 8.030 -8.710 8.290 ;
        RECT -8.650 8.030 -8.390 8.290 ;
        RECT -8.330 8.030 -8.070 8.290 ;
        RECT -8.010 8.030 -7.750 8.290 ;
        RECT -7.690 8.030 -7.430 8.290 ;
        RECT -7.370 8.030 -7.110 8.290 ;
        RECT -7.050 8.030 -6.790 8.290 ;
        RECT -6.730 8.030 -6.470 8.290 ;
        RECT 27.750 8.030 28.010 8.290 ;
        RECT 28.070 8.030 28.330 8.290 ;
        RECT 28.390 8.030 28.650 8.290 ;
        RECT 28.710 8.030 28.970 8.290 ;
        RECT 29.030 8.030 29.290 8.290 ;
        RECT 46.490 8.030 46.750 8.290 ;
        RECT 46.810 8.030 47.070 8.290 ;
        RECT 47.130 8.030 47.390 8.290 ;
        RECT 47.450 8.030 47.710 8.290 ;
        RECT 47.770 8.030 48.030 8.290 ;
        RECT 48.090 8.030 48.350 8.290 ;
        RECT 48.410 8.030 48.670 8.290 ;
        RECT 48.730 8.030 48.990 8.290 ;
        RECT 49.050 8.030 49.310 8.290 ;
        RECT 49.370 8.030 49.630 8.290 ;
        RECT 49.690 8.030 49.950 8.290 ;
        RECT 50.010 8.030 50.270 8.290 ;
        RECT 50.330 8.030 50.590 8.290 ;
        RECT -10.570 2.590 -10.310 2.850 ;
        RECT -10.250 2.590 -9.990 2.850 ;
        RECT -9.930 2.590 -9.670 2.850 ;
        RECT -9.610 2.590 -9.350 2.850 ;
        RECT -9.290 2.590 -9.030 2.850 ;
        RECT -8.970 2.590 -8.710 2.850 ;
        RECT -8.650 2.590 -8.390 2.850 ;
        RECT -8.330 2.590 -8.070 2.850 ;
        RECT -8.010 2.590 -7.750 2.850 ;
        RECT -7.690 2.590 -7.430 2.850 ;
        RECT -7.370 2.590 -7.110 2.850 ;
        RECT -7.050 2.590 -6.790 2.850 ;
        RECT -6.730 2.590 -6.470 2.850 ;
        RECT 27.750 2.590 28.010 2.850 ;
        RECT 28.070 2.590 28.330 2.850 ;
        RECT 28.390 2.590 28.650 2.850 ;
        RECT 28.710 2.590 28.970 2.850 ;
        RECT 29.030 2.590 29.290 2.850 ;
        RECT 46.490 2.590 46.750 2.850 ;
        RECT 46.810 2.590 47.070 2.850 ;
        RECT 47.130 2.590 47.390 2.850 ;
        RECT 47.450 2.590 47.710 2.850 ;
        RECT 47.770 2.590 48.030 2.850 ;
        RECT 48.090 2.590 48.350 2.850 ;
        RECT 48.410 2.590 48.670 2.850 ;
        RECT 48.730 2.590 48.990 2.850 ;
        RECT 49.050 2.590 49.310 2.850 ;
        RECT 49.370 2.590 49.630 2.850 ;
        RECT 49.690 2.590 49.950 2.850 ;
        RECT 50.010 2.590 50.270 2.850 ;
        RECT 50.330 2.590 50.590 2.850 ;
      LAYER met2 ;
        RECT -10.570 35.120 -6.470 35.600 ;
        RECT 27.750 35.120 29.290 35.600 ;
        RECT 46.490 35.120 50.590 35.600 ;
        RECT -10.570 29.680 -6.470 30.160 ;
        RECT 27.750 29.680 29.290 30.160 ;
        RECT 46.490 29.680 50.590 30.160 ;
        RECT -10.570 24.240 -6.470 24.720 ;
        RECT 27.750 24.240 29.290 24.720 ;
        RECT 46.490 24.240 50.590 24.720 ;
        RECT -10.570 18.800 -6.470 19.280 ;
        RECT 27.750 18.800 29.290 19.280 ;
        RECT 46.490 18.800 50.590 19.280 ;
        RECT -10.570 13.360 -6.470 13.840 ;
        RECT 27.750 13.360 29.290 13.840 ;
        RECT 46.490 13.360 50.590 13.840 ;
        RECT -10.570 7.920 -6.470 8.400 ;
        RECT 27.750 7.920 29.290 8.400 ;
        RECT 46.490 7.920 50.590 8.400 ;
        RECT -10.570 2.480 -6.470 2.960 ;
        RECT 27.750 2.480 29.290 2.960 ;
        RECT 46.490 2.480 50.590 2.960 ;
      LAYER via2 ;
        RECT -10.460 35.220 -10.180 35.500 ;
        RECT -10.060 35.220 -9.780 35.500 ;
        RECT -9.660 35.220 -9.380 35.500 ;
        RECT -9.260 35.220 -8.980 35.500 ;
        RECT -8.860 35.220 -8.580 35.500 ;
        RECT -8.460 35.220 -8.180 35.500 ;
        RECT -8.060 35.220 -7.780 35.500 ;
        RECT -7.660 35.220 -7.380 35.500 ;
        RECT -7.260 35.220 -6.980 35.500 ;
        RECT -6.860 35.220 -6.580 35.500 ;
        RECT 27.780 35.220 28.060 35.500 ;
        RECT 28.180 35.220 28.460 35.500 ;
        RECT 28.580 35.220 28.860 35.500 ;
        RECT 28.980 35.220 29.260 35.500 ;
        RECT 46.600 35.220 46.880 35.500 ;
        RECT 47.000 35.220 47.280 35.500 ;
        RECT 47.400 35.220 47.680 35.500 ;
        RECT 47.800 35.220 48.080 35.500 ;
        RECT 48.200 35.220 48.480 35.500 ;
        RECT 48.600 35.220 48.880 35.500 ;
        RECT 49.000 35.220 49.280 35.500 ;
        RECT 49.400 35.220 49.680 35.500 ;
        RECT 49.800 35.220 50.080 35.500 ;
        RECT 50.200 35.220 50.480 35.500 ;
        RECT -10.460 29.780 -10.180 30.060 ;
        RECT -10.060 29.780 -9.780 30.060 ;
        RECT -9.660 29.780 -9.380 30.060 ;
        RECT -9.260 29.780 -8.980 30.060 ;
        RECT -8.860 29.780 -8.580 30.060 ;
        RECT -8.460 29.780 -8.180 30.060 ;
        RECT -8.060 29.780 -7.780 30.060 ;
        RECT -7.660 29.780 -7.380 30.060 ;
        RECT -7.260 29.780 -6.980 30.060 ;
        RECT -6.860 29.780 -6.580 30.060 ;
        RECT 27.780 29.780 28.060 30.060 ;
        RECT 28.180 29.780 28.460 30.060 ;
        RECT 28.580 29.780 28.860 30.060 ;
        RECT 28.980 29.780 29.260 30.060 ;
        RECT 46.600 29.780 46.880 30.060 ;
        RECT 47.000 29.780 47.280 30.060 ;
        RECT 47.400 29.780 47.680 30.060 ;
        RECT 47.800 29.780 48.080 30.060 ;
        RECT 48.200 29.780 48.480 30.060 ;
        RECT 48.600 29.780 48.880 30.060 ;
        RECT 49.000 29.780 49.280 30.060 ;
        RECT 49.400 29.780 49.680 30.060 ;
        RECT 49.800 29.780 50.080 30.060 ;
        RECT 50.200 29.780 50.480 30.060 ;
        RECT -10.460 24.340 -10.180 24.620 ;
        RECT -10.060 24.340 -9.780 24.620 ;
        RECT -9.660 24.340 -9.380 24.620 ;
        RECT -9.260 24.340 -8.980 24.620 ;
        RECT -8.860 24.340 -8.580 24.620 ;
        RECT -8.460 24.340 -8.180 24.620 ;
        RECT -8.060 24.340 -7.780 24.620 ;
        RECT -7.660 24.340 -7.380 24.620 ;
        RECT -7.260 24.340 -6.980 24.620 ;
        RECT -6.860 24.340 -6.580 24.620 ;
        RECT 27.780 24.340 28.060 24.620 ;
        RECT 28.180 24.340 28.460 24.620 ;
        RECT 28.580 24.340 28.860 24.620 ;
        RECT 28.980 24.340 29.260 24.620 ;
        RECT 46.600 24.340 46.880 24.620 ;
        RECT 47.000 24.340 47.280 24.620 ;
        RECT 47.400 24.340 47.680 24.620 ;
        RECT 47.800 24.340 48.080 24.620 ;
        RECT 48.200 24.340 48.480 24.620 ;
        RECT 48.600 24.340 48.880 24.620 ;
        RECT 49.000 24.340 49.280 24.620 ;
        RECT 49.400 24.340 49.680 24.620 ;
        RECT 49.800 24.340 50.080 24.620 ;
        RECT 50.200 24.340 50.480 24.620 ;
        RECT -10.460 18.900 -10.180 19.180 ;
        RECT -10.060 18.900 -9.780 19.180 ;
        RECT -9.660 18.900 -9.380 19.180 ;
        RECT -9.260 18.900 -8.980 19.180 ;
        RECT -8.860 18.900 -8.580 19.180 ;
        RECT -8.460 18.900 -8.180 19.180 ;
        RECT -8.060 18.900 -7.780 19.180 ;
        RECT -7.660 18.900 -7.380 19.180 ;
        RECT -7.260 18.900 -6.980 19.180 ;
        RECT -6.860 18.900 -6.580 19.180 ;
        RECT 27.780 18.900 28.060 19.180 ;
        RECT 28.180 18.900 28.460 19.180 ;
        RECT 28.580 18.900 28.860 19.180 ;
        RECT 28.980 18.900 29.260 19.180 ;
        RECT 46.600 18.900 46.880 19.180 ;
        RECT 47.000 18.900 47.280 19.180 ;
        RECT 47.400 18.900 47.680 19.180 ;
        RECT 47.800 18.900 48.080 19.180 ;
        RECT 48.200 18.900 48.480 19.180 ;
        RECT 48.600 18.900 48.880 19.180 ;
        RECT 49.000 18.900 49.280 19.180 ;
        RECT 49.400 18.900 49.680 19.180 ;
        RECT 49.800 18.900 50.080 19.180 ;
        RECT 50.200 18.900 50.480 19.180 ;
        RECT -10.460 13.460 -10.180 13.740 ;
        RECT -10.060 13.460 -9.780 13.740 ;
        RECT -9.660 13.460 -9.380 13.740 ;
        RECT -9.260 13.460 -8.980 13.740 ;
        RECT -8.860 13.460 -8.580 13.740 ;
        RECT -8.460 13.460 -8.180 13.740 ;
        RECT -8.060 13.460 -7.780 13.740 ;
        RECT -7.660 13.460 -7.380 13.740 ;
        RECT -7.260 13.460 -6.980 13.740 ;
        RECT -6.860 13.460 -6.580 13.740 ;
        RECT 27.780 13.460 28.060 13.740 ;
        RECT 28.180 13.460 28.460 13.740 ;
        RECT 28.580 13.460 28.860 13.740 ;
        RECT 28.980 13.460 29.260 13.740 ;
        RECT 46.600 13.460 46.880 13.740 ;
        RECT 47.000 13.460 47.280 13.740 ;
        RECT 47.400 13.460 47.680 13.740 ;
        RECT 47.800 13.460 48.080 13.740 ;
        RECT 48.200 13.460 48.480 13.740 ;
        RECT 48.600 13.460 48.880 13.740 ;
        RECT 49.000 13.460 49.280 13.740 ;
        RECT 49.400 13.460 49.680 13.740 ;
        RECT 49.800 13.460 50.080 13.740 ;
        RECT 50.200 13.460 50.480 13.740 ;
        RECT -10.460 8.020 -10.180 8.300 ;
        RECT -10.060 8.020 -9.780 8.300 ;
        RECT -9.660 8.020 -9.380 8.300 ;
        RECT -9.260 8.020 -8.980 8.300 ;
        RECT -8.860 8.020 -8.580 8.300 ;
        RECT -8.460 8.020 -8.180 8.300 ;
        RECT -8.060 8.020 -7.780 8.300 ;
        RECT -7.660 8.020 -7.380 8.300 ;
        RECT -7.260 8.020 -6.980 8.300 ;
        RECT -6.860 8.020 -6.580 8.300 ;
        RECT 27.780 8.020 28.060 8.300 ;
        RECT 28.180 8.020 28.460 8.300 ;
        RECT 28.580 8.020 28.860 8.300 ;
        RECT 28.980 8.020 29.260 8.300 ;
        RECT 46.600 8.020 46.880 8.300 ;
        RECT 47.000 8.020 47.280 8.300 ;
        RECT 47.400 8.020 47.680 8.300 ;
        RECT 47.800 8.020 48.080 8.300 ;
        RECT 48.200 8.020 48.480 8.300 ;
        RECT 48.600 8.020 48.880 8.300 ;
        RECT 49.000 8.020 49.280 8.300 ;
        RECT 49.400 8.020 49.680 8.300 ;
        RECT 49.800 8.020 50.080 8.300 ;
        RECT 50.200 8.020 50.480 8.300 ;
        RECT -10.460 2.580 -10.180 2.860 ;
        RECT -10.060 2.580 -9.780 2.860 ;
        RECT -9.660 2.580 -9.380 2.860 ;
        RECT -9.260 2.580 -8.980 2.860 ;
        RECT -8.860 2.580 -8.580 2.860 ;
        RECT -8.460 2.580 -8.180 2.860 ;
        RECT -8.060 2.580 -7.780 2.860 ;
        RECT -7.660 2.580 -7.380 2.860 ;
        RECT -7.260 2.580 -6.980 2.860 ;
        RECT -6.860 2.580 -6.580 2.860 ;
        RECT 27.780 2.580 28.060 2.860 ;
        RECT 28.180 2.580 28.460 2.860 ;
        RECT 28.580 2.580 28.860 2.860 ;
        RECT 28.980 2.580 29.260 2.860 ;
        RECT 46.600 2.580 46.880 2.860 ;
        RECT 47.000 2.580 47.280 2.860 ;
        RECT 47.400 2.580 47.680 2.860 ;
        RECT 47.800 2.580 48.080 2.860 ;
        RECT 48.200 2.580 48.480 2.860 ;
        RECT 48.600 2.580 48.880 2.860 ;
        RECT 49.000 2.580 49.280 2.860 ;
        RECT 49.400 2.580 49.680 2.860 ;
        RECT 49.800 2.580 50.080 2.860 ;
        RECT 50.200 2.580 50.480 2.860 ;
      LAYER met3 ;
        RECT -10.620 35.195 -6.420 35.525 ;
        RECT 27.720 35.195 29.320 35.525 ;
        RECT 46.440 35.195 50.640 35.525 ;
        RECT -10.620 29.755 -6.420 30.085 ;
        RECT 27.720 29.755 29.320 30.085 ;
        RECT 46.440 29.755 50.640 30.085 ;
        RECT -10.620 24.315 -6.420 24.645 ;
        RECT 27.720 24.315 29.320 24.645 ;
        RECT 46.440 24.315 50.640 24.645 ;
        RECT -10.620 18.875 -6.420 19.205 ;
        RECT 27.720 18.875 29.320 19.205 ;
        RECT 46.440 18.875 50.640 19.205 ;
        RECT -10.620 13.435 -6.420 13.765 ;
        RECT 27.720 13.435 29.320 13.765 ;
        RECT 46.440 13.435 50.640 13.765 ;
        RECT -10.620 7.995 -6.420 8.325 ;
        RECT 27.720 7.995 29.320 8.325 ;
        RECT 46.440 7.995 50.640 8.325 ;
        RECT -10.620 2.555 -6.420 2.885 ;
        RECT 27.720 2.555 29.320 2.885 ;
        RECT 46.440 2.555 50.640 2.885 ;
      LAYER via3 ;
        RECT -10.480 35.200 -10.160 35.520 ;
        RECT -10.080 35.200 -9.760 35.520 ;
        RECT -9.680 35.200 -9.360 35.520 ;
        RECT -9.280 35.200 -8.960 35.520 ;
        RECT -8.880 35.200 -8.560 35.520 ;
        RECT -8.480 35.200 -8.160 35.520 ;
        RECT -8.080 35.200 -7.760 35.520 ;
        RECT -7.680 35.200 -7.360 35.520 ;
        RECT -7.280 35.200 -6.960 35.520 ;
        RECT -6.880 35.200 -6.560 35.520 ;
        RECT 27.760 35.200 28.080 35.520 ;
        RECT 28.160 35.200 28.480 35.520 ;
        RECT 28.560 35.200 28.880 35.520 ;
        RECT 28.960 35.200 29.280 35.520 ;
        RECT 46.580 35.200 46.900 35.520 ;
        RECT 46.980 35.200 47.300 35.520 ;
        RECT 47.380 35.200 47.700 35.520 ;
        RECT 47.780 35.200 48.100 35.520 ;
        RECT 48.180 35.200 48.500 35.520 ;
        RECT 48.580 35.200 48.900 35.520 ;
        RECT 48.980 35.200 49.300 35.520 ;
        RECT 49.380 35.200 49.700 35.520 ;
        RECT 49.780 35.200 50.100 35.520 ;
        RECT 50.180 35.200 50.500 35.520 ;
        RECT -10.480 29.760 -10.160 30.080 ;
        RECT -10.080 29.760 -9.760 30.080 ;
        RECT -9.680 29.760 -9.360 30.080 ;
        RECT -9.280 29.760 -8.960 30.080 ;
        RECT -8.880 29.760 -8.560 30.080 ;
        RECT -8.480 29.760 -8.160 30.080 ;
        RECT -8.080 29.760 -7.760 30.080 ;
        RECT -7.680 29.760 -7.360 30.080 ;
        RECT -7.280 29.760 -6.960 30.080 ;
        RECT -6.880 29.760 -6.560 30.080 ;
        RECT 27.760 29.760 28.080 30.080 ;
        RECT 28.160 29.760 28.480 30.080 ;
        RECT 28.560 29.760 28.880 30.080 ;
        RECT 28.960 29.760 29.280 30.080 ;
        RECT 46.580 29.760 46.900 30.080 ;
        RECT 46.980 29.760 47.300 30.080 ;
        RECT 47.380 29.760 47.700 30.080 ;
        RECT 47.780 29.760 48.100 30.080 ;
        RECT 48.180 29.760 48.500 30.080 ;
        RECT 48.580 29.760 48.900 30.080 ;
        RECT 48.980 29.760 49.300 30.080 ;
        RECT 49.380 29.760 49.700 30.080 ;
        RECT 49.780 29.760 50.100 30.080 ;
        RECT 50.180 29.760 50.500 30.080 ;
        RECT -10.480 24.320 -10.160 24.640 ;
        RECT -10.080 24.320 -9.760 24.640 ;
        RECT -9.680 24.320 -9.360 24.640 ;
        RECT -9.280 24.320 -8.960 24.640 ;
        RECT -8.880 24.320 -8.560 24.640 ;
        RECT -8.480 24.320 -8.160 24.640 ;
        RECT -8.080 24.320 -7.760 24.640 ;
        RECT -7.680 24.320 -7.360 24.640 ;
        RECT -7.280 24.320 -6.960 24.640 ;
        RECT -6.880 24.320 -6.560 24.640 ;
        RECT 27.760 24.320 28.080 24.640 ;
        RECT 28.160 24.320 28.480 24.640 ;
        RECT 28.560 24.320 28.880 24.640 ;
        RECT 28.960 24.320 29.280 24.640 ;
        RECT 46.580 24.320 46.900 24.640 ;
        RECT 46.980 24.320 47.300 24.640 ;
        RECT 47.380 24.320 47.700 24.640 ;
        RECT 47.780 24.320 48.100 24.640 ;
        RECT 48.180 24.320 48.500 24.640 ;
        RECT 48.580 24.320 48.900 24.640 ;
        RECT 48.980 24.320 49.300 24.640 ;
        RECT 49.380 24.320 49.700 24.640 ;
        RECT 49.780 24.320 50.100 24.640 ;
        RECT 50.180 24.320 50.500 24.640 ;
        RECT -10.480 18.880 -10.160 19.200 ;
        RECT -10.080 18.880 -9.760 19.200 ;
        RECT -9.680 18.880 -9.360 19.200 ;
        RECT -9.280 18.880 -8.960 19.200 ;
        RECT -8.880 18.880 -8.560 19.200 ;
        RECT -8.480 18.880 -8.160 19.200 ;
        RECT -8.080 18.880 -7.760 19.200 ;
        RECT -7.680 18.880 -7.360 19.200 ;
        RECT -7.280 18.880 -6.960 19.200 ;
        RECT -6.880 18.880 -6.560 19.200 ;
        RECT 27.760 18.880 28.080 19.200 ;
        RECT 28.160 18.880 28.480 19.200 ;
        RECT 28.560 18.880 28.880 19.200 ;
        RECT 28.960 18.880 29.280 19.200 ;
        RECT 46.580 18.880 46.900 19.200 ;
        RECT 46.980 18.880 47.300 19.200 ;
        RECT 47.380 18.880 47.700 19.200 ;
        RECT 47.780 18.880 48.100 19.200 ;
        RECT 48.180 18.880 48.500 19.200 ;
        RECT 48.580 18.880 48.900 19.200 ;
        RECT 48.980 18.880 49.300 19.200 ;
        RECT 49.380 18.880 49.700 19.200 ;
        RECT 49.780 18.880 50.100 19.200 ;
        RECT 50.180 18.880 50.500 19.200 ;
        RECT -10.480 13.440 -10.160 13.760 ;
        RECT -10.080 13.440 -9.760 13.760 ;
        RECT -9.680 13.440 -9.360 13.760 ;
        RECT -9.280 13.440 -8.960 13.760 ;
        RECT -8.880 13.440 -8.560 13.760 ;
        RECT -8.480 13.440 -8.160 13.760 ;
        RECT -8.080 13.440 -7.760 13.760 ;
        RECT -7.680 13.440 -7.360 13.760 ;
        RECT -7.280 13.440 -6.960 13.760 ;
        RECT -6.880 13.440 -6.560 13.760 ;
        RECT 27.760 13.440 28.080 13.760 ;
        RECT 28.160 13.440 28.480 13.760 ;
        RECT 28.560 13.440 28.880 13.760 ;
        RECT 28.960 13.440 29.280 13.760 ;
        RECT 46.580 13.440 46.900 13.760 ;
        RECT 46.980 13.440 47.300 13.760 ;
        RECT 47.380 13.440 47.700 13.760 ;
        RECT 47.780 13.440 48.100 13.760 ;
        RECT 48.180 13.440 48.500 13.760 ;
        RECT 48.580 13.440 48.900 13.760 ;
        RECT 48.980 13.440 49.300 13.760 ;
        RECT 49.380 13.440 49.700 13.760 ;
        RECT 49.780 13.440 50.100 13.760 ;
        RECT 50.180 13.440 50.500 13.760 ;
        RECT -10.480 8.000 -10.160 8.320 ;
        RECT -10.080 8.000 -9.760 8.320 ;
        RECT -9.680 8.000 -9.360 8.320 ;
        RECT -9.280 8.000 -8.960 8.320 ;
        RECT -8.880 8.000 -8.560 8.320 ;
        RECT -8.480 8.000 -8.160 8.320 ;
        RECT -8.080 8.000 -7.760 8.320 ;
        RECT -7.680 8.000 -7.360 8.320 ;
        RECT -7.280 8.000 -6.960 8.320 ;
        RECT -6.880 8.000 -6.560 8.320 ;
        RECT 27.760 8.000 28.080 8.320 ;
        RECT 28.160 8.000 28.480 8.320 ;
        RECT 28.560 8.000 28.880 8.320 ;
        RECT 28.960 8.000 29.280 8.320 ;
        RECT 46.580 8.000 46.900 8.320 ;
        RECT 46.980 8.000 47.300 8.320 ;
        RECT 47.380 8.000 47.700 8.320 ;
        RECT 47.780 8.000 48.100 8.320 ;
        RECT 48.180 8.000 48.500 8.320 ;
        RECT 48.580 8.000 48.900 8.320 ;
        RECT 48.980 8.000 49.300 8.320 ;
        RECT 49.380 8.000 49.700 8.320 ;
        RECT 49.780 8.000 50.100 8.320 ;
        RECT 50.180 8.000 50.500 8.320 ;
        RECT -10.480 2.560 -10.160 2.880 ;
        RECT -10.080 2.560 -9.760 2.880 ;
        RECT -9.680 2.560 -9.360 2.880 ;
        RECT -9.280 2.560 -8.960 2.880 ;
        RECT -8.880 2.560 -8.560 2.880 ;
        RECT -8.480 2.560 -8.160 2.880 ;
        RECT -8.080 2.560 -7.760 2.880 ;
        RECT -7.680 2.560 -7.360 2.880 ;
        RECT -7.280 2.560 -6.960 2.880 ;
        RECT -6.880 2.560 -6.560 2.880 ;
        RECT 27.760 2.560 28.080 2.880 ;
        RECT 28.160 2.560 28.480 2.880 ;
        RECT 28.560 2.560 28.880 2.880 ;
        RECT 28.960 2.560 29.280 2.880 ;
        RECT 46.580 2.560 46.900 2.880 ;
        RECT 46.980 2.560 47.300 2.880 ;
        RECT 47.380 2.560 47.700 2.880 ;
        RECT 47.780 2.560 48.100 2.880 ;
        RECT 48.180 2.560 48.500 2.880 ;
        RECT 48.580 2.560 48.900 2.880 ;
        RECT 48.980 2.560 49.300 2.880 ;
        RECT 49.380 2.560 49.700 2.880 ;
        RECT 49.780 2.560 50.100 2.880 ;
        RECT 50.180 2.560 50.500 2.880 ;
      LAYER met4 ;
        RECT -10.620 -9.280 -6.420 50.080 ;
        RECT 27.720 -9.280 29.320 50.080 ;
        RECT 46.440 -9.280 50.640 50.080 ;
      LAYER via4 ;
        RECT -9.910 46.590 -7.130 49.370 ;
        RECT -9.910 29.090 -8.730 30.270 ;
        RECT -8.310 29.090 -7.130 30.270 ;
        RECT -9.910 -8.570 -7.130 -5.790 ;
        RECT 27.930 48.190 29.110 49.370 ;
        RECT 27.930 46.590 29.110 47.770 ;
        RECT 27.930 29.090 29.110 30.270 ;
        RECT 27.930 -6.970 29.110 -5.790 ;
        RECT 27.930 -8.570 29.110 -7.390 ;
        RECT 47.150 46.590 49.930 49.370 ;
        RECT 47.150 29.090 48.330 30.270 ;
        RECT 48.750 29.090 49.930 30.270 ;
        RECT 47.150 -8.570 49.930 -5.790 ;
      LAYER met5 ;
        RECT -10.620 45.880 50.640 50.080 ;
        RECT -10.620 28.880 50.640 30.480 ;
        RECT -10.620 -9.280 50.640 -5.080 ;
    END
  END VGND
  PIN clk
    ANTENNAGATEAREA 0.318000 ;
    PORT
      LAYER li1 ;
        RECT 34.525 20.015 34.875 20.665 ;
        RECT 34.525 14.575 34.875 15.225 ;
      LAYER mcon ;
        RECT 34.645 20.485 34.815 20.655 ;
        RECT 34.645 15.045 34.815 15.215 ;
      LAYER met1 ;
        RECT 34.570 20.640 34.890 20.700 ;
        RECT 34.375 20.500 34.890 20.640 ;
        RECT 34.570 20.440 34.890 20.500 ;
        RECT 34.570 15.200 34.890 15.260 ;
        RECT 34.375 15.060 34.890 15.200 ;
        RECT 34.570 15.000 34.890 15.060 ;
      LAYER via ;
        RECT 34.600 20.440 34.860 20.700 ;
        RECT 34.600 15.000 34.860 15.260 ;
      LAYER met2 ;
        RECT 34.590 21.915 34.870 22.285 ;
        RECT 34.660 20.730 34.800 21.915 ;
        RECT 34.600 20.410 34.860 20.730 ;
        RECT 34.660 15.290 34.800 20.410 ;
        RECT 34.600 14.970 34.860 15.290 ;
      LAYER via2 ;
        RECT 34.590 21.960 34.870 22.240 ;
      LAYER met3 ;
        RECT 34.565 22.250 34.895 22.265 ;
        RECT 34.565 21.950 40.000 22.250 ;
        RECT 34.565 21.935 34.895 21.950 ;
    END
  END clk
  PIN control
    ANTENNAGATEAREA 0.495000 ;
    PORT
      LAYER li1 ;
        RECT 32.995 31.365 34.535 31.535 ;
        RECT 32.995 31.165 33.165 31.365 ;
        RECT 32.565 30.995 33.165 31.165 ;
        RECT 34.290 30.915 34.535 31.365 ;
      LAYER mcon ;
        RECT 34.185 31.365 34.355 31.535 ;
      LAYER met1 ;
        RECT 34.110 31.520 34.430 31.580 ;
        RECT 33.915 31.380 34.430 31.520 ;
        RECT 34.110 31.320 34.430 31.380 ;
      LAYER via ;
        RECT 34.140 31.320 34.400 31.580 ;
      LAYER met2 ;
        RECT 34.130 34.155 34.410 34.525 ;
        RECT 34.200 31.610 34.340 34.155 ;
        RECT 34.140 31.290 34.400 31.610 ;
      LAYER via2 ;
        RECT 34.130 34.200 34.410 34.480 ;
      LAYER met3 ;
        RECT 34.105 34.490 34.435 34.505 ;
        RECT 34.105 34.190 40.000 34.490 ;
        RECT 34.105 34.175 34.435 34.190 ;
    END
  END control
  PIN seed[2]
    PORT
      LAYER met3 ;
        RECT 0.000 11.070 0.800 11.370 ;
    END
  END seed[2]
  PIN seed[3]
    PORT
      LAYER met3 ;
        RECT 0.000 23.310 0.800 23.610 ;
    END
  END seed[3]
  PIN seed[6]
    PORT
      LAYER met3 ;
        RECT 0.000 35.550 0.800 35.850 ;
    END
  END seed[6]
  PIN seed[8]
    PORT
      LAYER met3 ;
        RECT 39.200 11.070 40.000 11.370 ;
    END
  END seed[8]
  PIN clk0
    ANTENNADIFFAREA 0.336000 ;
    PORT
      LAYER li1 ;
        RECT 31.815 4.010 32.145 5.185 ;
        RECT 31.365 3.480 32.145 4.010 ;
        RECT 31.820 2.975 32.145 3.480 ;
      LAYER mcon ;
        RECT 31.425 3.485 31.595 3.655 ;
      LAYER met1 ;
        RECT 31.350 3.640 31.670 3.700 ;
        RECT 31.155 3.500 31.670 3.640 ;
        RECT 31.350 3.440 31.670 3.500 ;
      LAYER via ;
        RECT 31.380 3.440 31.640 3.700 ;
      LAYER met2 ;
        RECT 31.380 3.410 31.640 3.730 ;
        RECT 31.440 0.000 31.580 3.410 ;
    END
  END clk0
  PIN clk0b
    ANTENNADIFFAREA 0.336000 ;
    PORT
      LAYER li1 ;
        RECT 6.060 34.600 6.385 35.105 ;
        RECT 5.605 34.070 6.385 34.600 ;
        RECT 6.055 32.895 6.385 34.070 ;
      LAYER mcon ;
        RECT 5.665 34.425 5.835 34.595 ;
      LAYER met1 ;
        RECT 3.750 34.580 4.070 34.640 ;
        RECT 5.605 34.580 5.895 34.625 ;
        RECT 3.750 34.440 5.895 34.580 ;
        RECT 3.750 34.380 4.070 34.440 ;
        RECT 5.605 34.395 5.895 34.440 ;
      LAYER via ;
        RECT 3.780 34.380 4.040 34.640 ;
      LAYER met2 ;
        RECT 3.840 34.670 3.980 40.000 ;
        RECT 3.780 34.350 4.040 34.670 ;
    END
  END clk0b
  PIN clk1
    ANTENNADIFFAREA 0.336000 ;
    PORT
      LAYER li1 ;
        RECT 24.895 36.650 25.225 37.825 ;
        RECT 24.895 36.120 25.675 36.650 ;
        RECT 24.895 35.615 25.220 36.120 ;
      LAYER mcon ;
        RECT 24.985 37.485 25.155 37.655 ;
      LAYER met1 ;
        RECT 24.925 37.640 25.215 37.685 ;
        RECT 27.210 37.640 27.530 37.700 ;
        RECT 24.925 37.500 27.530 37.640 ;
        RECT 24.925 37.455 25.215 37.500 ;
        RECT 27.210 37.440 27.530 37.500 ;
      LAYER via ;
        RECT 27.240 37.440 27.500 37.700 ;
      LAYER met2 ;
        RECT 27.760 37.810 27.900 40.000 ;
        RECT 27.300 37.730 27.900 37.810 ;
        RECT 27.240 37.670 27.900 37.730 ;
        RECT 27.240 37.410 27.500 37.670 ;
    END
  END clk1
  PIN clk1b
    ANTENNADIFFAREA 0.336000 ;
    PORT
      LAYER li1 ;
        RECT 25.355 34.600 25.680 35.105 ;
        RECT 25.355 34.070 26.135 34.600 ;
        RECT 25.355 32.895 25.685 34.070 ;
      LAYER mcon ;
        RECT 25.445 34.085 25.615 34.255 ;
      LAYER met1 ;
        RECT 20.770 34.240 21.090 34.300 ;
        RECT 25.385 34.240 25.675 34.285 ;
        RECT 20.770 34.100 25.675 34.240 ;
        RECT 20.770 34.040 21.090 34.100 ;
        RECT 25.385 34.055 25.675 34.100 ;
      LAYER via ;
        RECT 20.800 34.040 21.060 34.300 ;
      LAYER met2 ;
        RECT 20.400 34.410 20.540 40.000 ;
        RECT 20.400 34.330 21.000 34.410 ;
        RECT 20.400 34.270 21.060 34.330 ;
        RECT 20.800 34.010 21.060 34.270 ;
    END
  END clk1b
  PIN clk_in
    ANTENNAGATEAREA 0.315000 ;
    PORT
      LAYER li1 ;
        RECT 5.145 3.095 5.385 4.045 ;
      LAYER mcon ;
        RECT 5.205 3.145 5.375 3.315 ;
      LAYER met1 ;
        RECT 0.070 3.300 0.390 3.360 ;
        RECT 5.145 3.300 5.435 3.345 ;
        RECT 0.070 3.160 5.435 3.300 ;
        RECT 0.070 3.100 0.390 3.160 ;
        RECT 5.145 3.115 5.435 3.160 ;
      LAYER via ;
        RECT 0.100 3.100 0.360 3.360 ;
      LAYER met2 ;
        RECT 0.100 3.070 0.360 3.390 ;
        RECT 0.160 0.000 0.300 3.070 ;
    END
  END clk_in
  PIN rst_n
    ANTENNAGATEAREA 0.504000 ;
    PORT
      LAYER li1 ;
        RECT 27.950 20.045 28.300 20.105 ;
        RECT 27.620 19.775 28.300 20.045 ;
        RECT 30.940 19.775 31.350 20.105 ;
        RECT 27.950 14.605 28.300 14.665 ;
        RECT 27.620 14.335 28.300 14.605 ;
        RECT 30.940 14.335 31.350 14.665 ;
      LAYER mcon ;
        RECT 27.745 19.805 27.915 19.975 ;
        RECT 30.965 19.805 31.135 19.975 ;
        RECT 27.745 14.365 27.915 14.535 ;
        RECT 30.965 14.365 31.135 14.535 ;
      LAYER met1 ;
        RECT 27.210 19.960 27.530 20.020 ;
        RECT 27.685 19.960 27.975 20.005 ;
        RECT 30.905 19.960 31.195 20.005 ;
        RECT 27.210 19.820 31.195 19.960 ;
        RECT 27.210 19.760 27.530 19.820 ;
        RECT 27.685 19.775 27.975 19.820 ;
        RECT 30.905 19.775 31.195 19.820 ;
        RECT 23.990 14.520 24.310 14.580 ;
        RECT 27.210 14.520 27.530 14.580 ;
        RECT 27.685 14.520 27.975 14.565 ;
        RECT 30.905 14.520 31.195 14.565 ;
        RECT 23.990 14.380 31.195 14.520 ;
        RECT 23.990 14.320 24.310 14.380 ;
        RECT 27.210 14.320 27.530 14.380 ;
        RECT 27.685 14.335 27.975 14.380 ;
        RECT 30.905 14.335 31.195 14.380 ;
      LAYER via ;
        RECT 27.240 19.760 27.500 20.020 ;
        RECT 24.020 14.320 24.280 14.580 ;
        RECT 27.240 14.320 27.500 14.580 ;
      LAYER met2 ;
        RECT 27.240 19.730 27.500 20.050 ;
        RECT 27.300 14.610 27.440 19.730 ;
        RECT 24.020 14.290 24.280 14.610 ;
        RECT 27.240 14.290 27.500 14.610 ;
        RECT 24.080 0.000 24.220 14.290 ;
    END
  END rst_n
  PIN seed[0]
    PORT
      LAYER met2 ;
        RECT 7.520 0.000 7.660 0.485 ;
    END
  END seed[0]
  PIN seed[1]
    PORT
      LAYER met2 ;
        RECT 39.720 0.000 39.860 0.485 ;
    END
  END seed[1]
  PIN seed[4]
    PORT
      LAYER met2 ;
        RECT 36.040 39.515 36.180 40.000 ;
    END
  END seed[4]
  PIN seed[5]
    PORT
      LAYER met2 ;
        RECT 15.800 0.000 15.940 0.485 ;
    END
  END seed[5]
  PIN seed[7]
    PORT
      LAYER met2 ;
        RECT 12.120 39.515 12.260 40.000 ;
    END
  END seed[7]
  OBS
      LAYER pwell ;
        RECT 1.385 35.465 3.215 36.275 ;
        RECT 1.525 35.255 1.695 35.465 ;
        RECT 3.395 35.410 3.505 35.420 ;
        RECT 1.385 34.445 3.215 35.255 ;
        RECT 3.350 35.240 3.570 35.410 ;
        RECT 5.200 35.305 5.320 35.415 ;
        RECT 6.585 35.275 6.755 35.445 ;
        RECT 5.525 34.575 6.480 35.255 ;
        RECT 7.030 35.240 7.250 35.480 ;
        RECT 10.710 35.240 10.930 35.480 ;
        RECT 14.390 35.310 14.610 35.480 ;
        RECT 15.770 35.240 15.990 35.410 ;
        RECT 18.070 35.310 18.290 35.480 ;
        RECT 24.800 35.465 25.755 36.145 ;
        RECT 19.450 35.240 19.670 35.410 ;
        RECT 22.685 35.275 22.855 35.445 ;
        RECT 23.155 35.310 23.315 35.420 ;
        RECT 23.175 35.300 23.285 35.310 ;
        RECT 24.060 35.305 24.180 35.415 ;
        RECT 24.525 35.275 24.695 35.445 ;
        RECT 24.985 35.275 25.155 35.445 ;
        RECT 25.935 35.300 26.045 35.420 ;
        RECT 26.395 35.300 26.505 35.420 ;
        RECT 27.755 35.310 27.915 35.420 ;
        RECT 28.215 35.300 28.375 35.410 ;
        RECT 28.660 35.305 28.780 35.415 ;
        RECT 21.625 34.575 22.580 35.255 ;
        RECT 25.260 34.575 26.215 35.255 ;
        RECT 29.570 35.240 29.790 35.480 ;
        RECT 33.250 35.240 33.470 35.480 ;
        RECT 36.805 35.465 38.635 36.275 ;
        RECT 38.325 35.255 38.495 35.465 ;
        RECT 36.805 34.445 38.635 35.255 ;
        RECT 1.385 30.025 3.215 30.835 ;
        RECT 1.525 29.815 1.695 30.025 ;
        RECT 1.385 29.005 3.215 29.815 ;
        RECT 3.350 29.800 3.570 30.040 ;
        RECT 7.030 29.800 7.250 30.040 ;
        RECT 10.710 29.800 10.930 30.040 ;
        RECT 14.390 29.870 14.610 30.040 ;
        RECT 22.040 30.025 22.995 30.705 ;
        RECT 15.770 29.800 15.990 29.970 ;
        RECT 18.115 29.860 18.225 29.980 ;
        RECT 19.495 29.860 19.605 29.980 ;
        RECT 19.935 29.860 20.095 29.970 ;
        RECT 21.300 29.865 21.420 29.975 ;
        RECT 21.760 29.835 21.935 30.005 ;
        RECT 22.255 29.860 22.365 29.980 ;
        RECT 21.760 29.815 21.930 29.835 ;
        RECT 20.725 28.905 22.075 29.815 ;
        RECT 23.130 29.800 23.350 29.970 ;
        RECT 24.065 29.835 24.235 30.005 ;
        RECT 25.430 29.870 25.650 30.040 ;
        RECT 24.340 29.135 25.295 29.815 ;
        RECT 26.810 29.800 27.030 29.970 ;
        RECT 29.570 29.870 29.790 30.040 ;
        RECT 31.745 30.025 34.855 30.935 ;
        RECT 36.805 30.025 38.635 30.835 ;
        RECT 30.515 29.870 30.675 29.980 ;
        RECT 31.420 29.865 31.540 29.975 ;
        RECT 33.250 29.870 33.470 30.025 ;
        RECT 34.645 29.835 34.815 30.025 ;
        RECT 35.135 29.860 35.245 29.980 ;
        RECT 38.325 29.815 38.495 30.025 ;
        RECT 36.805 29.005 38.635 29.815 ;
        RECT 1.385 24.585 3.215 25.395 ;
        RECT 5.940 24.585 6.895 25.265 ;
        RECT 9.160 24.585 10.115 25.265 ;
        RECT 12.380 24.585 13.335 25.265 ;
        RECT 17.900 24.585 18.855 25.265 ;
        RECT 20.705 24.585 22.055 25.495 ;
        RECT 28.255 25.485 34.955 25.495 ;
        RECT 1.525 24.375 1.695 24.585 ;
        RECT 3.395 24.420 3.505 24.540 ;
        RECT 5.200 24.425 5.320 24.535 ;
        RECT 5.665 24.395 5.835 24.565 ;
        RECT 6.125 24.395 6.295 24.565 ;
        RECT 6.615 24.420 6.725 24.540 ;
        RECT 7.075 24.420 7.185 24.540 ;
        RECT 8.425 24.395 8.595 24.565 ;
        RECT 8.885 24.395 9.055 24.565 ;
        RECT 9.790 24.430 10.010 24.585 ;
        RECT 10.295 24.420 10.405 24.540 ;
        RECT 12.105 24.395 12.275 24.565 ;
        RECT 13.515 24.530 13.625 24.540 ;
        RECT 13.495 24.420 13.655 24.530 ;
        RECT 14.405 24.375 14.575 24.565 ;
        RECT 15.815 24.420 15.925 24.540 ;
        RECT 17.625 24.395 17.795 24.565 ;
        RECT 19.035 24.420 19.145 24.540 ;
        RECT 21.770 24.395 21.940 24.585 ;
        RECT 22.210 24.375 22.430 24.530 ;
        RECT 22.670 24.430 22.890 24.600 ;
        RECT 26.700 24.595 34.955 25.485 ;
        RECT 26.700 24.585 28.680 24.595 ;
        RECT 25.915 24.430 26.075 24.540 ;
        RECT 26.395 24.420 26.505 24.540 ;
        RECT 28.215 24.420 28.375 24.530 ;
        RECT 29.570 24.430 29.790 24.595 ;
        RECT 30.735 24.585 31.685 24.595 ;
        RECT 33.250 24.430 33.470 24.595 ;
        RECT 33.975 24.585 34.955 24.595 ;
        RECT 36.805 24.585 38.635 25.395 ;
        RECT 34.645 24.395 34.815 24.585 ;
        RECT 35.135 24.420 35.245 24.540 ;
        RECT 38.325 24.375 38.495 24.585 ;
        RECT 1.385 23.565 3.215 24.375 ;
        RECT 5.065 23.695 6.020 24.375 ;
        RECT 8.700 23.695 9.655 24.375 ;
        RECT 14.265 23.695 22.535 24.375 ;
        RECT 21.085 23.465 22.535 23.695 ;
        RECT 36.805 23.565 38.635 24.375 ;
        RECT 1.385 19.145 3.215 19.955 ;
        RECT 25.310 19.945 27.080 20.055 ;
        RECT 25.310 19.825 28.010 19.945 ;
        RECT 32.675 19.825 33.595 20.045 ;
        RECT 1.525 18.935 1.695 19.145 ;
        RECT 3.350 18.990 3.570 19.160 ;
        RECT 5.525 19.145 6.480 19.825 ;
        RECT 8.745 19.145 9.700 19.825 ;
        RECT 12.380 19.145 13.335 19.825 ;
        RECT 3.395 18.980 3.505 18.990 ;
        RECT 5.200 18.985 5.320 19.095 ;
        RECT 6.585 18.955 6.755 19.125 ;
        RECT 7.075 18.980 7.185 19.100 ;
        RECT 9.805 18.955 9.975 19.125 ;
        RECT 10.295 18.980 10.405 19.100 ;
        RECT 12.105 18.955 12.275 19.125 ;
        RECT 13.470 18.990 13.690 19.160 ;
        RECT 18.360 19.145 19.315 19.825 ;
        RECT 21.165 19.145 22.120 19.825 ;
        RECT 13.515 18.980 13.625 18.990 ;
        RECT 15.815 18.980 15.925 19.100 ;
        RECT 17.175 18.980 17.335 19.090 ;
        RECT 17.620 18.985 17.740 19.095 ;
        RECT 18.085 18.955 18.255 19.125 ;
        RECT 19.495 18.980 19.605 19.100 ;
        RECT 21.305 18.955 21.475 19.125 ;
        RECT 22.225 18.955 22.395 19.125 ;
        RECT 22.670 18.990 22.890 19.160 ;
        RECT 25.310 19.145 34.955 19.825 ;
        RECT 36.805 19.145 38.635 19.955 ;
        RECT 24.535 18.990 24.695 19.100 ;
        RECT 22.715 18.980 22.825 18.990 ;
        RECT 26.395 18.980 26.505 19.100 ;
        RECT 28.215 18.980 28.375 19.090 ;
        RECT 29.615 18.980 29.725 19.100 ;
        RECT 31.425 18.935 31.595 19.125 ;
        RECT 34.645 18.955 34.815 19.145 ;
        RECT 35.135 18.980 35.245 19.100 ;
        RECT 36.480 18.985 36.600 19.095 ;
        RECT 38.325 18.935 38.495 19.145 ;
        RECT 1.385 18.125 3.215 18.935 ;
        RECT 8.745 18.255 9.700 18.935 ;
        RECT 12.380 18.255 13.335 18.935 ;
        RECT 18.360 18.255 19.315 18.935 ;
        RECT 21.580 18.255 22.535 18.935 ;
        RECT 31.385 18.025 34.495 18.935 ;
        RECT 36.805 18.125 38.635 18.935 ;
        RECT 1.385 13.705 3.215 14.515 ;
        RECT 25.310 14.505 27.080 14.615 ;
        RECT 25.310 14.385 28.010 14.505 ;
        RECT 32.675 14.385 33.595 14.605 ;
        RECT 1.525 13.495 1.695 13.705 ;
        RECT 3.350 13.550 3.570 13.720 ;
        RECT 5.985 13.705 6.940 14.385 ;
        RECT 5.215 13.550 5.375 13.660 ;
        RECT 3.395 13.540 3.505 13.550 ;
        RECT 7.045 13.515 7.215 13.685 ;
        RECT 7.535 13.540 7.645 13.660 ;
        RECT 8.885 13.515 9.055 13.685 ;
        RECT 9.330 13.550 9.550 13.720 ;
        RECT 9.620 13.705 10.575 14.385 ;
        RECT 9.345 13.515 9.515 13.550 ;
        RECT 1.385 12.685 3.215 13.495 ;
        RECT 7.825 12.815 8.780 13.495 ;
        RECT 10.710 13.480 10.930 13.650 ;
        RECT 13.010 13.550 13.230 13.720 ;
        RECT 17.900 13.705 18.855 14.385 ;
        RECT 22.085 13.705 23.040 14.385 ;
        RECT 25.310 13.705 34.955 14.385 ;
        RECT 36.805 13.705 38.635 14.515 ;
        RECT 14.415 13.550 14.575 13.660 ;
        RECT 15.815 13.540 15.925 13.660 ;
        RECT 16.705 13.515 16.875 13.685 ;
        RECT 17.625 13.515 17.795 13.685 ;
        RECT 18.070 13.550 18.290 13.705 ;
        RECT 19.035 13.540 19.145 13.660 ;
        RECT 20.855 13.550 21.015 13.660 ;
        RECT 21.795 13.655 21.905 13.660 ;
        RECT 21.760 13.545 21.905 13.655 ;
        RECT 21.795 13.540 21.905 13.545 ;
        RECT 23.145 13.515 23.315 13.685 ;
        RECT 23.635 13.650 23.745 13.660 ;
        RECT 23.615 13.540 23.775 13.650 ;
        RECT 24.520 13.545 24.640 13.655 ;
        RECT 25.905 13.515 26.075 13.685 ;
        RECT 26.395 13.540 26.505 13.660 ;
        RECT 28.215 13.540 28.375 13.650 ;
        RECT 29.570 13.550 29.790 13.705 ;
        RECT 33.250 13.550 33.470 13.705 ;
        RECT 34.645 13.515 34.815 13.705 ;
        RECT 35.135 13.540 35.245 13.660 ;
        RECT 38.325 13.495 38.495 13.705 ;
        RECT 16.980 12.815 17.935 13.495 ;
        RECT 24.845 12.815 25.800 13.495 ;
        RECT 36.805 12.685 38.635 13.495 ;
        RECT 1.385 8.265 3.215 9.075 ;
        RECT 11.460 8.265 12.415 8.945 ;
        RECT 22.085 8.265 23.040 8.945 ;
        RECT 25.305 8.265 26.260 8.945 ;
        RECT 28.940 8.265 29.895 8.945 ;
        RECT 1.525 8.055 1.695 8.265 ;
        RECT 3.395 8.210 3.505 8.220 ;
        RECT 1.385 7.245 3.215 8.055 ;
        RECT 3.350 8.040 3.570 8.210 ;
        RECT 5.200 8.105 5.320 8.215 ;
        RECT 5.665 8.075 5.835 8.245 ;
        RECT 7.075 8.210 7.185 8.220 ;
        RECT 5.940 7.375 6.895 8.055 ;
        RECT 7.030 8.040 7.250 8.210 ;
        RECT 9.805 8.075 9.975 8.245 ;
        RECT 10.295 8.100 10.405 8.220 ;
        RECT 10.720 8.105 10.840 8.215 ;
        RECT 11.185 8.075 11.355 8.245 ;
        RECT 12.105 8.075 12.275 8.245 ;
        RECT 12.595 8.100 12.705 8.220 ;
        RECT 13.515 8.100 13.625 8.220 ;
        RECT 14.415 8.110 14.575 8.220 ;
        RECT 15.325 8.075 15.495 8.245 ;
        RECT 15.770 8.055 15.990 8.210 ;
        RECT 16.735 8.100 16.845 8.220 ;
        RECT 18.545 8.075 18.715 8.245 ;
        RECT 19.495 8.100 19.605 8.220 ;
        RECT 19.955 8.100 20.065 8.220 ;
        RECT 21.315 8.110 21.475 8.220 ;
        RECT 21.765 8.075 21.935 8.245 ;
        RECT 23.145 8.075 23.315 8.245 ;
        RECT 23.635 8.100 23.745 8.220 ;
        RECT 24.985 8.075 25.155 8.245 ;
        RECT 26.365 8.075 26.535 8.245 ;
        RECT 26.855 8.100 26.965 8.220 ;
        RECT 28.215 8.100 28.375 8.210 ;
        RECT 28.665 8.075 28.835 8.245 ;
        RECT 29.615 8.100 29.725 8.220 ;
        RECT 8.745 7.375 9.700 8.055 ;
        RECT 12.380 7.375 13.335 8.055 ;
        RECT 15.600 7.375 16.555 8.055 ;
        RECT 18.820 7.375 19.775 8.055 ;
        RECT 22.040 7.375 22.995 8.055 ;
        RECT 25.260 7.375 26.215 8.055 ;
        RECT 30.030 8.040 30.250 8.210 ;
        RECT 31.425 8.075 31.595 8.245 ;
        RECT 32.790 8.110 33.010 8.280 ;
        RECT 36.805 8.265 38.635 9.075 ;
        RECT 33.755 8.100 33.865 8.220 ;
        RECT 35.575 8.110 35.735 8.220 ;
        RECT 36.480 8.105 36.600 8.215 ;
        RECT 38.325 8.055 38.495 8.265 ;
        RECT 31.700 7.375 32.655 8.055 ;
        RECT 36.805 7.245 38.635 8.055 ;
        RECT 1.385 2.825 3.215 3.635 ;
        RECT 5.480 2.825 6.435 3.505 ;
        RECT 12.380 2.825 13.335 3.505 ;
        RECT 18.360 2.825 19.315 3.505 ;
        RECT 31.285 2.825 32.240 3.505 ;
        RECT 36.805 2.825 38.635 3.635 ;
        RECT 1.525 2.635 1.695 2.825 ;
        RECT 3.395 2.660 3.505 2.780 ;
        RECT 5.205 2.635 5.375 2.805 ;
        RECT 6.570 2.600 6.790 2.770 ;
        RECT 10.295 2.660 10.405 2.780 ;
        RECT 12.105 2.635 12.275 2.805 ;
        RECT 13.515 2.660 13.625 2.780 ;
        RECT 15.815 2.660 15.925 2.780 ;
        RECT 17.620 2.665 17.740 2.775 ;
        RECT 18.085 2.635 18.255 2.805 ;
        RECT 19.450 2.600 19.670 2.770 ;
        RECT 23.130 2.600 23.350 2.770 ;
        RECT 26.855 2.660 26.965 2.780 ;
        RECT 28.660 2.665 28.780 2.775 ;
        RECT 29.615 2.660 29.725 2.780 ;
        RECT 32.345 2.635 32.515 2.805 ;
        RECT 32.790 2.600 33.010 2.770 ;
        RECT 36.480 2.665 36.600 2.775 ;
        RECT 38.325 2.635 38.495 2.825 ;
      LAYER li1 ;
        RECT 24.465 35.735 24.705 36.685 ;
        RECT 6.575 34.035 6.815 34.985 ;
        RECT 22.160 34.600 22.485 35.105 ;
        RECT 21.705 34.070 22.485 34.600 ;
        RECT 22.155 32.895 22.485 34.070 ;
        RECT 22.675 34.035 22.915 34.985 ;
        RECT 24.925 34.035 25.165 34.985 ;
        RECT 21.705 30.295 21.945 31.245 ;
        RECT 22.135 31.210 22.465 32.385 ;
        RECT 32.315 32.045 32.695 32.215 ;
        RECT 32.315 31.875 32.485 32.045 ;
        RECT 34.075 31.875 34.405 32.385 ;
        RECT 31.825 31.675 32.485 31.875 ;
        RECT 32.655 31.705 34.875 31.875 ;
        RECT 22.135 30.680 22.915 31.210 ;
        RECT 31.825 30.745 31.995 31.675 ;
        RECT 32.655 31.505 32.825 31.705 ;
        RECT 32.165 31.335 32.825 31.505 ;
        RECT 32.165 30.915 32.335 31.335 ;
        RECT 33.335 30.995 34.030 31.195 ;
        RECT 32.655 30.745 33.565 30.825 ;
        RECT 34.705 30.745 34.875 31.705 ;
        RECT 22.135 30.175 22.460 30.680 ;
        RECT 31.825 30.265 32.145 30.745 ;
        RECT 32.315 30.655 33.565 30.745 ;
        RECT 32.315 30.575 32.825 30.655 ;
        RECT 32.315 30.175 32.545 30.575 ;
        RECT 33.235 30.175 33.565 30.655 ;
        RECT 34.410 30.200 34.875 30.745 ;
        RECT 21.235 29.025 21.565 29.665 ;
        RECT 20.785 28.595 21.135 28.845 ;
        RECT 21.305 28.425 21.475 29.025 ;
        RECT 21.645 28.595 21.995 28.845 ;
        RECT 24.005 28.595 24.245 29.545 ;
        RECT 24.435 29.160 24.760 29.665 ;
        RECT 24.435 28.630 25.215 29.160 ;
        RECT 21.305 28.255 21.985 28.425 ;
        RECT 21.655 27.470 21.985 28.255 ;
        RECT 24.435 27.455 24.765 28.630 ;
        RECT 5.605 24.855 5.845 25.805 ;
        RECT 6.035 25.770 6.365 26.945 ;
        RECT 6.035 25.240 6.815 25.770 ;
        RECT 6.035 24.735 6.360 25.240 ;
        RECT 8.825 24.855 9.065 25.805 ;
        RECT 9.255 25.770 9.585 26.945 ;
        RECT 9.255 25.240 10.035 25.770 ;
        RECT 9.255 24.735 9.580 25.240 ;
        RECT 12.045 24.855 12.285 25.805 ;
        RECT 12.475 25.770 12.805 26.945 ;
        RECT 12.475 25.240 13.255 25.770 ;
        RECT 12.475 24.735 12.800 25.240 ;
        RECT 17.565 24.855 17.805 25.805 ;
        RECT 17.995 25.770 18.325 26.945 ;
        RECT 21.215 25.965 21.545 26.945 ;
        RECT 26.765 26.585 27.060 26.945 ;
        RECT 27.975 26.755 31.070 26.925 ;
        RECT 26.765 26.415 29.075 26.585 ;
        RECT 26.765 26.355 27.250 26.415 ;
        RECT 17.995 25.240 18.775 25.770 ;
        RECT 20.805 25.555 21.140 25.805 ;
        RECT 21.310 25.365 21.480 25.965 ;
        RECT 21.650 25.535 21.985 25.805 ;
        RECT 17.995 24.735 18.320 25.240 ;
        RECT 20.785 24.735 21.480 25.365 ;
        RECT 26.765 25.065 26.935 26.355 ;
        RECT 27.165 25.975 27.985 26.185 ;
        RECT 27.165 25.805 27.335 25.975 ;
        RECT 28.155 25.925 28.735 26.095 ;
        RECT 27.105 25.475 27.335 25.805 ;
        RECT 27.505 25.555 27.915 25.805 ;
        RECT 27.165 25.385 27.335 25.475 ;
        RECT 28.085 25.425 28.395 25.755 ;
        RECT 28.565 25.475 28.735 25.925 ;
        RECT 27.165 25.230 27.905 25.385 ;
        RECT 27.165 25.215 27.945 25.230 ;
        RECT 26.765 24.735 27.065 25.065 ;
        RECT 27.655 24.775 27.945 25.215 ;
        RECT 28.190 25.210 28.395 25.425 ;
        RECT 28.905 25.075 29.075 26.415 ;
        RECT 29.610 26.095 30.025 26.525 ;
        RECT 29.245 25.925 30.025 26.095 ;
        RECT 28.270 24.905 28.735 24.945 ;
        RECT 29.245 24.905 29.415 25.925 ;
        RECT 29.585 25.475 30.010 25.750 ;
        RECT 29.585 25.110 29.795 25.475 ;
        RECT 30.205 25.370 30.375 26.755 ;
        RECT 30.165 25.305 30.375 25.370 ;
        RECT 29.965 25.200 30.375 25.305 ;
        RECT 29.965 25.135 30.335 25.200 ;
        RECT 28.270 24.735 29.415 24.905 ;
        RECT 29.965 24.800 30.135 25.135 ;
        RECT 30.545 25.075 30.715 26.585 ;
        RECT 30.900 26.545 31.070 26.755 ;
        RECT 32.440 26.715 33.910 26.885 ;
        RECT 30.900 26.375 33.400 26.545 ;
        RECT 33.740 26.525 33.910 26.715 ;
        RECT 30.505 24.965 30.715 25.075 ;
        RECT 30.305 24.745 30.715 24.965 ;
        RECT 30.895 25.925 31.315 26.195 ;
        RECT 30.895 24.895 31.135 25.925 ;
        RECT 31.545 25.685 31.715 26.375 ;
        RECT 33.740 26.355 34.425 26.525 ;
        RECT 31.885 26.005 32.270 26.175 ;
        RECT 32.440 26.015 34.025 26.185 ;
        RECT 31.885 25.855 32.165 26.005 ;
        RECT 31.545 25.515 31.825 25.685 ;
        RECT 31.655 24.935 31.825 25.515 ;
        RECT 31.995 25.275 32.165 25.855 ;
        RECT 32.440 25.805 32.610 26.015 ;
        RECT 32.335 25.475 32.610 25.805 ;
        RECT 32.780 25.555 33.345 25.805 ;
        RECT 32.835 25.275 33.215 25.385 ;
        RECT 31.995 25.105 33.215 25.275 ;
        RECT 33.515 25.075 33.685 26.015 ;
        RECT 34.255 25.805 34.425 26.355 ;
        RECT 34.595 25.920 34.875 26.945 ;
        RECT 34.255 25.475 34.460 25.805 ;
        RECT 34.255 25.345 34.430 25.475 ;
        RECT 34.630 25.405 34.875 25.920 ;
        RECT 33.855 25.175 34.430 25.345 ;
        RECT 31.655 24.765 32.285 24.935 ;
        RECT 32.455 24.905 32.890 24.935 ;
        RECT 33.855 24.905 34.025 25.175 ;
        RECT 32.455 24.735 34.025 24.905 ;
        RECT 34.615 24.830 34.875 25.405 ;
        RECT 5.600 23.720 5.925 24.225 ;
        RECT 5.145 23.190 5.925 23.720 ;
        RECT 5.595 22.015 5.925 23.190 ;
        RECT 6.115 23.155 6.355 24.105 ;
        RECT 8.365 23.155 8.605 24.105 ;
        RECT 8.795 23.720 9.120 24.225 ;
        RECT 14.430 23.845 14.605 24.135 ;
        RECT 8.795 23.190 9.575 23.720 ;
        RECT 14.430 23.675 14.925 23.845 ;
        RECT 15.280 23.715 15.495 24.085 ;
        RECT 15.730 23.945 16.330 24.115 ;
        RECT 17.245 24.015 17.675 24.185 ;
        RECT 8.795 22.015 9.125 23.190 ;
        RECT 14.405 22.735 14.585 23.505 ;
        RECT 14.755 22.695 14.925 23.675 ;
        RECT 15.095 23.385 15.495 23.715 ;
        RECT 15.665 23.445 15.990 23.775 ;
        RECT 15.480 23.035 15.650 23.195 ;
        RECT 15.265 22.865 15.650 23.035 ;
        RECT 15.820 22.905 15.990 23.445 ;
        RECT 16.160 23.245 16.330 23.945 ;
        RECT 16.500 23.465 16.875 23.765 ;
        RECT 16.160 23.075 16.500 23.245 ;
        RECT 16.670 23.160 16.875 23.465 ;
        RECT 17.045 23.160 17.335 23.765 ;
        RECT 17.505 23.420 17.675 24.015 ;
        RECT 17.845 23.805 18.080 24.135 ;
        RECT 15.820 22.695 16.160 22.905 ;
        RECT 14.755 22.565 16.160 22.695 ;
        RECT 14.435 22.525 16.160 22.565 ;
        RECT 14.435 22.395 14.925 22.525 ;
        RECT 14.435 22.105 14.605 22.395 ;
        RECT 16.330 22.355 16.500 23.075 ;
        RECT 17.505 23.090 17.740 23.420 ;
        RECT 17.505 22.990 17.675 23.090 ;
        RECT 17.405 22.820 17.675 22.990 ;
        RECT 17.405 22.695 17.575 22.820 ;
        RECT 17.230 22.525 17.575 22.695 ;
        RECT 17.910 22.670 18.080 23.805 ;
        RECT 17.825 22.355 18.080 22.670 ;
        RECT 15.670 22.185 16.500 22.355 ;
        RECT 17.565 22.185 18.080 22.355 ;
        RECT 18.250 22.355 18.440 24.135 ;
        RECT 18.655 23.895 18.860 24.225 ;
        RECT 19.585 24.015 20.480 24.185 ;
        RECT 18.655 22.915 18.825 23.895 ;
        RECT 19.005 23.085 19.375 23.765 ;
        RECT 19.585 22.915 19.755 24.015 ;
        RECT 18.655 22.745 19.755 22.915 ;
        RECT 18.655 22.585 18.845 22.745 ;
        RECT 18.250 22.185 18.775 22.355 ;
        RECT 19.585 22.325 19.755 22.745 ;
        RECT 19.925 23.445 20.545 23.775 ;
        RECT 20.795 23.485 21.105 24.105 ;
        RECT 21.695 23.755 22.025 24.215 ;
        RECT 19.925 22.495 20.215 23.445 ;
        RECT 20.795 23.405 21.205 23.485 ;
        RECT 20.385 22.835 20.725 23.235 ;
        RECT 20.895 23.155 21.205 23.405 ;
        RECT 21.375 23.155 21.685 23.485 ;
        RECT 21.375 22.985 21.545 23.155 ;
        RECT 21.855 22.985 22.025 23.755 ;
        RECT 20.935 22.815 21.545 22.985 ;
        RECT 20.935 22.355 21.105 22.815 ;
        RECT 21.715 22.645 22.025 22.985 ;
        RECT 19.585 22.155 20.535 22.325 ;
        RECT 20.785 22.185 21.105 22.355 ;
        RECT 21.615 22.025 22.025 22.645 ;
        RECT 6.055 20.330 6.385 21.505 ;
        RECT 5.605 19.800 6.385 20.330 ;
        RECT 6.060 19.295 6.385 19.800 ;
        RECT 6.575 19.415 6.815 20.365 ;
        RECT 9.275 20.330 9.605 21.505 ;
        RECT 8.825 19.800 9.605 20.330 ;
        RECT 9.280 19.295 9.605 19.800 ;
        RECT 9.795 19.415 10.035 20.365 ;
        RECT 12.045 19.415 12.285 20.365 ;
        RECT 12.475 20.330 12.805 21.505 ;
        RECT 12.475 19.800 13.255 20.330 ;
        RECT 12.475 19.295 12.800 19.800 ;
        RECT 18.025 19.415 18.265 20.365 ;
        RECT 18.455 20.330 18.785 21.505 ;
        RECT 21.695 20.330 22.025 21.505 ;
        RECT 25.820 20.655 26.150 21.500 ;
        RECT 25.385 20.535 26.150 20.655 ;
        RECT 26.660 20.955 26.990 21.465 ;
        RECT 25.385 20.485 25.985 20.535 ;
        RECT 18.455 19.800 19.235 20.330 ;
        RECT 21.245 19.800 22.025 20.330 ;
        RECT 18.455 19.295 18.780 19.800 ;
        RECT 21.700 19.295 22.025 19.800 ;
        RECT 22.215 19.415 22.455 20.365 ;
        RECT 25.385 19.935 25.940 20.485 ;
        RECT 26.660 20.365 26.910 20.955 ;
        RECT 27.280 20.805 27.450 21.415 ;
        RECT 28.180 21.125 28.420 21.415 ;
        RECT 29.220 21.205 29.850 21.455 ;
        RECT 29.220 21.125 29.390 21.205 ;
        RECT 30.800 21.125 30.970 21.415 ;
        RECT 31.770 21.290 32.600 21.460 ;
        RECT 28.180 20.955 29.390 21.125 ;
        RECT 26.110 20.035 26.910 20.365 ;
        RECT 25.385 19.895 25.970 19.935 ;
        RECT 25.385 19.865 25.985 19.895 ;
        RECT 25.385 19.805 26.070 19.865 ;
        RECT 25.825 19.305 26.070 19.805 ;
        RECT 26.740 19.385 26.910 20.035 ;
        RECT 27.080 20.785 27.450 20.805 ;
        RECT 27.080 20.615 29.050 20.785 ;
        RECT 27.080 19.720 27.270 20.615 ;
        RECT 29.220 20.445 29.390 20.955 ;
        RECT 29.560 20.695 30.080 21.005 ;
        RECT 27.470 20.275 29.390 20.445 ;
        RECT 27.470 20.215 27.820 20.275 ;
        RECT 27.080 19.390 27.430 19.720 ;
        RECT 28.470 19.515 28.640 20.275 ;
        RECT 29.560 20.105 29.740 20.515 ;
        RECT 28.810 19.935 29.160 20.055 ;
        RECT 29.910 19.935 30.080 20.695 ;
        RECT 28.810 19.765 30.080 19.935 ;
        RECT 30.250 20.875 31.600 21.125 ;
        RECT 30.250 20.105 30.420 20.875 ;
        RECT 31.350 20.615 31.600 20.875 ;
        RECT 30.590 20.445 30.840 20.605 ;
        RECT 31.770 20.445 31.940 21.290 ;
        RECT 32.835 21.005 33.005 21.505 ;
        RECT 33.725 21.085 33.945 21.505 ;
        RECT 32.110 20.615 32.610 20.995 ;
        RECT 32.835 20.835 33.530 21.005 ;
        RECT 30.590 20.275 31.940 20.445 ;
        RECT 31.520 20.235 31.940 20.275 ;
        RECT 30.250 19.765 30.650 20.105 ;
        RECT 28.470 19.345 29.320 19.515 ;
        RECT 30.400 19.335 30.650 19.765 ;
        RECT 31.520 19.505 31.690 20.235 ;
        RECT 31.860 19.685 32.210 20.055 ;
        RECT 32.390 19.745 32.610 20.615 ;
        RECT 32.780 20.045 33.190 20.665 ;
        RECT 33.360 19.865 33.530 20.835 ;
        RECT 32.835 19.675 33.530 19.865 ;
        RECT 31.520 19.305 32.535 19.505 ;
        RECT 32.835 19.345 33.005 19.675 ;
        RECT 33.725 19.605 33.955 21.085 ;
        RECT 34.615 21.005 34.875 21.505 ;
        RECT 34.125 20.835 34.875 21.005 ;
        RECT 34.125 19.845 34.355 20.835 ;
        RECT 34.125 19.675 34.875 19.845 ;
        RECT 33.725 19.385 33.945 19.605 ;
        RECT 34.615 19.385 34.875 19.675 ;
        RECT 9.280 18.280 9.605 18.785 ;
        RECT 8.825 17.750 9.605 18.280 ;
        RECT 9.275 16.575 9.605 17.750 ;
        RECT 9.795 17.715 10.035 18.665 ;
        RECT 12.045 17.715 12.285 18.665 ;
        RECT 12.475 18.280 12.800 18.785 ;
        RECT 12.475 17.750 13.255 18.280 ;
        RECT 12.475 16.575 12.805 17.750 ;
        RECT 18.025 17.715 18.265 18.665 ;
        RECT 18.455 18.280 18.780 18.785 ;
        RECT 18.455 17.750 19.235 18.280 ;
        RECT 18.455 16.575 18.785 17.750 ;
        RECT 21.245 17.715 21.485 18.665 ;
        RECT 21.675 18.280 22.000 18.785 ;
        RECT 21.675 17.750 22.455 18.280 ;
        RECT 31.365 18.215 31.830 18.760 ;
        RECT 32.675 18.305 33.005 18.785 ;
        RECT 33.695 18.385 33.925 18.785 ;
        RECT 33.415 18.305 33.925 18.385 ;
        RECT 32.675 18.215 33.925 18.305 ;
        RECT 34.095 18.215 34.415 18.695 ;
        RECT 21.675 16.575 22.005 17.750 ;
        RECT 31.365 17.255 31.535 18.215 ;
        RECT 32.675 18.135 33.585 18.215 ;
        RECT 31.705 17.595 31.950 18.045 ;
        RECT 32.210 17.765 32.905 17.965 ;
        RECT 33.075 17.795 33.675 17.965 ;
        RECT 33.075 17.595 33.245 17.795 ;
        RECT 33.905 17.625 34.075 18.045 ;
        RECT 31.705 17.425 33.245 17.595 ;
        RECT 33.415 17.455 34.075 17.625 ;
        RECT 33.415 17.255 33.585 17.455 ;
        RECT 34.245 17.285 34.415 18.215 ;
        RECT 31.365 17.085 33.585 17.255 ;
        RECT 33.755 17.085 34.415 17.285 ;
        RECT 31.835 16.575 32.165 17.085 ;
        RECT 33.755 16.915 33.925 17.085 ;
        RECT 33.545 16.745 33.925 16.915 ;
        RECT 6.515 14.890 6.845 16.065 ;
        RECT 6.065 14.360 6.845 14.890 ;
        RECT 6.520 13.855 6.845 14.360 ;
        RECT 7.035 13.975 7.275 14.925 ;
        RECT 9.285 13.975 9.525 14.925 ;
        RECT 9.715 14.890 10.045 16.065 ;
        RECT 9.715 14.360 10.495 14.890 ;
        RECT 9.715 13.855 10.040 14.360 ;
        RECT 17.565 13.975 17.805 14.925 ;
        RECT 17.995 14.890 18.325 16.065 ;
        RECT 22.615 14.890 22.945 16.065 ;
        RECT 25.820 15.215 26.150 16.060 ;
        RECT 25.385 15.095 26.150 15.215 ;
        RECT 26.660 15.515 26.990 16.025 ;
        RECT 25.385 15.045 25.985 15.095 ;
        RECT 17.995 14.360 18.775 14.890 ;
        RECT 22.165 14.360 22.945 14.890 ;
        RECT 17.995 13.855 18.320 14.360 ;
        RECT 22.620 13.855 22.945 14.360 ;
        RECT 23.135 13.975 23.375 14.925 ;
        RECT 25.385 14.495 25.940 15.045 ;
        RECT 26.660 14.925 26.910 15.515 ;
        RECT 27.280 15.365 27.450 15.975 ;
        RECT 28.180 15.685 28.420 15.975 ;
        RECT 29.220 15.765 29.850 16.015 ;
        RECT 29.220 15.685 29.390 15.765 ;
        RECT 30.800 15.685 30.970 15.975 ;
        RECT 31.770 15.850 32.600 16.020 ;
        RECT 28.180 15.515 29.390 15.685 ;
        RECT 26.110 14.595 26.910 14.925 ;
        RECT 25.385 14.455 25.970 14.495 ;
        RECT 25.385 14.425 25.985 14.455 ;
        RECT 25.385 14.365 26.070 14.425 ;
        RECT 25.825 13.865 26.070 14.365 ;
        RECT 26.740 13.945 26.910 14.595 ;
        RECT 27.080 15.345 27.450 15.365 ;
        RECT 27.080 15.175 29.050 15.345 ;
        RECT 27.080 14.280 27.270 15.175 ;
        RECT 29.220 15.005 29.390 15.515 ;
        RECT 29.560 15.255 30.080 15.565 ;
        RECT 27.470 14.835 29.390 15.005 ;
        RECT 27.470 14.775 27.820 14.835 ;
        RECT 27.080 13.950 27.430 14.280 ;
        RECT 28.470 14.075 28.640 14.835 ;
        RECT 29.560 14.665 29.740 15.075 ;
        RECT 28.810 14.495 29.160 14.615 ;
        RECT 29.910 14.495 30.080 15.255 ;
        RECT 28.810 14.325 30.080 14.495 ;
        RECT 30.250 15.435 31.600 15.685 ;
        RECT 30.250 14.665 30.420 15.435 ;
        RECT 31.350 15.175 31.600 15.435 ;
        RECT 30.590 15.005 30.840 15.165 ;
        RECT 31.770 15.005 31.940 15.850 ;
        RECT 32.835 15.565 33.005 16.065 ;
        RECT 33.725 15.645 33.945 16.065 ;
        RECT 32.110 15.175 32.610 15.555 ;
        RECT 32.835 15.395 33.530 15.565 ;
        RECT 30.590 14.835 31.940 15.005 ;
        RECT 31.520 14.795 31.940 14.835 ;
        RECT 30.250 14.325 30.650 14.665 ;
        RECT 28.470 13.905 29.320 14.075 ;
        RECT 30.400 13.895 30.650 14.325 ;
        RECT 31.520 14.065 31.690 14.795 ;
        RECT 31.860 14.245 32.210 14.615 ;
        RECT 32.390 14.305 32.610 15.175 ;
        RECT 32.780 14.605 33.190 15.225 ;
        RECT 33.360 14.425 33.530 15.395 ;
        RECT 32.835 14.235 33.530 14.425 ;
        RECT 31.520 13.865 32.535 14.065 ;
        RECT 32.835 13.905 33.005 14.235 ;
        RECT 33.725 14.165 33.955 15.645 ;
        RECT 34.615 15.565 34.875 16.065 ;
        RECT 34.125 15.395 34.875 15.565 ;
        RECT 34.125 14.405 34.355 15.395 ;
        RECT 34.125 14.235 34.875 14.405 ;
        RECT 33.725 13.945 33.945 14.165 ;
        RECT 34.615 13.945 34.875 14.235 ;
        RECT 8.360 12.840 8.685 13.345 ;
        RECT 7.905 12.310 8.685 12.840 ;
        RECT 8.355 11.135 8.685 12.310 ;
        RECT 8.875 12.275 9.115 13.225 ;
        RECT 16.645 12.275 16.885 13.225 ;
        RECT 17.075 12.840 17.400 13.345 ;
        RECT 25.380 12.840 25.705 13.345 ;
        RECT 17.075 12.310 17.855 12.840 ;
        RECT 24.925 12.310 25.705 12.840 ;
        RECT 17.075 11.135 17.405 12.310 ;
        RECT 25.375 11.135 25.705 12.310 ;
        RECT 25.895 12.275 26.135 13.225 ;
        RECT 11.125 8.535 11.365 9.485 ;
        RECT 11.555 9.450 11.885 10.625 ;
        RECT 22.615 9.450 22.945 10.625 ;
        RECT 11.555 8.920 12.335 9.450 ;
        RECT 22.165 8.920 22.945 9.450 ;
        RECT 11.555 8.415 11.880 8.920 ;
        RECT 22.620 8.415 22.945 8.920 ;
        RECT 23.135 8.535 23.375 9.485 ;
        RECT 25.835 9.450 26.165 10.625 ;
        RECT 25.385 8.920 26.165 9.450 ;
        RECT 25.840 8.415 26.165 8.920 ;
        RECT 26.355 8.535 26.595 9.485 ;
        RECT 28.605 8.535 28.845 9.485 ;
        RECT 29.035 9.450 29.365 10.625 ;
        RECT 29.035 8.920 29.815 9.450 ;
        RECT 29.035 8.415 29.360 8.920 ;
        RECT 5.605 6.835 5.845 7.785 ;
        RECT 6.035 7.400 6.360 7.905 ;
        RECT 9.280 7.400 9.605 7.905 ;
        RECT 6.035 6.870 6.815 7.400 ;
        RECT 8.825 6.870 9.605 7.400 ;
        RECT 6.035 5.695 6.365 6.870 ;
        RECT 9.275 5.695 9.605 6.870 ;
        RECT 9.795 6.835 10.035 7.785 ;
        RECT 12.045 6.835 12.285 7.785 ;
        RECT 12.475 7.400 12.800 7.905 ;
        RECT 12.475 6.870 13.255 7.400 ;
        RECT 12.475 5.695 12.805 6.870 ;
        RECT 15.265 6.835 15.505 7.785 ;
        RECT 15.695 7.400 16.020 7.905 ;
        RECT 15.695 6.870 16.475 7.400 ;
        RECT 15.695 5.695 16.025 6.870 ;
        RECT 18.485 6.835 18.725 7.785 ;
        RECT 18.915 7.400 19.240 7.905 ;
        RECT 18.915 6.870 19.695 7.400 ;
        RECT 18.915 5.695 19.245 6.870 ;
        RECT 21.705 6.835 21.945 7.785 ;
        RECT 22.135 7.400 22.460 7.905 ;
        RECT 22.135 6.870 22.915 7.400 ;
        RECT 22.135 5.695 22.465 6.870 ;
        RECT 24.925 6.835 25.165 7.785 ;
        RECT 25.355 7.400 25.680 7.905 ;
        RECT 25.355 6.870 26.135 7.400 ;
        RECT 25.355 5.695 25.685 6.870 ;
        RECT 31.365 6.835 31.605 7.785 ;
        RECT 31.795 7.400 32.120 7.905 ;
        RECT 31.795 6.870 32.575 7.400 ;
        RECT 31.795 5.695 32.125 6.870 ;
        RECT 5.575 4.010 5.905 5.185 ;
        RECT 5.575 3.480 6.355 4.010 ;
        RECT 5.575 2.975 5.900 3.480 ;
        RECT 12.045 3.095 12.285 4.045 ;
        RECT 12.475 4.010 12.805 5.185 ;
        RECT 12.475 3.480 13.255 4.010 ;
        RECT 12.475 2.975 12.800 3.480 ;
        RECT 18.025 3.095 18.265 4.045 ;
        RECT 18.455 4.010 18.785 5.185 ;
        RECT 18.455 3.480 19.235 4.010 ;
        RECT 18.455 2.975 18.780 3.480 ;
        RECT 32.335 3.095 32.575 4.045 ;
      LAYER mcon ;
        RECT 24.525 35.785 24.695 35.955 ;
        RECT 6.585 34.085 6.755 34.255 ;
        RECT 22.225 34.425 22.395 34.595 ;
        RECT 22.685 34.765 22.855 34.935 ;
        RECT 24.985 34.425 25.155 34.595 ;
        RECT 22.225 32.045 22.395 32.215 ;
        RECT 21.765 30.345 21.935 30.515 ;
        RECT 31.885 30.345 32.055 30.515 ;
        RECT 21.305 29.325 21.475 29.495 ;
        RECT 20.845 28.645 21.015 28.815 ;
        RECT 21.765 28.645 21.935 28.815 ;
        RECT 24.065 28.645 24.235 28.815 ;
        RECT 24.525 27.625 24.695 27.795 ;
        RECT 5.665 24.905 5.835 25.075 ;
        RECT 6.125 24.905 6.295 25.075 ;
        RECT 8.885 24.905 9.055 25.075 ;
        RECT 9.805 25.245 9.975 25.415 ;
        RECT 12.105 25.245 12.275 25.415 ;
        RECT 13.025 25.245 13.195 25.415 ;
        RECT 17.625 25.245 17.795 25.415 ;
        RECT 21.305 26.605 21.475 26.775 ;
        RECT 20.845 25.585 21.015 25.755 ;
        RECT 21.765 25.585 21.935 25.755 ;
        RECT 18.085 24.905 18.255 25.075 ;
        RECT 28.205 25.925 28.375 26.095 ;
        RECT 27.745 25.585 27.915 25.755 ;
        RECT 28.205 25.245 28.375 25.415 ;
        RECT 29.585 25.925 29.755 26.095 ;
        RECT 27.745 24.905 27.915 25.075 ;
        RECT 29.585 25.245 29.755 25.415 ;
        RECT 30.505 24.905 30.675 25.075 ;
        RECT 31.885 25.925 32.055 26.095 ;
        RECT 30.965 25.245 31.135 25.415 ;
        RECT 32.805 25.585 32.975 25.755 ;
        RECT 34.645 24.905 34.815 25.075 ;
        RECT 5.665 23.885 5.835 24.055 ;
        RECT 6.125 23.205 6.295 23.375 ;
        RECT 8.425 23.545 8.595 23.715 ;
        RECT 8.885 23.885 9.055 24.055 ;
        RECT 14.405 22.865 14.575 23.035 ;
        RECT 15.325 23.545 15.495 23.715 ;
        RECT 15.325 22.865 15.495 23.035 ;
        RECT 16.705 23.545 16.875 23.715 ;
        RECT 17.165 23.205 17.335 23.375 ;
        RECT 15.785 22.525 15.955 22.695 ;
        RECT 16.245 22.185 16.415 22.355 ;
        RECT 17.625 22.185 17.795 22.355 ;
        RECT 19.005 23.205 19.175 23.375 ;
        RECT 18.545 22.185 18.715 22.355 ;
        RECT 21.765 23.885 21.935 24.055 ;
        RECT 20.845 23.545 21.015 23.715 ;
        RECT 20.385 22.865 20.555 23.035 ;
        RECT 19.925 22.525 20.095 22.695 ;
        RECT 20.845 22.185 21.015 22.355 ;
        RECT 6.125 21.165 6.295 21.335 ;
        RECT 6.585 19.805 6.755 19.975 ;
        RECT 8.885 19.805 9.055 19.975 ;
        RECT 9.805 19.465 9.975 19.635 ;
        RECT 12.105 19.465 12.275 19.635 ;
        RECT 18.545 21.165 18.715 21.335 ;
        RECT 13.025 20.145 13.195 20.315 ;
        RECT 18.085 19.465 18.255 19.635 ;
        RECT 21.765 21.165 21.935 21.335 ;
        RECT 22.225 19.465 22.395 19.635 ;
        RECT 29.585 20.825 29.755 20.995 ;
        RECT 29.565 20.145 29.735 20.315 ;
        RECT 32.345 20.825 32.515 20.995 ;
        RECT 31.885 19.805 32.055 19.975 ;
        RECT 32.805 20.485 32.975 20.655 ;
        RECT 33.725 19.805 33.895 19.975 ;
        RECT 34.185 20.825 34.355 20.995 ;
        RECT 9.345 18.105 9.515 18.275 ;
        RECT 9.805 17.765 9.975 17.935 ;
        RECT 12.105 18.105 12.275 18.275 ;
        RECT 12.565 18.445 12.735 18.615 ;
        RECT 18.085 17.765 18.255 17.935 ;
        RECT 18.545 18.445 18.715 18.615 ;
        RECT 21.305 17.765 21.475 17.935 ;
        RECT 21.765 18.445 21.935 18.615 ;
        RECT 32.345 17.765 32.515 17.935 ;
        RECT 32.805 17.425 32.975 17.595 ;
        RECT 33.725 16.745 33.895 16.915 ;
        RECT 9.805 15.725 9.975 15.895 ;
        RECT 6.585 14.365 6.755 14.535 ;
        RECT 7.045 14.025 7.215 14.195 ;
        RECT 9.345 14.365 9.515 14.535 ;
        RECT 18.085 15.725 18.255 15.895 ;
        RECT 17.625 14.025 17.795 14.195 ;
        RECT 22.685 15.725 22.855 15.895 ;
        RECT 25.905 15.725 26.075 15.895 ;
        RECT 23.145 14.025 23.315 14.195 ;
        RECT 29.585 15.385 29.755 15.555 ;
        RECT 29.565 14.705 29.735 14.875 ;
        RECT 32.345 15.385 32.515 15.555 ;
        RECT 31.885 14.365 32.055 14.535 ;
        RECT 32.805 15.045 32.975 15.215 ;
        RECT 33.725 14.365 33.895 14.535 ;
        RECT 34.185 15.385 34.355 15.555 ;
        RECT 7.965 12.665 8.135 12.835 ;
        RECT 8.885 13.005 9.055 13.175 ;
        RECT 16.705 13.005 16.875 13.175 ;
        RECT 17.625 12.665 17.795 12.835 ;
        RECT 24.985 12.665 25.155 12.835 ;
        RECT 25.905 12.325 26.075 12.495 ;
        RECT 11.185 8.585 11.355 8.755 ;
        RECT 25.905 10.285 26.075 10.455 ;
        RECT 12.105 8.925 12.275 9.095 ;
        RECT 22.685 9.265 22.855 9.435 ;
        RECT 23.145 8.585 23.315 8.755 ;
        RECT 26.365 8.925 26.535 9.095 ;
        RECT 28.665 9.265 28.835 9.435 ;
        RECT 29.125 8.925 29.295 9.095 ;
        RECT 5.665 6.885 5.835 7.055 ;
        RECT 6.125 7.565 6.295 7.735 ;
        RECT 9.345 7.225 9.515 7.395 ;
        RECT 9.805 6.885 9.975 7.055 ;
        RECT 12.105 7.225 12.275 7.395 ;
        RECT 13.025 6.885 13.195 7.055 ;
        RECT 15.325 6.885 15.495 7.055 ;
        RECT 18.545 6.885 18.715 7.055 ;
        RECT 19.465 6.885 19.635 7.055 ;
        RECT 21.765 6.885 21.935 7.055 ;
        RECT 15.785 5.865 15.955 6.035 ;
        RECT 22.685 6.885 22.855 7.055 ;
        RECT 24.985 6.885 25.155 7.055 ;
        RECT 25.445 7.565 25.615 7.735 ;
        RECT 31.425 7.565 31.595 7.735 ;
        RECT 31.885 5.865 32.055 6.035 ;
        RECT 5.665 4.845 5.835 5.015 ;
        RECT 12.565 4.845 12.735 5.015 ;
        RECT 12.105 3.825 12.275 3.995 ;
        RECT 18.545 4.845 18.715 5.015 ;
        RECT 18.085 3.825 18.255 3.995 ;
        RECT 32.345 3.825 32.515 3.995 ;
      LAYER met1 ;
        RECT 22.610 35.940 22.930 36.000 ;
        RECT 24.465 35.940 24.755 35.985 ;
        RECT 22.610 35.800 24.755 35.940 ;
        RECT 22.610 35.740 22.930 35.800 ;
        RECT 24.465 35.755 24.755 35.800 ;
        RECT 22.610 34.920 22.930 34.980 ;
        RECT 22.415 34.780 22.930 34.920 ;
        RECT 22.610 34.720 22.930 34.780 ;
        RECT 22.165 34.580 22.455 34.625 ;
        RECT 24.925 34.580 25.215 34.625 ;
        RECT 22.165 34.440 25.215 34.580 ;
        RECT 22.165 34.395 22.455 34.440 ;
        RECT 24.925 34.395 25.215 34.440 ;
        RECT 6.525 34.055 6.815 34.285 ;
        RECT 6.600 33.900 6.740 34.055 ;
        RECT 31.350 33.900 31.670 33.960 ;
        RECT 6.600 33.760 31.670 33.900 ;
        RECT 31.350 33.700 31.670 33.760 ;
        RECT 22.165 32.200 22.455 32.245 ;
        RECT 22.610 32.200 22.930 32.260 ;
        RECT 22.165 32.060 22.930 32.200 ;
        RECT 22.165 32.015 22.455 32.060 ;
        RECT 22.610 32.000 22.930 32.060 ;
        RECT 21.230 30.500 21.550 30.560 ;
        RECT 21.705 30.500 21.995 30.545 ;
        RECT 21.230 30.360 21.995 30.500 ;
        RECT 21.230 30.300 21.550 30.360 ;
        RECT 21.705 30.315 21.995 30.360 ;
        RECT 31.825 30.500 32.115 30.545 ;
        RECT 32.730 30.500 33.050 30.560 ;
        RECT 31.825 30.360 33.050 30.500 ;
        RECT 31.825 30.315 32.115 30.360 ;
        RECT 32.730 30.300 33.050 30.360 ;
        RECT 21.230 29.480 21.550 29.540 ;
        RECT 21.035 29.340 21.550 29.480 ;
        RECT 21.230 29.280 21.550 29.340 ;
        RECT 20.770 28.800 21.090 28.860 ;
        RECT 21.690 28.800 22.010 28.860 ;
        RECT 23.990 28.800 24.310 28.860 ;
        RECT 20.575 28.660 21.090 28.800 ;
        RECT 21.495 28.660 22.010 28.800 ;
        RECT 23.795 28.660 24.310 28.800 ;
        RECT 20.770 28.600 21.090 28.660 ;
        RECT 21.690 28.600 22.010 28.660 ;
        RECT 23.990 28.600 24.310 28.660 ;
        RECT 24.465 27.780 24.755 27.825 ;
        RECT 31.350 27.780 31.670 27.840 ;
        RECT 24.465 27.640 31.670 27.780 ;
        RECT 24.465 27.595 24.755 27.640 ;
        RECT 31.350 27.580 31.670 27.640 ;
        RECT 21.245 26.760 21.535 26.805 ;
        RECT 23.990 26.760 24.310 26.820 ;
        RECT 21.245 26.620 24.310 26.760 ;
        RECT 21.245 26.575 21.535 26.620 ;
        RECT 23.990 26.560 24.310 26.620 ;
        RECT 28.145 25.895 28.435 26.125 ;
        RECT 29.525 26.080 29.815 26.125 ;
        RECT 31.825 26.080 32.115 26.125 ;
        RECT 29.525 25.940 32.115 26.080 ;
        RECT 29.525 25.895 29.815 25.940 ;
        RECT 31.825 25.895 32.115 25.940 ;
        RECT 20.770 25.740 21.090 25.800 ;
        RECT 21.690 25.740 22.010 25.800 ;
        RECT 20.575 25.600 21.090 25.740 ;
        RECT 21.495 25.600 22.010 25.740 ;
        RECT 20.770 25.540 21.090 25.600 ;
        RECT 21.690 25.540 22.010 25.600 ;
        RECT 27.685 25.555 27.975 25.785 ;
        RECT 28.220 25.740 28.360 25.895 ;
        RECT 32.730 25.740 33.050 25.800 ;
        RECT 28.220 25.600 32.040 25.740 ;
        RECT 32.535 25.600 33.050 25.740 ;
        RECT 9.745 25.400 10.035 25.445 ;
        RECT 12.045 25.400 12.335 25.445 ;
        RECT 9.745 25.260 12.335 25.400 ;
        RECT 9.745 25.215 10.035 25.260 ;
        RECT 12.045 25.215 12.335 25.260 ;
        RECT 12.965 25.400 13.255 25.445 ;
        RECT 17.565 25.400 17.855 25.445 ;
        RECT 12.965 25.260 17.855 25.400 ;
        RECT 12.965 25.215 13.255 25.260 ;
        RECT 17.565 25.215 17.855 25.260 ;
        RECT 19.850 25.400 20.170 25.460 ;
        RECT 27.760 25.400 27.900 25.555 ;
        RECT 31.900 25.460 32.040 25.600 ;
        RECT 32.730 25.540 33.050 25.600 ;
        RECT 19.850 25.260 27.900 25.400 ;
        RECT 28.145 25.400 28.435 25.445 ;
        RECT 29.525 25.400 29.815 25.445 ;
        RECT 30.905 25.400 31.195 25.445 ;
        RECT 28.145 25.260 31.195 25.400 ;
        RECT 19.850 25.200 20.170 25.260 ;
        RECT 28.145 25.215 28.435 25.260 ;
        RECT 29.525 25.215 29.815 25.260 ;
        RECT 30.905 25.215 31.195 25.260 ;
        RECT 31.810 25.200 32.130 25.460 ;
        RECT 5.590 25.060 5.910 25.120 ;
        RECT 5.395 24.920 5.910 25.060 ;
        RECT 5.590 24.860 5.910 24.920 ;
        RECT 6.065 25.060 6.355 25.105 ;
        RECT 7.890 25.060 8.210 25.120 ;
        RECT 8.810 25.060 9.130 25.120 ;
        RECT 6.065 24.920 8.210 25.060 ;
        RECT 8.615 24.920 9.130 25.060 ;
        RECT 6.065 24.875 6.355 24.920 ;
        RECT 7.890 24.860 8.210 24.920 ;
        RECT 8.810 24.860 9.130 24.920 ;
        RECT 16.630 25.060 16.950 25.120 ;
        RECT 18.025 25.060 18.315 25.105 ;
        RECT 16.630 24.920 18.315 25.060 ;
        RECT 16.630 24.860 16.950 24.920 ;
        RECT 18.025 24.875 18.315 24.920 ;
        RECT 27.685 25.060 27.975 25.105 ;
        RECT 30.445 25.060 30.735 25.105 ;
        RECT 27.685 24.920 30.735 25.060 ;
        RECT 27.685 24.875 27.975 24.920 ;
        RECT 30.445 24.875 30.735 24.920 ;
        RECT 32.730 25.060 33.050 25.120 ;
        RECT 34.585 25.060 34.875 25.105 ;
        RECT 32.730 24.920 34.875 25.060 ;
        RECT 32.730 24.860 33.050 24.920 ;
        RECT 34.585 24.875 34.875 24.920 ;
        RECT 5.590 24.040 5.910 24.100 ;
        RECT 8.810 24.040 9.130 24.100 ;
        RECT 21.690 24.040 22.010 24.100 ;
        RECT 5.395 23.900 5.910 24.040 ;
        RECT 8.615 23.900 9.130 24.040 ;
        RECT 21.495 23.900 22.010 24.040 ;
        RECT 5.590 23.840 5.910 23.900 ;
        RECT 8.810 23.840 9.130 23.900 ;
        RECT 21.690 23.840 22.010 23.900 ;
        RECT 7.890 23.700 8.210 23.760 ;
        RECT 8.365 23.700 8.655 23.745 ;
        RECT 7.890 23.560 8.655 23.700 ;
        RECT 7.890 23.500 8.210 23.560 ;
        RECT 8.365 23.515 8.655 23.560 ;
        RECT 15.265 23.700 15.555 23.745 ;
        RECT 16.170 23.700 16.490 23.760 ;
        RECT 15.265 23.560 16.490 23.700 ;
        RECT 15.265 23.515 15.555 23.560 ;
        RECT 16.170 23.500 16.490 23.560 ;
        RECT 16.630 23.700 16.950 23.760 ;
        RECT 19.850 23.700 20.170 23.760 ;
        RECT 20.770 23.700 21.090 23.760 ;
        RECT 16.630 23.560 17.145 23.700 ;
        RECT 18.100 23.560 20.170 23.700 ;
        RECT 20.575 23.560 21.090 23.700 ;
        RECT 16.630 23.500 16.950 23.560 ;
        RECT 6.050 23.360 6.370 23.420 ;
        RECT 5.855 23.220 6.370 23.360 ;
        RECT 6.050 23.160 6.370 23.220 ;
        RECT 17.105 23.360 17.395 23.405 ;
        RECT 18.100 23.360 18.240 23.560 ;
        RECT 19.850 23.500 20.170 23.560 ;
        RECT 20.770 23.500 21.090 23.560 ;
        RECT 18.930 23.360 19.250 23.420 ;
        RECT 17.105 23.220 18.240 23.360 ;
        RECT 18.735 23.220 19.250 23.360 ;
        RECT 17.105 23.175 17.395 23.220 ;
        RECT 18.930 23.160 19.250 23.220 ;
        RECT 14.345 23.020 14.635 23.065 ;
        RECT 15.265 23.020 15.555 23.065 ;
        RECT 20.325 23.020 20.615 23.065 ;
        RECT 14.345 22.880 20.615 23.020 ;
        RECT 14.345 22.835 14.635 22.880 ;
        RECT 15.265 22.835 15.555 22.880 ;
        RECT 20.325 22.835 20.615 22.880 ;
        RECT 15.725 22.680 16.015 22.725 ;
        RECT 19.865 22.680 20.155 22.725 ;
        RECT 15.725 22.540 20.155 22.680 ;
        RECT 15.725 22.495 16.015 22.540 ;
        RECT 19.865 22.495 20.155 22.540 ;
        RECT 16.185 22.340 16.475 22.385 ;
        RECT 17.565 22.340 17.855 22.385 ;
        RECT 16.185 22.200 17.855 22.340 ;
        RECT 16.185 22.155 16.475 22.200 ;
        RECT 17.565 22.155 17.855 22.200 ;
        RECT 18.485 22.340 18.775 22.385 ;
        RECT 20.785 22.340 21.075 22.385 ;
        RECT 18.485 22.200 21.075 22.340 ;
        RECT 18.485 22.155 18.775 22.200 ;
        RECT 20.785 22.155 21.075 22.200 ;
        RECT 6.050 21.320 6.370 21.380 ;
        RECT 5.855 21.180 6.370 21.320 ;
        RECT 6.050 21.120 6.370 21.180 ;
        RECT 18.485 21.320 18.775 21.365 ;
        RECT 18.930 21.320 19.250 21.380 ;
        RECT 18.485 21.180 19.250 21.320 ;
        RECT 18.485 21.135 18.775 21.180 ;
        RECT 18.930 21.120 19.250 21.180 ;
        RECT 20.770 21.320 21.090 21.380 ;
        RECT 21.705 21.320 21.995 21.365 ;
        RECT 20.770 21.180 21.995 21.320 ;
        RECT 20.770 21.120 21.090 21.180 ;
        RECT 21.705 21.135 21.995 21.180 ;
        RECT 29.525 20.980 29.815 21.025 ;
        RECT 32.285 20.980 32.575 21.025 ;
        RECT 34.125 20.980 34.415 21.025 ;
        RECT 29.525 20.840 34.415 20.980 ;
        RECT 29.525 20.795 29.815 20.840 ;
        RECT 32.285 20.795 32.575 20.840 ;
        RECT 34.125 20.795 34.415 20.840 ;
        RECT 32.730 20.640 33.050 20.700 ;
        RECT 32.535 20.500 33.050 20.640 ;
        RECT 32.730 20.440 33.050 20.500 ;
        RECT 12.965 20.300 13.255 20.345 ;
        RECT 16.170 20.300 16.490 20.360 ;
        RECT 12.965 20.160 16.490 20.300 ;
        RECT 12.965 20.115 13.255 20.160 ;
        RECT 16.170 20.100 16.490 20.160 ;
        RECT 29.505 20.300 29.795 20.345 ;
        RECT 29.505 20.160 32.040 20.300 ;
        RECT 29.505 20.115 29.795 20.160 ;
        RECT 31.825 20.005 32.040 20.160 ;
        RECT 6.525 19.960 6.815 20.005 ;
        RECT 8.825 19.960 9.115 20.005 ;
        RECT 6.525 19.820 9.115 19.960 ;
        RECT 6.525 19.775 6.815 19.820 ;
        RECT 8.825 19.775 9.115 19.820 ;
        RECT 31.825 19.960 32.115 20.005 ;
        RECT 33.665 19.960 33.955 20.005 ;
        RECT 31.825 19.820 33.955 19.960 ;
        RECT 31.825 19.775 32.115 19.820 ;
        RECT 33.665 19.775 33.955 19.820 ;
        RECT 9.270 19.620 9.590 19.680 ;
        RECT 9.745 19.620 10.035 19.665 ;
        RECT 9.270 19.480 10.035 19.620 ;
        RECT 9.270 19.420 9.590 19.480 ;
        RECT 9.745 19.435 10.035 19.480 ;
        RECT 12.045 19.620 12.335 19.665 ;
        RECT 12.490 19.620 12.810 19.680 ;
        RECT 12.045 19.480 12.810 19.620 ;
        RECT 12.045 19.435 12.335 19.480 ;
        RECT 12.490 19.420 12.810 19.480 ;
        RECT 18.025 19.620 18.315 19.665 ;
        RECT 18.470 19.620 18.790 19.680 ;
        RECT 18.025 19.480 18.790 19.620 ;
        RECT 18.025 19.435 18.315 19.480 ;
        RECT 18.470 19.420 18.790 19.480 ;
        RECT 22.150 19.620 22.470 19.680 ;
        RECT 22.150 19.480 22.665 19.620 ;
        RECT 22.150 19.420 22.470 19.480 ;
        RECT 12.490 18.600 12.810 18.660 ;
        RECT 18.470 18.600 18.790 18.660 ;
        RECT 12.295 18.460 12.810 18.600 ;
        RECT 18.275 18.460 18.790 18.600 ;
        RECT 12.490 18.400 12.810 18.460 ;
        RECT 18.470 18.400 18.790 18.460 ;
        RECT 21.705 18.600 21.995 18.645 ;
        RECT 22.150 18.600 22.470 18.660 ;
        RECT 21.705 18.460 22.470 18.600 ;
        RECT 21.705 18.415 21.995 18.460 ;
        RECT 22.150 18.400 22.470 18.460 ;
        RECT 9.285 18.260 9.575 18.305 ;
        RECT 12.045 18.260 12.335 18.305 ;
        RECT 9.285 18.120 12.335 18.260 ;
        RECT 9.285 18.075 9.575 18.120 ;
        RECT 12.045 18.075 12.335 18.120 ;
        RECT 9.730 17.920 10.050 17.980 ;
        RECT 18.010 17.920 18.330 17.980 ;
        RECT 9.535 17.780 10.050 17.920 ;
        RECT 17.815 17.780 18.330 17.920 ;
        RECT 9.730 17.720 10.050 17.780 ;
        RECT 18.010 17.720 18.330 17.780 ;
        RECT 21.245 17.735 21.535 17.965 ;
        RECT 31.810 17.920 32.130 17.980 ;
        RECT 32.285 17.920 32.575 17.965 ;
        RECT 31.810 17.780 32.575 17.920 ;
        RECT 9.270 17.580 9.590 17.640 ;
        RECT 21.320 17.580 21.460 17.735 ;
        RECT 31.810 17.720 32.130 17.780 ;
        RECT 32.285 17.735 32.575 17.780 ;
        RECT 22.610 17.580 22.930 17.640 ;
        RECT 9.270 17.440 22.930 17.580 ;
        RECT 9.270 17.380 9.590 17.440 ;
        RECT 22.610 17.380 22.930 17.440 ;
        RECT 32.745 17.580 33.035 17.625 ;
        RECT 33.190 17.580 33.510 17.640 ;
        RECT 32.745 17.440 33.510 17.580 ;
        RECT 32.745 17.395 33.035 17.440 ;
        RECT 33.190 17.380 33.510 17.440 ;
        RECT 32.730 16.900 33.050 16.960 ;
        RECT 33.665 16.900 33.955 16.945 ;
        RECT 32.730 16.760 33.955 16.900 ;
        RECT 32.730 16.700 33.050 16.760 ;
        RECT 33.665 16.715 33.955 16.760 ;
        RECT 9.730 15.880 10.050 15.940 ;
        RECT 18.010 15.880 18.330 15.940 ;
        RECT 22.610 15.880 22.930 15.940 ;
        RECT 9.535 15.740 10.050 15.880 ;
        RECT 17.815 15.740 18.330 15.880 ;
        RECT 22.415 15.740 22.930 15.880 ;
        RECT 9.730 15.680 10.050 15.740 ;
        RECT 18.010 15.680 18.330 15.740 ;
        RECT 22.610 15.680 22.930 15.740 ;
        RECT 25.845 15.880 26.135 15.925 ;
        RECT 31.810 15.880 32.130 15.940 ;
        RECT 25.845 15.740 32.130 15.880 ;
        RECT 25.845 15.695 26.135 15.740 ;
        RECT 31.810 15.680 32.130 15.740 ;
        RECT 29.525 15.540 29.815 15.585 ;
        RECT 32.285 15.540 32.575 15.585 ;
        RECT 34.125 15.540 34.415 15.585 ;
        RECT 29.525 15.400 34.415 15.540 ;
        RECT 29.525 15.355 29.815 15.400 ;
        RECT 32.285 15.355 32.575 15.400 ;
        RECT 34.125 15.355 34.415 15.400 ;
        RECT 32.730 15.200 33.050 15.260 ;
        RECT 32.535 15.060 33.050 15.200 ;
        RECT 32.730 15.000 33.050 15.060 ;
        RECT 29.505 14.860 29.795 14.905 ;
        RECT 29.505 14.720 32.040 14.860 ;
        RECT 29.505 14.675 29.795 14.720 ;
        RECT 31.825 14.565 32.040 14.720 ;
        RECT 6.525 14.520 6.815 14.565 ;
        RECT 9.285 14.520 9.575 14.565 ;
        RECT 6.525 14.380 9.575 14.520 ;
        RECT 6.525 14.335 6.815 14.380 ;
        RECT 9.285 14.335 9.575 14.380 ;
        RECT 31.825 14.520 32.115 14.565 ;
        RECT 33.665 14.520 33.955 14.565 ;
        RECT 31.825 14.380 33.955 14.520 ;
        RECT 31.825 14.335 32.115 14.380 ;
        RECT 33.665 14.335 33.955 14.380 ;
        RECT 6.985 14.180 7.275 14.225 ;
        RECT 7.890 14.180 8.210 14.240 ;
        RECT 17.550 14.180 17.870 14.240 ;
        RECT 6.985 14.040 8.210 14.180 ;
        RECT 17.355 14.040 17.870 14.180 ;
        RECT 6.985 13.995 7.275 14.040 ;
        RECT 7.890 13.980 8.210 14.040 ;
        RECT 17.550 13.980 17.870 14.040 ;
        RECT 23.085 14.180 23.375 14.225 ;
        RECT 24.910 14.180 25.230 14.240 ;
        RECT 23.085 14.040 25.230 14.180 ;
        RECT 23.085 13.995 23.375 14.040 ;
        RECT 24.910 13.980 25.230 14.040 ;
        RECT 8.825 13.160 9.115 13.205 ;
        RECT 9.270 13.160 9.590 13.220 ;
        RECT 16.645 13.160 16.935 13.205 ;
        RECT 8.825 13.020 16.935 13.160 ;
        RECT 8.825 12.975 9.115 13.020 ;
        RECT 9.270 12.960 9.590 13.020 ;
        RECT 16.645 12.975 16.935 13.020 ;
        RECT 7.890 12.820 8.210 12.880 ;
        RECT 17.550 12.820 17.870 12.880 ;
        RECT 24.910 12.820 25.230 12.880 ;
        RECT 7.695 12.680 8.210 12.820 ;
        RECT 17.355 12.680 17.870 12.820 ;
        RECT 24.715 12.680 25.230 12.820 ;
        RECT 7.890 12.620 8.210 12.680 ;
        RECT 17.550 12.620 17.870 12.680 ;
        RECT 24.910 12.620 25.230 12.680 ;
        RECT 25.830 12.480 26.150 12.540 ;
        RECT 25.635 12.340 26.150 12.480 ;
        RECT 25.830 12.280 26.150 12.340 ;
        RECT 25.830 10.440 26.150 10.500 ;
        RECT 25.635 10.300 26.150 10.440 ;
        RECT 25.830 10.240 26.150 10.300 ;
        RECT 22.625 9.420 22.915 9.465 ;
        RECT 28.605 9.420 28.895 9.465 ;
        RECT 22.625 9.280 28.895 9.420 ;
        RECT 22.625 9.235 22.915 9.280 ;
        RECT 28.605 9.235 28.895 9.280 ;
        RECT 12.030 9.080 12.350 9.140 ;
        RECT 11.835 8.940 12.350 9.080 ;
        RECT 12.030 8.880 12.350 8.940 ;
        RECT 26.305 9.080 26.595 9.125 ;
        RECT 29.065 9.080 29.355 9.125 ;
        RECT 26.305 8.940 29.355 9.080 ;
        RECT 26.305 8.895 26.595 8.940 ;
        RECT 29.065 8.895 29.355 8.940 ;
        RECT 11.110 8.740 11.430 8.800 ;
        RECT 21.230 8.740 21.550 8.800 ;
        RECT 10.915 8.600 21.550 8.740 ;
        RECT 11.110 8.540 11.430 8.600 ;
        RECT 21.230 8.540 21.550 8.600 ;
        RECT 23.085 8.740 23.375 8.785 ;
        RECT 25.370 8.740 25.690 8.800 ;
        RECT 23.085 8.600 25.690 8.740 ;
        RECT 23.085 8.555 23.375 8.600 ;
        RECT 25.370 8.540 25.690 8.600 ;
        RECT 6.065 7.720 6.355 7.765 ;
        RECT 11.110 7.720 11.430 7.780 ;
        RECT 25.370 7.720 25.690 7.780 ;
        RECT 31.350 7.720 31.670 7.780 ;
        RECT 6.065 7.580 11.430 7.720 ;
        RECT 25.175 7.580 25.690 7.720 ;
        RECT 31.155 7.580 31.670 7.720 ;
        RECT 6.065 7.535 6.355 7.580 ;
        RECT 11.110 7.520 11.430 7.580 ;
        RECT 25.370 7.520 25.690 7.580 ;
        RECT 31.350 7.520 31.670 7.580 ;
        RECT 9.285 7.380 9.575 7.425 ;
        RECT 12.045 7.380 12.335 7.425 ;
        RECT 9.285 7.240 12.335 7.380 ;
        RECT 9.285 7.195 9.575 7.240 ;
        RECT 12.045 7.195 12.335 7.240 ;
        RECT 5.590 7.040 5.910 7.100 ;
        RECT 9.730 7.040 10.050 7.100 ;
        RECT 5.395 6.900 5.910 7.040 ;
        RECT 9.535 6.900 10.050 7.040 ;
        RECT 5.590 6.840 5.910 6.900 ;
        RECT 9.730 6.840 10.050 6.900 ;
        RECT 12.965 7.040 13.255 7.085 ;
        RECT 15.265 7.040 15.555 7.085 ;
        RECT 18.470 7.040 18.790 7.100 ;
        RECT 12.965 6.900 15.555 7.040 ;
        RECT 18.275 6.900 18.790 7.040 ;
        RECT 12.965 6.855 13.255 6.900 ;
        RECT 15.265 6.855 15.555 6.900 ;
        RECT 18.470 6.840 18.790 6.900 ;
        RECT 19.405 7.040 19.695 7.085 ;
        RECT 21.705 7.040 21.995 7.085 ;
        RECT 19.405 6.900 21.995 7.040 ;
        RECT 19.405 6.855 19.695 6.900 ;
        RECT 21.705 6.855 21.995 6.900 ;
        RECT 22.625 7.040 22.915 7.085 ;
        RECT 24.925 7.040 25.215 7.085 ;
        RECT 22.625 6.900 25.215 7.040 ;
        RECT 22.625 6.855 22.915 6.900 ;
        RECT 24.925 6.855 25.215 6.900 ;
        RECT 15.725 6.020 16.015 6.065 ;
        RECT 18.010 6.020 18.330 6.080 ;
        RECT 31.810 6.020 32.130 6.080 ;
        RECT 15.725 5.880 18.330 6.020 ;
        RECT 31.615 5.880 32.130 6.020 ;
        RECT 15.725 5.835 16.015 5.880 ;
        RECT 18.010 5.820 18.330 5.880 ;
        RECT 31.810 5.820 32.130 5.880 ;
        RECT 5.590 5.000 5.910 5.060 ;
        RECT 5.395 4.860 5.910 5.000 ;
        RECT 5.590 4.800 5.910 4.860 ;
        RECT 9.730 5.000 10.050 5.060 ;
        RECT 12.505 5.000 12.795 5.045 ;
        RECT 18.470 5.000 18.790 5.060 ;
        RECT 9.730 4.860 12.795 5.000 ;
        RECT 18.275 4.860 18.790 5.000 ;
        RECT 9.730 4.800 10.050 4.860 ;
        RECT 12.505 4.815 12.795 4.860 ;
        RECT 18.470 4.800 18.790 4.860 ;
        RECT 12.030 3.980 12.350 4.040 ;
        RECT 18.010 3.980 18.330 4.040 ;
        RECT 11.835 3.840 12.350 3.980 ;
        RECT 17.815 3.840 18.330 3.980 ;
        RECT 12.030 3.780 12.350 3.840 ;
        RECT 18.010 3.780 18.330 3.840 ;
        RECT 31.810 3.980 32.130 4.040 ;
        RECT 32.285 3.980 32.575 4.025 ;
        RECT 31.810 3.840 32.575 3.980 ;
        RECT 31.810 3.780 32.130 3.840 ;
        RECT 32.285 3.795 32.575 3.840 ;
      LAYER via ;
        RECT 22.640 35.740 22.900 36.000 ;
        RECT 22.640 34.720 22.900 34.980 ;
        RECT 31.380 33.700 31.640 33.960 ;
        RECT 22.640 32.000 22.900 32.260 ;
        RECT 21.260 30.300 21.520 30.560 ;
        RECT 32.760 30.300 33.020 30.560 ;
        RECT 21.260 29.280 21.520 29.540 ;
        RECT 20.800 28.600 21.060 28.860 ;
        RECT 21.720 28.600 21.980 28.860 ;
        RECT 24.020 28.600 24.280 28.860 ;
        RECT 31.380 27.580 31.640 27.840 ;
        RECT 24.020 26.560 24.280 26.820 ;
        RECT 20.800 25.540 21.060 25.800 ;
        RECT 21.720 25.540 21.980 25.800 ;
        RECT 19.880 25.200 20.140 25.460 ;
        RECT 32.760 25.540 33.020 25.800 ;
        RECT 31.840 25.200 32.100 25.460 ;
        RECT 5.620 24.860 5.880 25.120 ;
        RECT 7.920 24.860 8.180 25.120 ;
        RECT 8.840 24.860 9.100 25.120 ;
        RECT 16.660 24.860 16.920 25.120 ;
        RECT 32.760 24.860 33.020 25.120 ;
        RECT 5.620 23.840 5.880 24.100 ;
        RECT 8.840 23.840 9.100 24.100 ;
        RECT 21.720 23.840 21.980 24.100 ;
        RECT 7.920 23.500 8.180 23.760 ;
        RECT 16.200 23.500 16.460 23.760 ;
        RECT 16.660 23.500 16.920 23.760 ;
        RECT 6.080 23.160 6.340 23.420 ;
        RECT 19.880 23.500 20.140 23.760 ;
        RECT 20.800 23.500 21.060 23.760 ;
        RECT 18.960 23.160 19.220 23.420 ;
        RECT 6.080 21.120 6.340 21.380 ;
        RECT 18.960 21.120 19.220 21.380 ;
        RECT 20.800 21.120 21.060 21.380 ;
        RECT 32.760 20.440 33.020 20.700 ;
        RECT 16.200 20.100 16.460 20.360 ;
        RECT 9.300 19.420 9.560 19.680 ;
        RECT 12.520 19.420 12.780 19.680 ;
        RECT 18.500 19.420 18.760 19.680 ;
        RECT 22.180 19.420 22.440 19.680 ;
        RECT 12.520 18.400 12.780 18.660 ;
        RECT 18.500 18.400 18.760 18.660 ;
        RECT 22.180 18.400 22.440 18.660 ;
        RECT 9.760 17.720 10.020 17.980 ;
        RECT 18.040 17.720 18.300 17.980 ;
        RECT 9.300 17.380 9.560 17.640 ;
        RECT 31.840 17.720 32.100 17.980 ;
        RECT 22.640 17.380 22.900 17.640 ;
        RECT 33.220 17.380 33.480 17.640 ;
        RECT 32.760 16.700 33.020 16.960 ;
        RECT 9.760 15.680 10.020 15.940 ;
        RECT 18.040 15.680 18.300 15.940 ;
        RECT 22.640 15.680 22.900 15.940 ;
        RECT 31.840 15.680 32.100 15.940 ;
        RECT 32.760 15.000 33.020 15.260 ;
        RECT 7.920 13.980 8.180 14.240 ;
        RECT 17.580 13.980 17.840 14.240 ;
        RECT 24.940 13.980 25.200 14.240 ;
        RECT 9.300 12.960 9.560 13.220 ;
        RECT 7.920 12.620 8.180 12.880 ;
        RECT 17.580 12.620 17.840 12.880 ;
        RECT 24.940 12.620 25.200 12.880 ;
        RECT 25.860 12.280 26.120 12.540 ;
        RECT 25.860 10.240 26.120 10.500 ;
        RECT 12.060 8.880 12.320 9.140 ;
        RECT 11.140 8.540 11.400 8.800 ;
        RECT 21.260 8.540 21.520 8.800 ;
        RECT 25.400 8.540 25.660 8.800 ;
        RECT 11.140 7.520 11.400 7.780 ;
        RECT 25.400 7.520 25.660 7.780 ;
        RECT 31.380 7.520 31.640 7.780 ;
        RECT 5.620 6.840 5.880 7.100 ;
        RECT 9.760 6.840 10.020 7.100 ;
        RECT 18.500 6.840 18.760 7.100 ;
        RECT 18.040 5.820 18.300 6.080 ;
        RECT 31.840 5.820 32.100 6.080 ;
        RECT 5.620 4.800 5.880 5.060 ;
        RECT 9.760 4.800 10.020 5.060 ;
        RECT 18.500 4.800 18.760 5.060 ;
        RECT 12.060 3.780 12.320 4.040 ;
        RECT 18.040 3.780 18.300 4.040 ;
        RECT 31.840 3.780 32.100 4.040 ;
      LAYER met2 ;
        RECT 22.640 35.710 22.900 36.030 ;
        RECT 22.700 35.010 22.840 35.710 ;
        RECT 22.640 34.690 22.900 35.010 ;
        RECT 22.700 32.290 22.840 34.690 ;
        RECT 31.380 33.670 31.640 33.990 ;
        RECT 22.640 31.970 22.900 32.290 ;
        RECT 21.260 30.270 21.520 30.590 ;
        RECT 21.320 29.570 21.460 30.270 ;
        RECT 21.260 29.250 21.520 29.570 ;
        RECT 20.800 28.570 21.060 28.890 ;
        RECT 21.720 28.570 21.980 28.890 ;
        RECT 24.020 28.570 24.280 28.890 ;
        RECT 20.860 25.830 21.000 28.570 ;
        RECT 21.780 25.830 21.920 28.570 ;
        RECT 24.080 26.850 24.220 28.570 ;
        RECT 31.440 27.870 31.580 33.670 ;
        RECT 32.760 30.270 33.020 30.590 ;
        RECT 31.380 27.550 31.640 27.870 ;
        RECT 24.020 26.530 24.280 26.850 ;
        RECT 20.800 25.510 21.060 25.830 ;
        RECT 21.720 25.510 21.980 25.830 ;
        RECT 19.880 25.170 20.140 25.490 ;
        RECT 5.620 24.830 5.880 25.150 ;
        RECT 7.920 24.830 8.180 25.150 ;
        RECT 8.840 24.830 9.100 25.150 ;
        RECT 16.660 24.830 16.920 25.150 ;
        RECT 5.680 24.130 5.820 24.830 ;
        RECT 5.620 23.810 5.880 24.130 ;
        RECT 7.980 23.790 8.120 24.830 ;
        RECT 8.900 24.130 9.040 24.830 ;
        RECT 8.840 23.810 9.100 24.130 ;
        RECT 16.720 23.790 16.860 24.830 ;
        RECT 19.940 23.790 20.080 25.170 ;
        RECT 20.860 24.210 21.000 25.510 ;
        RECT 20.860 24.070 21.460 24.210 ;
        RECT 21.780 24.130 21.920 25.510 ;
        RECT 7.920 23.470 8.180 23.790 ;
        RECT 16.200 23.470 16.460 23.790 ;
        RECT 16.660 23.470 16.920 23.790 ;
        RECT 19.880 23.470 20.140 23.790 ;
        RECT 20.800 23.470 21.060 23.790 ;
        RECT 6.080 23.130 6.340 23.450 ;
        RECT 6.140 21.410 6.280 23.130 ;
        RECT 6.080 21.090 6.340 21.410 ;
        RECT 16.260 20.390 16.400 23.470 ;
        RECT 18.960 23.130 19.220 23.450 ;
        RECT 19.020 21.410 19.160 23.130 ;
        RECT 20.860 21.410 21.000 23.470 ;
        RECT 18.960 21.090 19.220 21.410 ;
        RECT 20.800 21.090 21.060 21.410 ;
        RECT 16.200 20.070 16.460 20.390 ;
        RECT 9.300 19.390 9.560 19.710 ;
        RECT 12.520 19.390 12.780 19.710 ;
        RECT 18.500 19.390 18.760 19.710 ;
        RECT 9.360 17.670 9.500 19.390 ;
        RECT 12.580 18.690 12.720 19.390 ;
        RECT 18.560 18.690 18.700 19.390 ;
        RECT 12.520 18.370 12.780 18.690 ;
        RECT 18.500 18.370 18.760 18.690 ;
        RECT 9.760 17.690 10.020 18.010 ;
        RECT 18.040 17.690 18.300 18.010 ;
        RECT 9.300 17.350 9.560 17.670 ;
        RECT 7.920 13.950 8.180 14.270 ;
        RECT 7.980 12.910 8.120 13.950 ;
        RECT 9.360 13.250 9.500 17.350 ;
        RECT 9.820 15.970 9.960 17.690 ;
        RECT 18.100 15.970 18.240 17.690 ;
        RECT 9.760 15.650 10.020 15.970 ;
        RECT 18.040 15.650 18.300 15.970 ;
        RECT 17.580 13.950 17.840 14.270 ;
        RECT 9.300 12.930 9.560 13.250 ;
        RECT 17.640 12.910 17.780 13.950 ;
        RECT 7.920 12.590 8.180 12.910 ;
        RECT 17.580 12.590 17.840 12.910 ;
        RECT 12.060 8.850 12.320 9.170 ;
        RECT 11.140 8.510 11.400 8.830 ;
        RECT 11.200 7.810 11.340 8.510 ;
        RECT 11.140 7.490 11.400 7.810 ;
        RECT 5.620 6.810 5.880 7.130 ;
        RECT 9.760 6.810 10.020 7.130 ;
        RECT 5.680 5.090 5.820 6.810 ;
        RECT 9.820 5.090 9.960 6.810 ;
        RECT 5.620 4.770 5.880 5.090 ;
        RECT 9.760 4.770 10.020 5.090 ;
        RECT 12.120 4.070 12.260 8.850 ;
        RECT 21.320 8.830 21.460 24.070 ;
        RECT 21.720 23.810 21.980 24.130 ;
        RECT 22.180 19.390 22.440 19.710 ;
        RECT 22.240 18.690 22.380 19.390 ;
        RECT 22.180 18.370 22.440 18.690 ;
        RECT 22.640 17.350 22.900 17.670 ;
        RECT 22.700 15.970 22.840 17.350 ;
        RECT 22.640 15.650 22.900 15.970 ;
        RECT 24.940 13.950 25.200 14.270 ;
        RECT 25.000 12.910 25.140 13.950 ;
        RECT 24.940 12.590 25.200 12.910 ;
        RECT 25.860 12.250 26.120 12.570 ;
        RECT 25.920 10.530 26.060 12.250 ;
        RECT 25.860 10.210 26.120 10.530 ;
        RECT 21.260 8.510 21.520 8.830 ;
        RECT 25.400 8.510 25.660 8.830 ;
        RECT 25.460 7.810 25.600 8.510 ;
        RECT 31.440 7.810 31.580 27.550 ;
        RECT 32.820 25.830 32.960 30.270 ;
        RECT 32.760 25.570 33.020 25.830 ;
        RECT 32.760 25.510 33.420 25.570 ;
        RECT 31.840 25.170 32.100 25.490 ;
        RECT 32.820 25.430 33.420 25.510 ;
        RECT 31.900 18.010 32.040 25.170 ;
        RECT 32.760 24.830 33.020 25.150 ;
        RECT 32.820 20.730 32.960 24.830 ;
        RECT 32.760 20.410 33.020 20.730 ;
        RECT 31.840 17.690 32.100 18.010 ;
        RECT 31.900 15.970 32.040 17.690 ;
        RECT 33.280 17.670 33.420 25.430 ;
        RECT 33.220 17.350 33.480 17.670 ;
        RECT 32.760 16.670 33.020 16.990 ;
        RECT 31.840 15.650 32.100 15.970 ;
        RECT 32.820 15.290 32.960 16.670 ;
        RECT 32.760 14.970 33.020 15.290 ;
        RECT 25.400 7.490 25.660 7.810 ;
        RECT 31.380 7.490 31.640 7.810 ;
        RECT 18.500 6.810 18.760 7.130 ;
        RECT 18.040 5.790 18.300 6.110 ;
        RECT 18.100 4.070 18.240 5.790 ;
        RECT 18.560 5.090 18.700 6.810 ;
        RECT 31.840 5.790 32.100 6.110 ;
        RECT 18.500 4.770 18.760 5.090 ;
        RECT 31.900 4.070 32.040 5.790 ;
        RECT 12.060 3.750 12.320 4.070 ;
        RECT 18.040 3.750 18.300 4.070 ;
        RECT 31.840 3.750 32.100 4.070 ;
  END
END NON_CLK_GEN
END LIBRARY
